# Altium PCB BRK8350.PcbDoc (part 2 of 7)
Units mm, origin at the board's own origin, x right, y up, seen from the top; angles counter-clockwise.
Board outline 240 x 150 mm, 8 copper layers (L1-TOP, L2-GND, L3-PWR, L4-SIG, L5-SIG, L6-PWR, L7-GND, L8-BOT), stack 1.465 mm thick; 277 components, 542 nets, 1814 pads, 2338 vias.

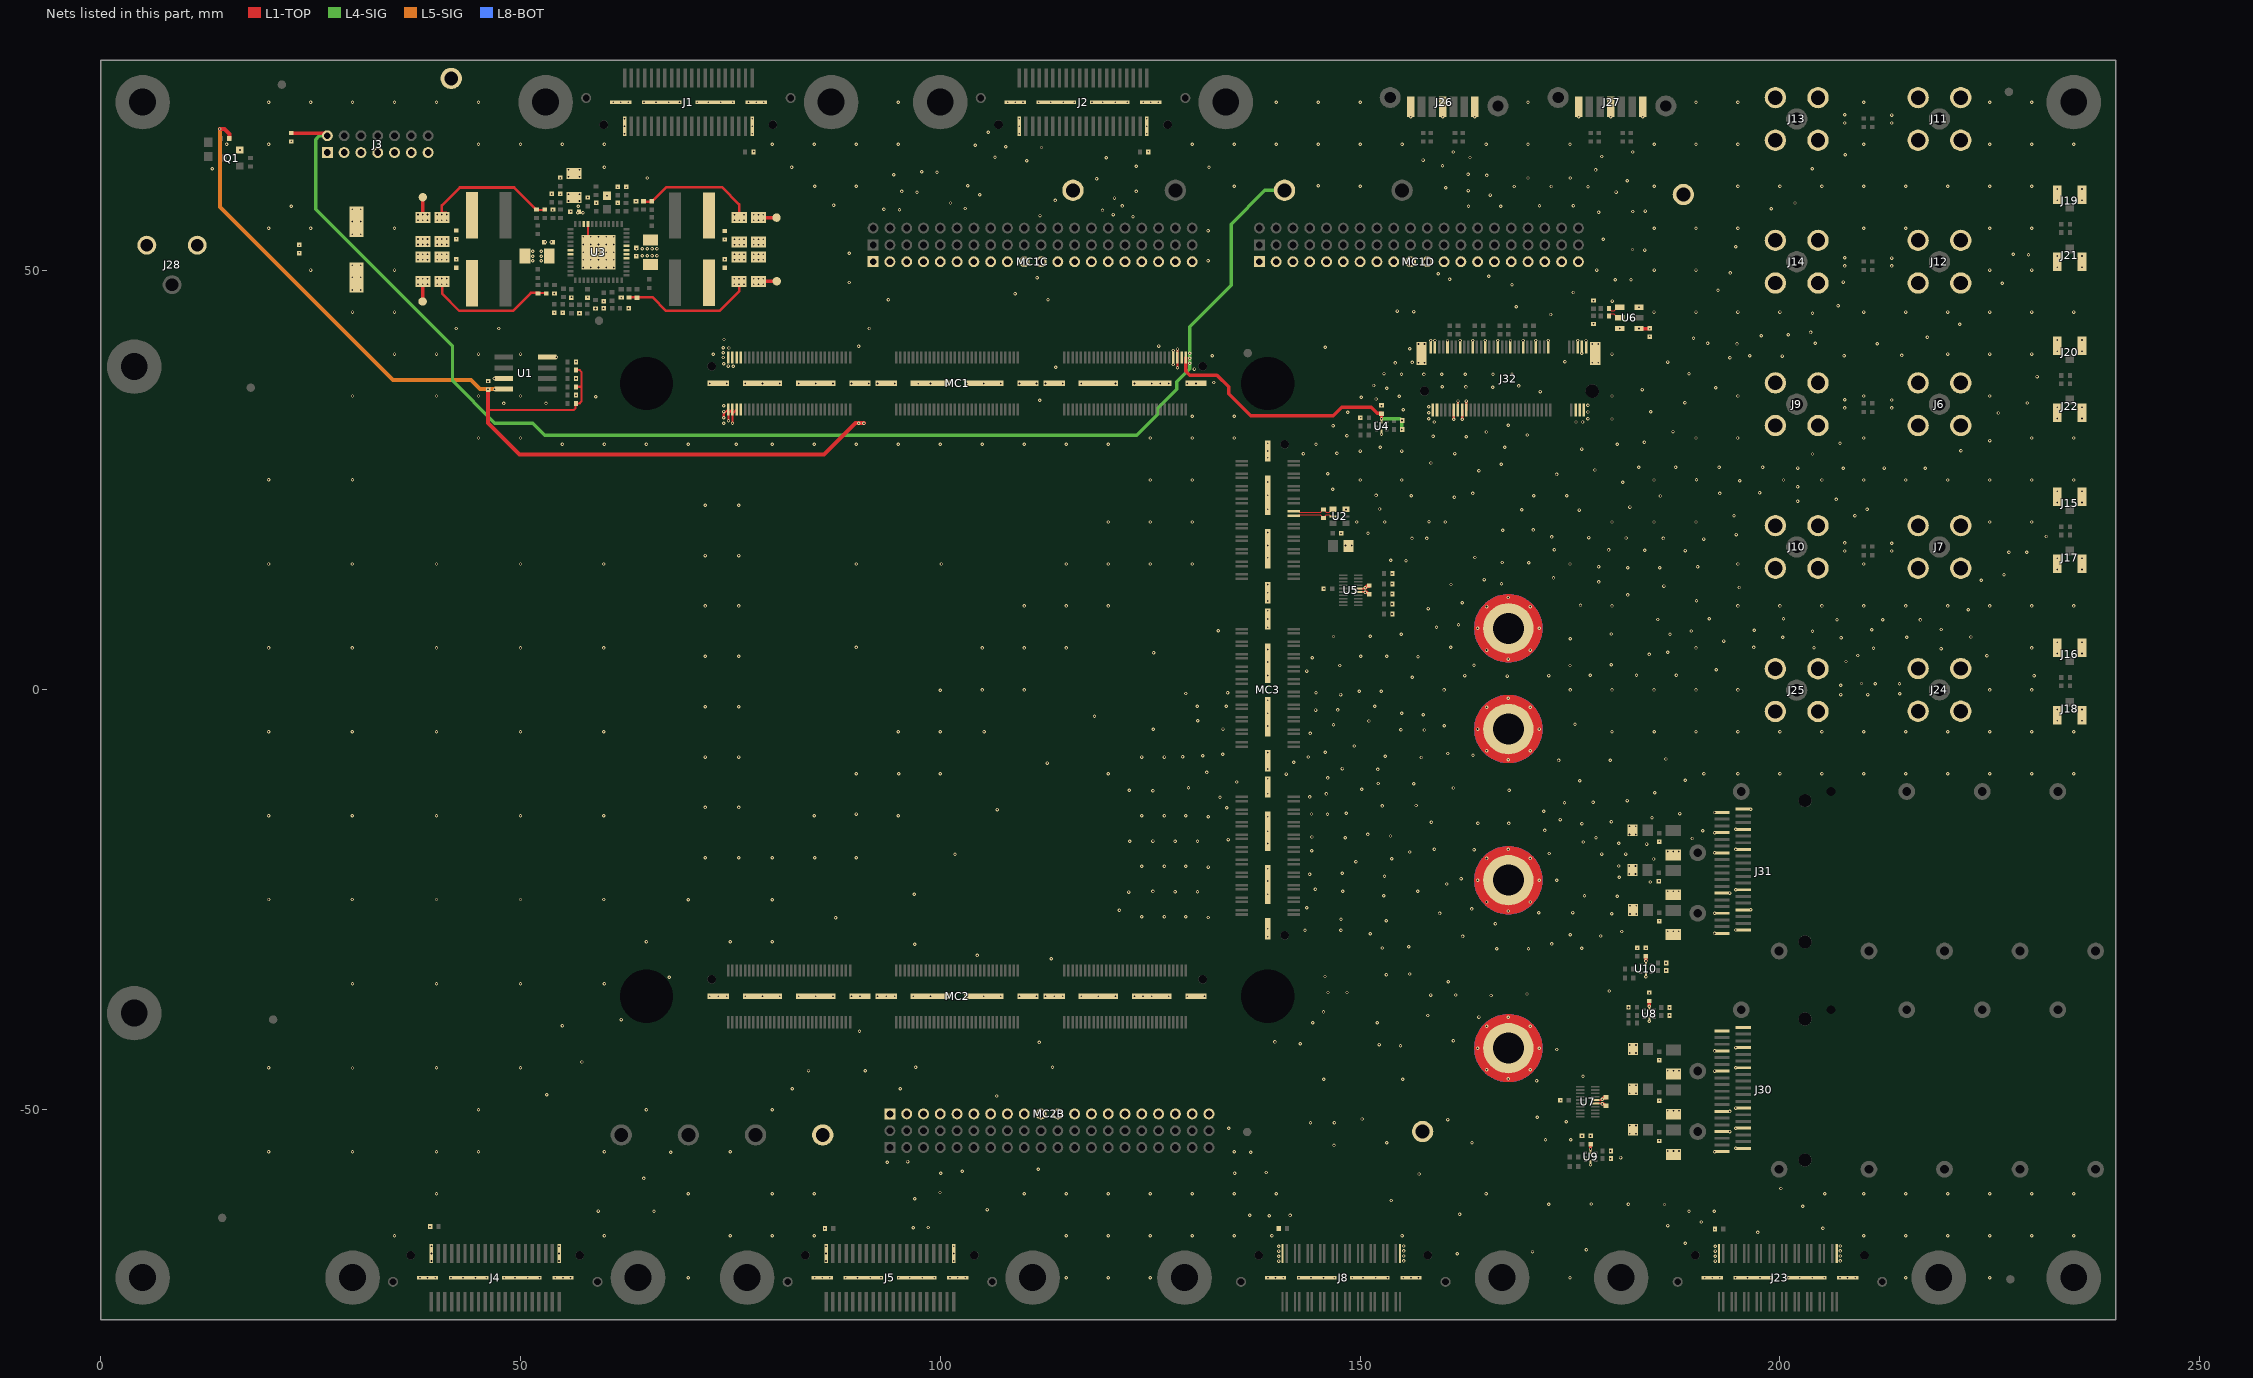
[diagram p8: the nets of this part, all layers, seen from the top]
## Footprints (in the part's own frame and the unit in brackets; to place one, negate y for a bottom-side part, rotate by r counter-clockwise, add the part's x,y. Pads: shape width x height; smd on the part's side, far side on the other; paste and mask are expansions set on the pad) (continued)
QSFP28_SINGLE_CAGE [mm]
  round 2 hole 1.05: 0(-1.1,3.1) 0(-1.1,-7.6) 0(-1.1,-16.6) 0(-1.1,-25.6) 0(-1.1,-34.6) 0(3.4,12.79) 0(10.6,12.79) 0(17.9,-21.1) 0(17.9,-12.1) 0(17.9,7.6) 0(17.9,-30.1)
  round 0 hole 1.05 unplated: 0(17.9,-3.1)
  L1-TOP keep-out region: -2.7,13.5 -2.7,-37 19.5,-37 19.5,13.5 16.5,13.5 16.5,11.1 18,11.1 18,-1.6 15.9,-1.6 15.9,-3.5 0.9,-3.5 0.9,-1.6 -1.2,-1.6 -1.2,11.1 0.3,11.1 0.3,13.5
  silkscreen extent -1.1,-48.2 17.9,12.9
QSH-020-01-X-D-DP-A-L [mm] "0.5mm hi-speed, high-density header (male), 80-pin, latching, ground protection in middle"
  rect 2.54x0.43 smd mask+0.051: 0(-8.07,0) 0(8.06,0)
  rect 4.7x0.43 smd mask+0.051: 0(-3.18,0) 0(3.17,0)
  rect 0.28x2.27 smd mask+0.051: 1(-7.25,-2.87) 2(-7.25,2.87) 3(-6.75,-2.87) 4(-6.75,2.87) 5(-5.75,-2.87) 6(-5.75,2.87) 7(-5.25,-2.87) 8(-5.25,2.87) 9(-4.25,-2.87) 10(-4.25,2.87) 11(-3.75,-2.87) 12(-3.75,2.87) 13(-2.75,-2.87) 14(-2.75,2.87) 15(-2.25,-2.87) 16(-2.25,2.87) 17(-1.25,-2.87) 18(-1.25,2.87) 19(-0.75,-2.87) 20(-0.75,2.87) 21(0.25,-2.87) 22(0.25,2.87) 23(0.75,-2.87) 24(0.75,2.87) 25(1.75,-2.87) 26(1.75,2.87) 27(2.25,-2.87) 28(2.25,2.87) 29(3.25,-2.87) 30(3.25,2.87) 31(3.75,-2.87) 32(3.75,2.87) 33(4.75,-2.87) 34(4.75,2.87) 35(5.25,-2.87) 36(5.25,2.87) 37(6.25,-2.87) 38(6.25,2.87) 39(6.75,-2.87) 40(6.75,2.87)
  round 1.2 hole 0.8 paste+0 mask+0.076: MH(-12.18,-0.5) MH(12.18,-0.5)
  round 1.02 hole 1.02 unplated paste+0: MH(-10.07,2.67) MH(10.07,2.67)
  silkscreen extent -13.4,-3.7 13.4,3.7
QTH-060-01-X-D-DP-A [mm] "2mm 1x20 Header"
  rect 2.54x0.64 smd: 0(-28.445,0) 0(-11.555,0) 0(-8.445,0) 0(8.445,0) 0(11.555,0) 0(28.445,0)
  rect 4.7x0.64 smd: 0(-23.175,0) 0(-16.825,0) 0(-3.175,0) 0(3.175,0) 0(16.825,0) 0(23.175,0)
  rect 0.3x1.45 smd: 1(-27.25,3.09) 2(-27.25,-3.09) 3(-26.75,3.09) 4(-26.75,-3.09) 5(-25.75,3.09) 6(-25.75,-3.09) 7(-25.25,3.09) 8(-25.25,-3.09) 9(-24.25,3.09) 10(-24.25,-3.09) 11(-23.75,3.09) 12(-23.75,-3.09) 13(-22.75,3.09) 14(-22.75,-3.09) 15(-22.25,3.09) 16(-22.25,-3.09) 17(-21.25,3.09) 18(-21.25,-3.09) 19(-20.75,3.09) 20(-20.75,-3.09) 21(-19.75,3.09) 22(-19.75,-3.09) 23(-19.25,3.09) 24(-19.25,-3.09) 25(-18.25,3.09) 26(-18.25,-3.09) 27(-17.75,3.09) 28(-17.75,-3.09) 29(-16.75,3.09) 30(-16.75,-3.09) 31(-16.25,3.09) 32(-16.25,-3.09) 33(-15.25,3.09) 34(-15.25,-3.09) 35(-14.75,3.09) 36(-14.75,-3.09) 37(-13.75,3.09) 38(-13.75,-3.09) 39(-13.25,3.09) 40(-13.25,-3.09) 41(-7.25,3.09) 42(-7.25,-3.09) 43(-6.75,3.09) 44(-6.75,-3.09) 45(-5.75,3.09) 46(-5.75,-3.09) 47(-5.25,3.09) 48(-5.25,-3.09) 49(-4.25,3.09) 50(-4.25,-3.09) 51(-3.75,3.09) 52(-3.75,-3.09) 53(-2.75,3.09) 54(-2.75,-3.09) 55(-2.25,3.09) 56(-2.25,-3.09) 57(-1.25,3.09) 58(-1.25,-3.09) 59(-0.75,3.09) 60(-0.75,-3.09) 61(0.25,3.09) 62(0.25,-3.09) 63(0.75,3.09) 64(0.75,-3.09) 65(1.75,3.09) 66(1.75,-3.09) 67(2.25,3.09) 68(2.25,-3.09) 69(3.25,3.09) 70(3.25,-3.09) 71(3.75,3.09) 72(3.75,-3.09) 73(4.75,3.09) 74(4.75,-3.09) 75(5.25,3.09) 76(5.25,-3.09) 77(6.25,3.09) 78(6.25,-3.09) 79(6.75,3.09) 80(6.75,-3.09) 81(12.75,3.09) 82(12.75,-3.09) 83(13.25,3.09) 84(13.25,-3.09) 85(14.25,3.09) 86(14.25,-3.09) 87(14.75,3.09) 88(14.75,-3.09) 89(15.75,3.09) 90(15.75,-3.09) 91(16.25,3.09) 92(16.25,-3.09) 93(17.25,3.09) 94(17.25,-3.09) 95(17.75,3.09) 96(17.75,-3.09) 97(18.75,3.09) 98(18.75,-3.09) 99(19.25,3.09) 100(19.25,-3.09) 101(20.25,3.09) 102(20.25,-3.09) 103(20.75,3.09) 104(20.75,-3.09) 105(21.75,3.09) 106(21.75,-3.09) 107(22.25,3.09) 108(22.25,-3.09) 109(23.25,3.09) 110(23.25,-3.09) 111(23.75,3.09) 112(23.75,-3.09) 113(24.75,3.09) 114(24.75,-3.09) 115(25.25,3.09) 116(25.25,-3.09) 117(26.25,3.09) 118(26.25,-3.09) 119(26.75,3.09) 120(26.75,-3.09)
  round 1.02 hole 1.02 unplated: MH(-29.24,2.03) MH(29.24,2.03)
  silkscreen extent -30.05,-3.05 30.05,3.05
QTH-090-01-X-D [mm]
  rect 2.54x0.64 smd: 0(-28.445,0) 0(-11.555,0) 0(-8.445,0) 0(8.445,0) 0(11.555,0) 0(28.445,0)
  rect 4.7x0.64 smd: 0(-23.175,0) 0(-16.825,0) 0(-3.175,0) 0(3.175,0) 0(16.825,0) 0(23.175,0)
  rect 0.3x1.45 smd: 1(-27.25,3.09) 2(-27.25,-3.09) 3(-26.75,3.09) 4(-26.75,-3.09) 5(-26.25,3.09) 6(-26.25,-3.09) 7(-25.75,3.09) 8(-25.75,-3.09) 9(-25.25,3.09) 10(-25.25,-3.09) 11(-24.75,3.09) 12(-24.75,-3.09) 13(-24.25,3.09) 14(-24.25,-3.09) 15(-23.75,3.09) 16(-23.75,-3.09) 17(-23.25,3.09) 18(-23.25,-3.09) 19(-22.75,3.09) 20(-22.75,-3.09) 21(-22.25,3.09) 22(-22.25,-3.09) 23(-21.75,3.09) 24(-21.75,-3.09) 25(-21.25,3.09) 26(-21.25,-3.09) 27(-20.75,3.09) 28(-20.75,-3.09) 29(-20.25,3.09) 30(-20.25,-3.09) 31(-19.75,3.09) 32(-19.75,-3.09) 33(-19.25,3.09) 34(-19.25,-3.09) 35(-18.75,3.09) 36(-18.75,-3.09) 37(-18.25,3.09) 38(-18.25,-3.09) 39(-17.75,3.09) 40(-17.75,-3.09) 41(-17.25,3.09) 42(-17.25,-3.09) 43(-16.75,3.09) 44(-16.75,-3.09) 45(-16.25,3.09) 46(-16.25,-3.09) 47(-15.75,3.09) 48(-15.75,-3.09) 49(-15.25,3.09) 50(-15.25,-3.09) 51(-14.75,3.09) 52(-14.75,-3.09) 53(-14.25,3.09) 54(-14.25,-3.09) 55(-13.75,3.09) 56(-13.75,-3.09) 57(-13.25,3.09) 58(-13.25,-3.09) 59(-12.75,3.09) 60(-12.75,-3.09) 61(-7.25,3.09) 62(-7.25,-3.09) 63(-6.75,3.09) 64(-6.75,-3.09) 65(-6.25,3.09) 66(-6.25,-3.09) 67(-5.75,3.09) 68(-5.75,-3.09) 69(-5.25,3.09) 70(-5.25,-3.09) 71(-4.75,3.09) 72(-4.75,-3.09) 73(-4.25,3.09) 74(-4.25,-3.09) 75(-3.75,3.09) 76(-3.75,-3.09) 77(-3.25,3.09) 78(-3.25,-3.09) 79(-2.75,3.09) 80(-2.75,-3.09) 81(-2.25,3.09) 82(-2.25,-3.09) 83(-1.75,3.09) 84(-1.75,-3.09) 85(-1.25,3.09) 86(-1.25,-3.09) 87(-0.75,3.09) 88(-0.75,-3.09) 89(-0.25,3.09) 90(-0.25,-3.09) 91(0.25,3.09) 92(0.25,-3.09) 93(0.75,3.09) 94(0.75,-3.09) 95(1.25,3.09) 96(1.25,-3.09) 97(1.75,3.09) 98(1.75,-3.09) 99(2.25,3.09) 100(2.25,-3.09) 101(2.75,3.09) 102(2.75,-3.09) 103(3.25,3.09) 104(3.25,-3.09) 105(3.75,3.09) 106(3.75,-3.09) 107(4.25,3.09) 108(4.25,-3.09) 109(4.75,3.09) 110(4.75,-3.09) 111(5.25,3.09) 112(5.25,-3.09) 113(5.75,3.09) 114(5.75,-3.09) 115(6.25,3.09) 116(6.25,-3.09) 117(6.75,3.09) 118(6.75,-3.09) 119(7.25,3.09) 120(7.25,-3.09) 121(12.75,3.09) 122(12.75,-3.09) 123(13.25,3.09) 124(13.25,-3.09) 125(13.75,3.09) 126(13.75,-3.09) 127(14.25,3.09) 128(14.25,-3.09) 129(14.75,3.09) 130(14.75,-3.09) 131(15.25,3.09) 132(15.25,-3.09) 133(15.75,3.09) 134(15.75,-3.09) 135(16.25,3.09) 136(16.25,-3.09) 137(16.75,3.09) 138(16.75,-3.09) 139(17.25,3.09) 140(17.25,-3.09) 141(17.75,3.09) 142(17.75,-3.09) 143(18.25,3.09) 144(18.25,-3.09) 145(18.75,3.09) 146(18.75,-3.09) 147(19.25,3.09) 148(19.25,-3.09) 149(19.75,3.09) 150(19.75,-3.09) 151(20.25,3.09) 152(20.25,-3.09) 153(20.75,3.09) 154(20.75,-3.09) 155(21.25,3.09) 156(21.25,-3.09) 157(21.75,3.09) 158(21.75,-3.09) 159(22.25,3.09) 160(22.25,-3.09) 161(22.75,3.09) 162(22.75,-3.09) 163(23.25,3.09) 164(23.25,-3.09) 165(23.75,3.09) 166(23.75,-3.09) 167(24.25,3.09) 168(24.25,-3.09) 169(24.75,3.09) 170(24.75,-3.09) 171(25.25,3.09) 172(25.25,-3.09) 173(25.75,3.09) 174(25.75,-3.09) 175(26.25,3.09) 176(26.25,-3.09) 177(26.75,3.09) 178(26.75,-3.09) 179(27.25,3.09) 180(27.25,-3.09)
  round 1.02 hole 1.02 unplated: MH(-29.24,2.03) MH(29.24,2.03)
  silkscreen extent -30.05,-3.05 30.05,3.05
RESC1005X06A [mm] "Chip Resistor, 2-Leads, Body 1.00x0.50mm, OK custom footprint"
  rect 0.5x0.6 smd mask+0.051: 1(-0.5,0) 2(0.5,0)
RESC2012N [mm] "Chip Resistor, Body 2.0x1.3mm, IPC Medium Density"
  rect 1.2x1.4 smd: 1(-0.9,0) 2(0.9,0)
  silkscreen extent -0.85,-0.89 0.85,0.88, body extent -1.07,-0.7 1.07,0.7, height 0.65
SMA [mil] "PCB-mount SMA connector"
  round 100 hole 59: 1(0,0)
  round 100 hole 67: 2(-100,100) 2(-100,-100) 2(100,100) 2(100,-100)
  Top Overlay keep-out lines w10: 170,170 -170,170 -170,-170 170,-170 170,170
  silkscreen extent -170,-170 170,170
SO-G8 [mm] "Small Outline; 8 Leads; Body Width 3.9 mm; Pitch 1.27 mm"
  rect 0.6x2.2 smd: 1(-1.905,-2.6) 2(-0.635,-2.6) 3(0.635,-2.6) 4(1.905,-2.6) 5(1.905,2.6) 6(0.635,2.6) 7(-0.635,2.6) 8(-1.905,2.6)
  silkscreen extent -2.45,-3.7 2.45,1.95
SOT23-95P240X110 [mm] "SOT-23; 3 Leads; Body 3.0 x 2.6 mm, inc. leads (LxW max)"
  rect 0.8x0.9 smd: 1(-0.95,-1) 2(0.95,-1) 3(0,1)
  silkscreen extent -1.53,-1.45 1.54,0.77
TP-PTH-65/100#1 [mil] "Test point, plated through-hole, 65/100mil"
  round 100 hole 65: 1(0,0)
TP-PTH-65/100#2 [mil] "Test point, plated through-hole, 65/100mil"
  round 100 hole 65: 1(0,0.49)
TP-PTH-65/100#3 [mil] "Test point, plated through-hole, 65/100mil"
  round 100 hole 65: 1(-4.91,0.44)
TP-SMD40 [mm] "Test point, surface-mount, 40mil"
  round 1 smd paste-2: 1(0,0)
TXB0108DQSR [mm] "TI R-PUSON-N20"
  rect 0.2x1 smd mask+0.051: 1(-1.8,-0.9) 2(-1.4,-0.9) 3(-1,-0.9) 4(-0.6,-0.9) 5(-0.2,-0.9) 6(0.2,-0.9) 7(0.6,-0.9) 8(1,-0.9) 9(1.4,-0.9) 10(1.8,-0.9) 11(1.8,0.9) 12(1.4,0.9) 13(1,0.9) 14(0.6,0.9) 15(0.2,0.9) 16(-0.2,0.9) 17(-0.6,0.9) 18(-1,0.9) 19(-1.4,0.9) 20(-1.8,0.9)
  silkscreen extent -2.16,-1.6 2.16,1.01, body extent -2,-1 2,1, height 0.5
UFL-R-SMT-1 [mm] "U.FL surface-mount coaxial connector"
  rect 1x1.05 smd paste+0: 1(0,-1.525)
  rect 1.05x2.2 smd paste+0: 2(-1.475,0) 2(1.475,0)
  silkscreen extent -1.3,-1.3 1.3,1.3
XAL60XX [mm]
  rect 1.43x5.5 smd: 1(-2.02,0) 2(2.02,0)
  silkscreen extent -3.25,-3.35 3.25,3.35
XILINX-JTAG [mm] "2mm 2x7 header"
  rect 1.3x1.3 hole 0.8: 1(-6,-1)
  round 1.3 hole 0.8: 2(-6,1) 3(-4,-1) 4(-4,1) 5(-2,-1) 6(-2,1) 7(0,-1) 8(0,1) 9(2,-1) 10(2,1) 11(4,-1) 12(4,1) 13(6,-1) 14(6,1)
  silkscreen extent -8.32,-3.15 8.32,3.15

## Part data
*1: library part OKLOGO, partnumber=ALIGNI_IGNORE
C1 C4 C6 C7 C8 C9 C10 C11 C12 C13 C14 C15 C16 C17 C18 C19 C20 C21 C22 C23 C24 C25 C26 C27 C28 C29 C75 C76 C85 C86 C88 C90 C92 C95 C96 C97 C98 C99 C100 C101 C102 C104 C107 C108 C109: library part 000070, Manufacturer=Kemet, Manufacturer_PN=C0402C104K8PACTU, ValueFloat=1E-7, x_tolerance=10
C2: library part 000070, Manufacturer=Kemet, Manufacturer_PN=C0402C104K8PACTU, ValueFloat=1E-7, x_max_operating_temp=85, x_min_operating_temp=-55, x_tolerance=10
C30: library part 001346, "Ceramic capacitor", Manufacturer="Taiyo Yuden", Tolerance (%)=20, ValueFloat=1E-5
C31: library part 000824, "Ceramic capacitor", Manufacturer="Taiyo Yuden", Tolerance (%)=20, ValueFloat=4.7E-6
C32: library part 001926, Manufacturer=TDK, ValueFloat=3.3E-6, x_tolerance=20
C33 C46 C57: library part 001172, "Ceramic Capacitor", Manufacturer=TDK, Tolerance (%)=20, ValueFloat=2.2E-5, Voltage=35V, x_voltage-rating=35
C34 C37 C47 C58: library part 001073, "Ceramic capacitor", Manufacturer="Taiyo Yuden", Tolerance (%)=10, ValueFloat=1E-7, Voltage=25V
C35 C38 C43 C45 C48 C51 C55 C56 C59 C63 C66 C67: library part 000070, "Ceramic capacitor", Manufacturer=Kemet, Tolerance (%)=10, ValueFloat=1E-7
C36: library part 001532, "Polarized", Manufacturer=Panasonic, ValueFloat=0.00022, Voltage=25V, x_tolerance=20, x_voltage-rating=25
C39 C40 C49 C50 C60 C61 C68 C69: library part 001284, "Ceramic capacitor", Manufacturer="Taiyo Yuden", Tolerance (%)=10, ValueFloat=2.2E-5
C41 C52: library part 001004, Manufacturer=Kemet, Manufacturer_PN=C0402C560J5GACTU, ValueFloat=5.6E-11, x_temperature_characteristic=C0G, x_tolerance=5
C42 C53 C64 C72: library part 000930, "Ceramic capacitor", Manufacturer=Kemet, Tolerance (%)=10, ValueFloat=4.7E-9
C44 C54 C65 C74: library part 000807, "Ceramic capacitor", Manufacturer=Kemet, Tolerance (%)=5, ValueFloat=2.2E-11
C62 C70: library part 001004, "Ceramic capacitor", Manufacturer=Kemet, Tolerance (%)=5, ValueFloat=5.6E-11
C71: library part 000400, Manufacturer=Kemet, Manufacturer_PN=C0402C101J5GACTU, ValueFloat=1E-10
C73: library part 000962, "Ceramic capacitor", Manufacturer=Murata, Tolerance (%)=3.125, ValueFloat=5E-12
C77 C78 C79 C80 C81 C82 C83 C84: library part 000333, Manufacturer="Taiyo Yuden", Manufacturer_PN=LMK105BJ224KV-F, ValueFloat=2.2E-7, x_temperature_characteristic=X5R, x_tolerance=10
C91 C93 C94 C103 C105 C106: library part 001284, Manufacturer="Taiyo Yuden", Manufacturer_PN=LMK316AB7226KL-TR, ValueFloat=2.2E-5, x_temperature_characteristic=X7R, x_tolerance=10
D1: library part 001433, "LED", Manufacturer=Dialight, Manufacturer_PN=598-8070-107F
FB1 FB2 FB3 FB4 FB5 FB6 FB7: library part 000783, Manufacturer=Murata, Manufacturer_PN=BLM21PG221SN1D, ValueFloat=220
FID1 FID2 FID3 FID4 FID5 FID6 FID7 FID8: "PCB fiducial", partnumber=ALIGNI_IGNORE
J1 J2 J4 J5: library part 001604, "0.8mm hi-speed, high-density header (male)", Manufacturer=Samtec
J3: library part 000541, "2mm header, shrouded", Manufacturer=Molex
J6 J7 J9 J10 J11 J12 J13 J14 J24 J25: library part 000974, "Straight SMA PCB Mount", Manufacturer=Amphenol, Manufacturer_PN=901-144-8RFX
J8 J23: library part 000694, "0.5mm Double Row High Speed Socket Assembly", Manufacturer=Samtec
J15 J16 J17 J18 J19 J20 J21 J22: library part 001335, "U.FL surface-mount coaxial connector", Manufacturer=Hirose, Manufacturer_PN=U.FL-R-SMT-1
J26 J27: library part 000988, "SATA 7-pin receptacle", Manufacturer=Molex
J28: library part DCPOWER, "DC power connector - high current", Manufacturer="CUI Inc.", partnumber=000356
J30 J31: library part 001782, Manufacturer=Amphenol
J32: library part 001722, Manufacturer=Amphenol
JSO1 JSO2 JSO3 JSO4: library part 001879, "Mounting hole", Manufacturer=Samtec, Manufacturer_PN=JSO-0515-01
L1 L2 L3 L4: library part 001543, "Power inductor, 2.2uH, 7A, 12.7mOhm", Manufacturer=Coilcraft, Tolerance (%)=20, ValueFloat=2.2E-6
MC1 MC2: library part 000876, "0.5mm Double Row High Speed Socket Assembly", Manufacturer=Samtec
MC1A MC1B MC2A: library part 000583, Manufacturer=Molex
MC1C MC1D MC2B: library part 001334, Manufacturer=3M, Manufacturer_PN=951120-8622-AR
MC3: library part 001769, Manufacturer=Samtec
MH1 MH2 MH5 MH6 MH7 MH8 MH9 MH10 MH11 MH12 MH13 MH14 MH15 MH16 MH17 MH18 MH19 MH20: "Mounting hole", partnumber=ALIGNI_IGNORE
Q1: library part 001237, "N-Channel MOSFET", Manufacturer="Fairchild Semiconductor", Manufacturer_PN=FDN337N, PackageDocument=1995/1996
QSFP1 QSFP2: library part 001781, Manufacturer=Amphenol, Manufacturer_PN=U95-T111-1001
R1: library part 001549, "Thick-film resistor", Manufacturer=Vishay, Tolerance (%)=1, ValueFloat=210000
R2: library part 001550, "Thick-film resistor", Manufacturer=Vishay, Tolerance (%)=1, ValueFloat=84500
R3 R4 R5 R6 R7 R8 R17 R20 R24 R29: library part 001521, Manufacturer=Vishay, Manufacturer_PN=CRCW040210K0FKED, ValueFloat=10000, x_tolerance=1
R9: library part Resistor, "Thick-film resistor", Manufacturer=Yageo, partnumber=001908, ValueFloat=8870.0
R10: library part Resistor, "Thick-film resistor", Manufacturer=Yageo, partnumber=001909, ValueFloat=6980.0
R11: library part 000827, Manufacturer=Vishay, Manufacturer_PN=CRCW0402100RFKED, ValueFloat=100, x_tolerance=1
R12: library part Resistor, "Thick-film resistor", Manufacturer=Yageo, partnumber=001910, ValueFloat=5360.0
R13: library part Resistor, "Thick-film resistor", Manufacturer=Vishay, partnumber=001007, ValueFloat=4020.0
R14 R15 R31: library part 001521, "Thick-film resistor", Manufacturer=Vishay, Tolerance (%)=1, ValueFloat=10000
R16 R19 R22: library part 001091, Manufacturer=Vishay, Manufacturer_PN=CRCW040231K6FKED, ValueFloat=31600, x_tolerance=1
R18 R21 R23 R27: library part 001121, "Thick-film resistor", Manufacturer=Vishay, Tolerance (%)=1, ValueFloat=15000
R25: library part 001122, Manufacturer=Vishay, ValueFloat=39200, x_tolerance=1
R26: library part 001157, Manufacturer=Vishay, Manufacturer_PN=CRCW040252K3FKED, ValueFloat=52300, x_tolerance=1
R28: library part 001618, "Thick-film resistor", Manufacturer=Vishay, Tolerance (%)=1, ValueFloat=374000
R30: library part 001162, "Thick-film resistor", Manufacturer=Vishay, Tolerance (%)=1, ValueFloat=2000
R32 R37 R38 R39 R41: library part 001035, Manufacturer=Vishay, Manufacturer_PN=CRCW040249K9FKED, ValueFloat=49900, x_tolerance=1
R33 R34 R35 R36 R45 R46 R47 R48 R49 R50 R51 R52 R57 R58 R62 R63: library part 001126, Manufacturer=Vishay, Manufacturer_PN=CRCW04023K01FKED, ValueFloat=3010, x_tolerance=1
R40 R61: library part 001713, Manufacturer=Vishay, Manufacturer_PN=CRCW04020000Z0EDC, ValueFloat=0, x_tolerance=1
R59 R60: library part 001715, Manufacturer=Vishay, Manufacturer_PN=CRCW040249R9FKEDC, ValueFloat=49.9, x_tolerance=1
SO1 SO2 SO3 SO4: library part 9774025151R, "SMT steel standoff, M2.5 threads, 2.5 mm stack height", Manufacturer=Wurth, partnumber=001726
TP1 TP2 TP3 TP4 TP6 TP7 TP9 TP10 TP12 TP13 TP15: library part TP-PTH-65/100, "Test point, plated through-hole, 65/100mil", partnumber=ALIGNI_IGNORE
TP17 TP18 TP19 TP20: library part TESTPOINT-SMD40, "Test point, surface-mount, 40mil"
TP21: "Test point, surface-mount, 40mil"
U1: library part 000842, Manufacturer=Microchip
U2: library part 001241, Manufacturer=Abracon
U3: library part 001511, "4-channel switching regulator with PMBus", Manufacturer="Texas Instruments"
U4 U8 U9 U10: library part 001559, Manufacturer="ON Semiconductor"
U5 U7: library part 001324, Manufacturer="Texas Instruments"
U6: library part 001804, Manufacturer=Abracon

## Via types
v1: diameter 0.406, hole 0.203, L1-TOP to L8-BOT, tented both sides, 2338 vias

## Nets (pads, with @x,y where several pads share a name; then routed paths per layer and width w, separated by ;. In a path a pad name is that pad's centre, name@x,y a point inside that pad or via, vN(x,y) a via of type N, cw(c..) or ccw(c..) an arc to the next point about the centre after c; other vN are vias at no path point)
"100MHZ _REFCLK_P": MC3.17 R11.2 U2.4 | length 4.9
  L1-TOP w0.107: MC3.17@142.294,21.25 142.705,21.25 142.795,21.16 145.31,21.16 R11.2@145.636,21.487 145.962,21.16 146.318,21.16 146.651,21.494 U2.4@146.779,21.494
100MHZ_OSC_N: R61.2 U6.5 | length 1.7
  L1-TOP w0.107: R61.2@179.599,44.52 179.896,44.817 180.226,44.817 180.733,44.309 U6.5@180.917,44.309
100MHZ_OSC_P: R40.2 U6.4 | length 1.6
  L1-TOP w0.107: R40.2@179.599,45.434 179.896,45.137 180.251,45.137 180.694,45.579 U6.4@180.917,45.579
100MHZ_REFCLK_N: MC3.19 R11.1 U2.5 | length 4.9
  L1-TOP w0.107: MC3.19@142.294,20.75 142.691,20.75 142.781,20.84 145.282,20.84 R11.1@145.636,20.487 145.99,20.84 146.316,20.84 146.487,20.669 U2.5@146.779,20.669
+1.8VDD: C1.2 C76.2 J3.2 MC1.177 MC1.179 R35.2 R36.2 TP7.1 U4.8 | length 196.1
  L1-TOP w0.406: C1.2@22.7,66.278 26.722,66.278 J3.2@27,66 ; MC1.179@129.25,39.59 129.25,37.932 129.692,37.49 132.957,37.49 134.366,36.082 134.366,35.281 136.982,32.664 146.787,32.664 147.792,33.669 151.33,33.669 152.066,32.934 152.549,32.934 C76.2@152.549,32.884 v1(152.549,32.31)
  L4-SIG w0.406: J3.2@27,66 26.057,66 25.608,65.551 25.608,57.245 41.91,40.943 41.91,36.805 46.939,31.775 51.449,31.775 52.908,30.316 123.382,30.316 125.933,32.868 125.933,33.604 128.143,35.814 128.143,36.703 129.713,38.273 v1(129.713,38.894) v1(129.713,39.5) v1(129.713,40.1) 129.713,43.251 134.638,48.176 134.638,55.48 138.658,59.5 TP7.1@141,59.5 ; v1(152.549,32.31) 154.769,32.31 v1(154.981,32.098) 154.981,31.024 v1(154.976,31.02)
+3.3V_M.2: C48.2 C49.2 C50.2 C52.2 C86.2 C88.2 FB7.1 J32.2 J32.4 J32.12 J32.14 J32.16 J32.18 J32.70 J32.72 J32.74 L2.2 R19.2 R32.2 R37.2 R38.2 R39.2 R41.2 TP18.1 U5.16 U6.1 U6.6 | length 23.9
  L1-TOP w0.178: U5.16@149.798,12.069 150.677,12.069 v1@150.775,12.167
  L1-TOP w0.279: v1(161.158,32.224) J32.12@161.158,33.311 ; J32.14@161.658,33.311 v1(161.658,34.398) ; v1(162.158,32.224) J32.16@162.158,33.311 ; J32.18@162.658,33.311 v1(162.658,34.398)
  L1-TOP w0.305: R19.2@64.677,58.152 64.687,58.162 65.642,58.162 67.372,59.892 73.99,59.892 76.052,57.83 C49.2@76.052,56.267
  L1-TOP w0.406: C50.2@78.351,56.267 78.367,56.252 TP18.1@80.498,56.252 ; v1(150.622,12.167) 150.803,12.347 C86.2@151.079,12.347 ; v1(183.217,43.039) 183.232,43.024 v1(184.508,43.024)
  other v1: 153.808,9.037 153.808,10.237 153.808,11.436 153.808,12.637 153.808,13.837 148.252,17.202 149.014,17.202 158.819,31.909 175.71,31.909 176.497,31.909 158.184,32.284 177.132,32.284 158.184,33.026 177.132,33.102 158.184,33.737 177.132,33.915 180.917,43.039 75.486,55.929 76.044,55.929 76.629,55.929 77.785,55.929 78.344,55.929 78.928,55.929 75.486,56.589 76.629,56.589 77.785,56.589 78.344,56.589 78.928,56.589
+3.3V_QSFP: C38.2 C39.2 C40.2 C41.2 C97.2 C99.2 C101.2 C109.2 FB1.1 FB2.1 FB3.2 FB4.1 FB5.1 FB6.2 L1.2 R16.2 R47.2 R48.2 R51.2 R52.2 R62.2 R63.2 TP17.1 U7.16 U8.8 U9.8 U10.8 | length 22.9
  L1-TOP w0.178: U7.16@178.008,-48.851 178.887,-48.851 v1@178.984,-48.753
  L1-TOP w0.305: C41.2@63.883,46.761 62.928,46.761 62.918,46.771 65.706,46.771 67.335,45.142 73.729,45.142 76.044,47.458 C39.2@76.044,48.658 ; C40.2@78.351,48.296 C40.2@78.351,48.658
  L1-TOP w0.406: C40.2@78.351,48.658 78.366,48.673 TP17.1@80.523,48.673 ; v1(177.441,-54.686) 177.441,-54.061 C101.2@177.449,-54.054 ; v1(178.832,-48.753) 179.012,-48.572 C97.2@179.289,-48.572 ; v1(184.041,-32.28) C109.2@184.041,-31.723 C109.2@184.041,-31.673 ; C99.2@184.428,-37.004 184.447,-37.024 v1(184.447,-37.662)
  other v1: 179.829,-55.829 179.829,-54.915 182.11,-52.856 182.85,-52.856 182.11,-51.89 182.85,-51.89 182.11,-48.046 182.85,-48.046 182.11,-47.081 182.85,-47.081 182.11,-43.249 182.85,-43.249 182.11,-42.284 182.85,-42.284 186.858,-38.754 186.858,-37.84 186.421,-33.423 186.421,-32.519 182.136,-26.689 182.876,-26.689 182.136,-25.724 182.876,-25.724 182.06,-21.935 182.8,-21.935 182.06,-20.97 182.8,-20.97 182.085,-17.211 182.825,-17.211 182.085,-16.245 182.825,-16.245 75.478,48.319 76.037,48.319 76.621,48.319 77.785,48.319 78.344,48.319 78.928,48.319 75.478,48.979 76.037,48.979 76.621,48.979 77.785,48.979 78.344,48.979 78.928,48.979
+3.3V_SZG: C59.2 C60.2 C61.2 C62.2 J1.40 J2.40 J4.40 J5.40 J8.40 J23.40 L3.2 R22.2 TP19.1 | length 18.5
  L1-TOP w0.229: C60.2@40.649,56.844 C60.2@41.221,56.844 ; R22.2@51.926,57.162 52.882,57.162 C62.2@52.892,57.172
  L1-TOP w0.254: C60.2@40.357,56.59 C60.2@40.662,56.285
  L1-TOP w0.305: C60.2@40.649,56.844 40.649,57.69 42.793,59.834 49.254,59.834 R22.2@51.926,57.162
  L1-TOP w0.406: C61.2@38.372,56.285 TP19.1@38.372,58.68
  other v1: 54.6,-68.024 101.6,-68.024 155.201,-68.01 207.201,-68.01 155.201,-67.426 207.201,-67.426 54.6,-67.135 101.6,-67.135 155.201,-66.817 207.201,-66.817 54.6,-66.246 101.6,-66.246 155.201,-66.232 207.201,-66.232 37.788,55.952 38.346,55.952 38.931,55.952 40.078,55.952 40.637,55.952 41.221,55.952 37.788,56.613 38.931,56.613 40.078,56.613 40.637,56.613 41.221,56.613 38.346,56.617 62.401,66.246 109.401,66.246 62.401,67.135 109.401,67.135 62.401,68.024 109.401,68.024
+3.3VDD: C2.2 MC1.173 MC1.175 R3.2 R4.2 R5.2 R30.2 TP4.1 U1.8 | length 123.9
  L1-TOP w0.254: 46.144,33.331 56.34,33.331 56.569,33.56 56.569,34.118 R3.2@56.619,34.118 57.026,34.118 57.254,34.347 57.254,36.1 ; C2.2@46.144,35.767 v1(46.144,35.817) ; R4.2@56.569,36.1 R4.2@56.619,36.1 57.254,36.1 ; R5.2@56.569,38.081 R5.2@56.619,38.081 57.057,38.081 57.254,37.884 57.254,36.1
  L1-TOP w0.279: v1(128.25,38.386) MC1.175@128.25,39.59 v1(128.25,40.595)
  L1-TOP w0.483: v1(14.199,66.802) 14.757,66.802 15.327,66.232 R30.2@15.327,65.665 ; C2.2@46.144,35.767 46.144,33.331 46.144,31.809 49.911,28.042 86.149,28.042 89.883,31.775 v1(90.297,31.775) v1(90.907,31.775)
  L5-SIG w0.483: v1(14.199,66.802) 14.199,57.506 34.798,36.906 44.094,36.906 45.18,35.82 v1(46.904,35.82)
  other v1: 127.738,38.755 127.738,40.425
+5V_SZG: C67.2 C68.2 C69.2 C70.2 J1.2 J2.2 J4.2 J5.2 J8.2 J23.2 L4.2 R26.2 TP20.1 | length 18
  L1-TOP w0.203: R26.2@52.104,47.277 52.114,47.267 C70.2@53.069,47.267
  L1-TOP w0.305: C68.2@40.662,48.658 40.662,47.186 42.706,45.142 49.108,45.142 51.243,47.277 R26.2@52.104,47.277
  L1-TOP w0.406: TP20.1@38.346,46.26 38.346,48.632 C69.2@38.372,48.658
  other v1: 140.299,-68.028 192.299,-68.028 39.398,-68.024 86.398,-68.024 140.299,-67.444 192.299,-67.444 39.398,-67.135 86.398,-67.135 140.299,-66.834 192.299,-66.834 140.299,-66.25 192.299,-66.25 39.398,-66.246 86.398,-66.246 37.788,48.325 38.346,48.325 38.931,48.325 40.078,48.33 40.637,48.33 41.221,48.33 37.788,48.986 38.346,48.986 38.931,48.986 40.078,48.99 40.637,48.99 41.221,48.99 77.603,66.246 124.603,66.246 77.603,67.135 124.603,67.135 77.603,68.024 124.603,68.024
+VDCIN: C33.1 C34.1 C36.1 C37.2 C46.1 C47.1 C57.1 C58.1 J28.1 MC1.1 MC1.2 MC1.3 MC1.4 MC1.5 MC1.6 MC1.7 MC1.8 TP2.1 U3.5 U3.6 U3.22 U3.30 U3.31 | length 4.7
  L1-TOP w0.254: v1@74.143,40.698 v1(74.143,40.742) ; v1(74.214,32.41) 74.214,32.874 MC1.2@74.75,33.41 ; v1(74.778,32.073) 74.778,32.938 MC1.4@75.25,33.41 ; v1(75.25,31.745) 75.25,32.91 MC1.6@75.75,33.41
  other v1: 74.214,31.75 74.219,33.147 74.214,33.859 74.75,38.568 75.336,38.557 74.193,38.837 74.138,39.59 74.138,40.138 74.828,40.716 52.473,51.098 52.473,51.657 63.807,51.71 64.499,51.71 65.084,51.71 65.674,51.71 66.252,51.71 52.473,52.241 23.665,52.968 53.667,53.333 29.964,54.281 30.98,54.281 29.964,55.78 30.98,55.78 56.829,56.82 57.438,56.82 29.964,57.24 30.98,57.24 56.888,57.613 55.725,58.219 57.036,58.219 55.725,59.036 57.036,59.036
DGND: C1.1 C2.1 C4.1 C30.1 C31.1 C32.1 C33.2 C34.2 C36.2 C37.1 C38.1 C39.1 C40.1 C42.2 C43.2 C44.2 C46.2 C47.2 C48.1 C49.1 C50.1 C51.1 C53.2 C54.2 C55.2 C57.2 C58.2 C59.1 C60.1 C61.1 C63.2 C64.2 C65.2 C67.1 C68.1 C69.1 C72.2 C73.1 C74.2 C75.1 C76.1 C85.1 C86.1 C88.1 C90.1 C91.1 C92.1 C93.1 C94.1 C95.1 C96.1 C97.1 C98.1 C99.1 C100.1 C101.1 C102.1 C103.1 C104.1 C105.1 C106.1 C107.1 C108.1 C109.1 J1.0 J2.0 J3.1 J3.3 J3.5 J3.7 J3.9 J3.11 J3.13 J4.0 J5.0 J6.2 J7.2 J8.0 J9.2 J10.2 J11.2 J12.2 J13.2 J14.2 J15.2 J16.2 J17.2 J18.2 J19.2 J20.2 J21.2 J22.2 J23.0 J24.2 J25.2 J26.1 J26.4 J26.7 J27.1 J27.4 J27.7 J28.2 J30.1 J30.4 J30.7 J30.13 J30.16 J30.19 J30.20 J30.23 J30.26 J30.32 J30.35 J30.38 J31.1 J31.4 J31.7 J31.13 J31.16 J31.19 J31.20 J31.23 J31.26 J31.32 J31.35 J31.38 J32.1 J32.3 J32.9 J32.15 J32.21 J32.27 J32.33 J32.39 J32.45 J32.51 J32.57 J32.71 J32.73 J32.75 MC1.0 MC1C.1 MC1C.2 MC1C.3 MC1C.4 MC1C.5 MC1C.6 MC1C.7 MC1C.8 MC1C.9 MC1C.10 MC1C.11 MC1C.12 MC1C.13 MC1C.14 MC1C.15 MC1C.16 MC1C.17 MC1C.18 MC1C.19 MC1C.20 MC1D.1 MC1D.2 MC1D.3 MC1D.4 MC1D.5 MC1D.6 MC1D.7 MC1D.8 MC1D.9 MC1D.10 MC1D.11 MC1D.12 MC1D.13 MC1D.14 MC1D.15 MC1D.16 MC1D.17 MC1D.18 MC1D.19 MC1D.20 MC2.0 MC2B.1 MC2B.2 MC2B.3 MC2B.4 MC2B.5 MC2B.6 MC2B.7 MC2B.8 MC2B.9 MC2B.10 MC2B.11 MC2B.12 MC2B.13 MC2B.14 MC2B.15 MC2B.16 MC2B.17 MC2B.18 MC2B.19 MC2B.20 MC3.0 Q1.2 R1.1 R2.1 R6.1 R7.1 R8.1 R9.1 R10.1 R12.1 R13.1 R17.1 R20.1 R24.1 R25.1 R28.1 R29.1 R59.1 R60.1 SO1.1 SO2.1 SO3.1 SO4.1 TP10.1 TP13.1 TP15.1 U1.4 U1.7 U2.3 U3.7 U3.8 U3.21 U3.PAD U4.4 U5.15 U6.3 U7.15 U8.4 U9.4 U10.4 | length 172.6
  L1-TOP w0.178: U5.15@149.798,11.669 150.561,11.669 v1(150.622,11.608) ; U7.15@178.008,-49.251 178.771,-49.251 v1(178.832,-49.312)
  L1-TOP w0.203: R28.1@57.99,46.764 v1(57.997,46.757)
  L1-TOP w0.279: U3.21@58.042,55.49 58.042,53.39 v1(59.292,52.14)
  L1-TOP w0.406: v1(150.622,11.608) 150.775,11.608 150.955,11.427 C86.1@151.079,11.427 ; v1(178.832,-49.312) 178.984,-49.312 179.165,-49.492 C97.1@179.289,-49.492
  L1-TOP w1.524: 170.96,-42.664 ccw(c167.658,-42.664) 170.96,-42.664 ; 170.96,-22.664 ccw(c167.658,-22.664) 170.96,-22.664 ; 170.96,-4.664 ccw(c167.658,-4.664) 170.96,-4.664 ; 170.96,7.336 ccw(c167.658,7.336) 170.96,7.336
  L8-BOT w1.524: 170.96,-42.664 ccw(c167.658,-42.664) 170.96,-42.664 ; 170.96,-22.664 ccw(c167.658,-22.664) 170.96,-22.664 ; 170.96,-4.664 ccw(c167.658,-4.664) 170.96,-4.664 ; 170.96,7.336 ccw(c167.658,7.336) 170.96,7.336
  other v1: 38.041,-70.002 38.935,-70 39.844,-70.002 41.724,-70.002 43.146,-70.002 44.645,-70.002 45.94,-70.002 48.06,-69.999 49.355,-69.999 50.854,-69.999 52.276,-69.999 54.156,-69.999 55.064,-70 55.959,-69.999 70,-70.002 85.041,-70.002 85.935,-70 86.844,-70.002 88.724,-70.002 90.146,-70.002 91.645,-70.002 92.94,-70.002 95.06,-69.999 96.355,-69.999 97.854,-69.999 99.276,-69.999 101.156,-69.999 102.064,-70 102.959,-69.999 115.001,-69.999 120,-70.002 125,-70.002 139.035,-70.002 139.93,-70 140.839,-70.002 142.718,-70.002 144.141,-70.002 145.639,-70.002 146.935,-70.002 149.055,-69.999 150.35,-69.999 151.849,-69.999 153.271,-69.999 155.151,-69.999 156.059,-70 156.954,-69.999 175,-69.999 191.035,-70.002 191.93,-70 192.839,-70.002 194.718,-70.002 196.141,-70.002 197.639,-70.002 198.935,-70.002 201.055,-69.999 202.35,-69.999 203.849,-69.999 205.271,-69.999 207.151,-69.999 208.059,-70 208.954,-69.999 215,-70.002 225,-69.999 161.569,-67.144 170.528,-66.897 176.954,-66.669 188.714,-65.907 35,-65 60,-65 75,-65 80,-65 85,-65 115.001,-65 120,-65 125,-65 130,-65 135,-65 139.497,-65 155,-65 210,-65 215,-65 220,-65 225,-65 230,-65 235,-65 197.376,-64.611 192.25,-64.23 86.252,-64.154 205.123,-64.103 96.792,-64.053 98.57,-64.027 39.235,-63.926 186.632,-63.799 190.619,-63.367 139.192,-62.636 141.656,-62.586 136.855,-62.56 161.849,-62.433 65.905,-62.097 189.172,-62.097 192.169,-62.097 59.251,-62.071 105.606,-61.894 202.735,-61.487 186.251,-61.284 172.458,-61.259 181.958,-61.259 177.513,-61.233 153.692,-60.808 96.944,-60.598 40,-60 70,-60 80,-60 85,-60 110,-60 115.001,-60 120,-60 125,-60 130,-60 135,-60 140,-60 165,-60 205.334,-60.02 210,-60 215,-60 220,-60 225,-60 230,-60 235,-60 99.967,-59.862 200.119,-59.379 64.694,-58.185 157.023,-57.658 135.052,-57.582 100.043,-57.55 138.836,-57.48 102.608,-57.322 111.664,-57.08 177.441,-56.566 93.668,-56.255 96.106,-56.179 181.018,-55.696 67.887,-55.061 136.982,-55.061 20,-55 30,-55 40,-55 45,-55 60,-55 75,-55 135,-55 192.22,-55 186.657,-54.913 187.317,-54.913 187.978,-54.913 194.73,-54.6 146.888,-54.254 153.18,-53.943 163.322,-53.943 185.641,-53.671 172.077,-53.562 175.075,-53.562 176.421,-53.134 177.449,-53.134 194.021,-52.6 134.341,-52.2 194.73,-52.2 144.094,-51.562 146.939,-51.537 174.541,-51.429 160.452,-51.174 150.233,-51.104 171.112,-50.895 194.021,-50.2 186.657,-50.129 187.317,-50.129 187.978,-50.129 45,-50 65,-50 80,-50 194.73,-49.8 173.891,-48.86 185.641,-48.87 106.731,-48.362 53.129,-48.203 95.225,-47.516 82.372,-47.498 171.018,-46.533 145.669,-46.355 155.067,-46.355 167.658,-46.33 176.544,-45.999 192.22,-45.4 91.059,-45.364 186.657,-45.354 187.317,-45.354 187.978,-45.354 84.303,-45.339 165.065,-45.256 170.25,-45.256 30,-45.028 20,-45 40,-45 50,-45 194.73,-45 97.053,-44.958 113.36,-44.933 57.32,-44.317 185.641,-44.061 192.22,-43 173.406,-42.824 163.992,-42.664 171.324,-42.664 194.73,-42.6 154.813,-42.393 152.273,-42.24 142.875,-42.139 111.785,-41.986 139.852,-41.929 161.112,-41.783 90.373,-40.64 165.065,-40.072 170.25,-40.072 55,-40 152.044,-39.649 144.374,-39.624 184.447,-39.459 62,-39.262 167.658,-38.998 164.153,-38.964 158.058,-38.78 145.644,-38.354 181.962,-37.814 72.534,-36.5 73.555,-36.5 74.577,-36.5 76.783,-36.5 78.825,-36.5 80.868,-36.5 83.133,-36.5 85.175,-36.5 87.218,-36.5 89.424,-36.5 90.445,-36.5 92.534,-36.5 93.555,-36.5 94.577,-36.5 96.783,-36.5 98.825,-36.5 100.868,-36.5 103.133,-36.5 105.175,-36.5 107.218,-36.5 109.424,-36.5 111.467,-36.5 112.534,-36.5 113.555,-36.5 114.577,-36.5 116.783,-36.5 118.825,-36.5 120.868,-36.5 123.133,-36.5 124.154,-36.5 125.175,-36.5 127.218,-36.5 129.424,-36.5 131.467,-36.5 165.6,-36.392 158.408,-36.347 161.384,-36.341 169.875,-36.22 184.453,-36.088 146.177,-36.038 148.438,-36.043 179.672,-35.859 30,-35 40,-35 50,-35 60,-35 160.495,-34.766 67.716,-34.239 184.041,-34.152 145.821,-34.138 153.137,-33.909 155.905,-33.833 113.208,-32.029 104.394,-31.623 166.268,-30.836 170.053,-30.836 176.408,-30.753 183.025,-30.753 184.041,-30.753 152.629,-30.734 155.804,-30.582 96.952,-30.302 172.839,-30.251 65,-30 75,-30 80,-30 139,-29.408 162.204,-29.362 178.649,-29.312 175.031,-29.159 151.199,-29.032 192.219,-29 181.168,-28.778 186.632,-28.747 187.292,-28.747 187.952,-28.747 143.434,-28.626 147.712,-28.626 194.729,-28.6 139,-28.445 166.116,-27.838 153.111,-27.504 185.641,-27.505 147.726,-27.33 87.528,-27.153 131.928,-27.102 124,-27 126.695,-27 129.235,-27 179.959,-26.645 159.461,-26.619 192.219,-26.6 171.272,-26.537 175.336,-26.518 167.658,-26.33 121.336,-26.238 196.531,-26.2 163.297,-26.086 143.648,-25.933 165.065,-25.256 170.25,-25.256 69.997,-25 80,-25 20,-24.962 29.964,-24.962 40,-24.962 50,-24.962 59.934,-24.962 180.637,-24.587 152.832,-24.505 176.726,-24.505 96.901,-24.333 139,-24.333 194.021,-24.2 122.453,-24.079 127.965,-24.028 130.632,-24.028 125.324,-24.003 147.922,-23.997 186.632,-23.992 187.292,-23.992 187.952,-23.992 156.854,-23.978 194.729,-23.8 144.678,-23.749 160.325,-23.114 184.549,-22.879 139.007,-22.758 185.59,-22.751 163.992,-22.664 171.324,-22.664 173.406,-22.657 162.027,-22.504 180.866,-22.295 152.908,-22.2 143.985,-21.965 147.879,-21.819 139.007,-21.285 131.928,-21.102 124,-21 126.695,-21 129.235,-21 180.815,-20.974 149.504,-20.472 184.955,-20.136 153.772,-20.117 165.065,-20.072 170.25,-20.072 72,-20 76,-20 80,-20 85.041,-20 90,-20 101.75,-19.558 178.783,-19.552 181.653,-19.552 172.542,-19.482 192.219,-19.4 155.898,-19.304 186.632,-19.243 187.292,-19.243 187.952,-19.243 144.239,-19.171 163.576,-19.025 167.658,-18.998 194.729,-19 158.852,-18.961 184.117,-18.358 139,-18.288 180.79,-18.256 176.564,-18.11 122.555,-18.034 127.965,-18.028 130.632,-18.028 185.616,-18.026 125.324,-18.003 134.282,-17.825 189.578,-17.698 148.227,-17.621 178.097,-17.621 144.264,-17.52 153.619,-17.399 150.919,-17.215 192.219,-17 139,-16.825 190.797,-16.758 171.983,-16.739 194.729,-16.6 176.421,-15.951 167.691,-15.9 164.033,-15.875 158.496,-15.773 179.934,-15.697 173.838,-15.443 184.76,-15.215 131.928,-15.102 139.007,-15.113 85,-15 95,-15 124,-15 126.695,-15 129.235,-15 20,-14.98 29.964,-14.98 40,-14.98 50,-14.98 59.934,-14.98 90,-14.788 146.119,-14.802 144.214,-14.777 188.079,-14.726 148.354,-14.7 192.219,-14.6 171.882,-14.453 106.788,-14.249 196.531,-14.2 134.104,-14.04 72,-14 76,-14 152.629,-13.818 156.667,-13.767 174.346,-13.437 177.749,-13.386 181.813,-13.183 133.317,-12.77 144.01,-12.745 145.992,-12.389 139,-12.354 185.09,-12.243 125.324,-12.003 122.504,-11.963 167.742,-11.938 150.19,-11.836 161.112,-11.678 129.565,-11.659 156.38,-11.176 152.171,-11.151 135.295,-10.967 176.174,-10.82 188.714,-10.744 139,-10.576 146.144,-10.484 141.216,-10.027 90,-10 95.06,-10 100,-10 120,-10 195,-10 200,-10 205,-10 210,-10 215,-10 220,-10 225,-10 230,-10 235,-10 190.95,-9.976 131.75,-9.83 152.095,-9.474 139,-9.408 147.897,-9.373 112.725,-8.712 142.105,-8.63 173.634,-8.401 179.781,-8.382 167.658,-8.33 186.421,-8.23 157.302,-8.052 72,-8 76,-8 124,-8 126.695,-8 143.807,-7.995 128.854,-7.95 152.984,-7.899 131.242,-7.849 163.449,-7.772 133.629,-7.671 160.426,-7.569 139,-7.452 145.865,-7.442 165.065,-7.256 170.25,-7.256 149.301,-6.68 144.069,-5.182 20,-5 29.964,-5 40,-5 50,-5 59.934,-5 95,-5 100,-5 105.212,-5 180,-5 185.031,-5 190,-5 195,-5 200,-5 205,-5 210,-5 215,-5 220,-5 225,-5 230,-5 235,-5 157.658,-4.775 154.864,-4.75 125.349,-4.699 133.673,-4.664 163.992,-4.664 171.324,-4.664 139.007,-4.292 160.02,-4.267 146.83,-4.166 175.59,-4.089 151.053,-3.708 130.658,-3.683 233.025,-3.669 235.975,-3.669 118.364,-3.124 157.531,-2.946 139.007,-2.768 154.965,-2.769 144.696,-2.404 147.345,-2.388 233.025,-2.331 235.975,-2.331 165.065,-2.072 170.25,-2.072 72,-2 76,-2 151.74,-1.956 130.607,-1.93 134.061,-1.93 139,-1.244 167.658,-0.998 147.676,-0.559 207.231,-0.553 210.457,-0.553 214.267,-0.451 129.235,-0.432 134.214,-0.356 144.747,-0.349 149.885,-0.152 152.527,-0.152 100,-0.029 105,0 110,0 160,0 175.02,0 180,0 185,0 190,0 195,0 225,0 230,0 207.256,0.54 211.346,0.743 214.241,0.743 209.72,0.768 156.21,1.524 167.538,1.651 230.269,1.683 162.451,1.708 172.458,1.708 139,1.728 182.923,1.733 187.673,1.733 177.411,1.759 143.655,2.241 192.423,2.394 147.592,2.902 175,2.902 163.568,2.953 179.901,3.003 139.007,3.328 207.866,3.384 167.658,3.67 144.315,3.842 156.896,3.962 72,4 76,4 150.093,4.019 153.187,4.013 224.655,4.07 209.263,4.096 184.453,4.223 233.025,4.331 235.975,4.331 125.4,4.42 186.632,4.477 165.065,4.744 170.25,4.744 139,4.801 219.194,4.908 211.143,4.959 20,5 29.964,5 40,5 50,5 59.934,5 105,5 110,5 115,5 190,5 230,5 204.056,5.01 90,5.061 196.893,5.061 160.782,5.08 233.025,5.669 235.975,5.669 193.294,5.817 175.031,6.096 207.282,6.204 200.348,6.255 215.105,6.255 222.75,6.305 146.83,6.356 151.199,6.407 154.907,6.636 186.911,6.636 179.908,6.655 203.878,6.991 189.451,7.017 133.096,7.061 196.944,7.118 210.939,7.169 219.22,7.194 163.992,7.336 171.324,7.336 159.098,7.448 139,7.467 161.714,7.753 216.731,8.337 206.799,8.363 212.235,8.363 185.463,8.388 139,8.445 191.585,8.464 200.424,8.464 139,9.424 222.42,9.557 158.133,9.684 165.065,9.928 170.25,9.928 72,10 76,10 110,10 115,10 120,10 180,10 195,10 200,10 205,10 210,10 215,10 220,10 225,10 230,10 235,10 176.251,10.058 162.171,10.395 139,10.592 190.068,10.617 167.658,11.002 181.882,11.309 139,11.555 145.692,12.047 195.174,12.192 186.182,12.37 139,12.548 160.825,12.554 166.845,12.655 178.427,12.859 223.995,13.062 164.788,13.138 173.038,13.335 226.687,13.722 233.025,14.331 235.975,14.331 181.864,14.554 185.674,14.554 178.402,14.662 190.195,14.681 20,15 29.964,15 40,15 50,15 59.934,15 90,15 100.133,15 115,15 120,15 125,15 130,15 175,15 195,15 210,15 170.071,15.145 166.947,15.173 155.466,15.373 153.637,15.449 233.025,15.669 235.975,15.669 139,15.748 163.678,15.773 72,16 76,16 227.272,16.389 229.38,16.389 207.714,16.542 213.302,16.542 188.74,16.592 183.888,16.618 179.596,16.669 173.144,16.694 139,17.196 213.302,17.481 207.714,17.507 190.924,17.964 156.177,18.04 157.93,18.04 186.124,18.04 181.679,18.091 177.234,18.142 172.839,18.218 231.742,18.269 194.81,18.497 147.712,18.644 150.945,18.652 139,18.746 167.005,18.999 170.63,19.056 120,20 125,20 130,20 149.598,20 152.926,19.996 160.139,20 180,20 185,20 190,20 225,20 230,20 158.209,20.021 194.531,20.758 208.933,20.758 176.116,21.418 169.24,21.463 148.329,21.494 139,21.514 210.381,21.514 152.316,21.545 182.136,21.774 72,22 76,22 233.025,22.331 235.975,22.331 202.1,22.485 206.698,22.688 161.232,22.953 185.768,23.095 170.688,23.114 174.617,23.128 156.108,23.139 139,23.175 151.901,23.165 163.408,23.4 192.829,23.4 197.579,23.476 233.025,23.669 235.975,23.669 146.754,23.908 202.1,24.187 181.272,24.746 139,24.765 195.217,24.924 125,25 130,25 150,25 154.976,25 185,25 200.424,25 205,25 210,25 215,25 220,25 225,25 230,25 235,25 20,25.025 30,25.025 190.061,25.025 173.398,25.66 146.144,25.732 164.153,26.092 177.97,26.194 207.536,26.397 217.315,26.397 202.126,26.422 212.413,26.422 183.177,26.524 187.571,26.524 192.753,26.524 197.935,26.524 166.827,26.873 158.438,27.028 139,27.661 203.878,28.099 143.248,28.124 161.257,28.149 147.236,28.2 139,28.445 150,28.445 154.976,28.445 221.557,28.48 176.395,28.683 152.392,28.886 167.226,28.886 55,29.24 60,29.24 65,29.24 70,29.24 75.712,29.24 80,29.24 85,29.24 90,29.24 95,29.24 100,29.24 105,29.24 110,29.24 115,29.24 120,29.24 180.637,29.242 144.747,29.267 207.155,29.369 139,29.388 183.861,29.496 224.986,29.699 45,30 50,30 125,30 130,30 135,30 190,30 194.958,30 210,30 230,30 235,30 162.629,30.156 158.692,30.207 148.43,30.258 169.918,30.359 152.549,30.447 165.042,30.715 187.267,30.766 146.779,31.451 167.658,31.528 180.002,32.264 233.025,32.331 235.975,32.331 150.083,32.403 130,32.575 135,32.575 226.027,32.975 148.532,33.077 184.6,33.128 155.136,33.382 207.714,33.586 213.302,33.586 233.025,33.669 235.975,33.669 152.549,33.854 48,34.118 53.042,34.118 229.456,34.169 188.689,34.195 111.836,34.493 213.302,34.526 207.714,34.551 151.901,34.652 150.132,34.855 58.956,34.907 154.678,34.982 30,35 40,35 45,35 50,35 180,35 195,35 210,35 225,35 56.619,35.109 171.45,35.535 183.609,35.769 153.18,35.922 192.372,35.998 165.804,36.049 162.603,36.084 159.766,36.113 168.877,36.201 151.605,36.252 97.358,36.474 72.534,36.5 74.577,36.5 76.783,36.5 78.825,36.5 80.868,36.5 83.133,36.5 85.175,36.5 87.218,36.5 89.424,36.5 91.467,36.5 92.534,36.5 94.577,36.5 98.825,36.5 100.868,36.5 103.133,36.5 105.175,36.5 107.218,36.5 109.424,36.5 111.467,36.5 112.534,36.5 114.577,36.5 116.783,36.5 120.868,36.5 123.133,36.5 125.175,36.5 126.197,36.5 127.218,36.5 129.424,36.5 130.445,36.5 132.555,36.608 46.144,36.737 46.878,37.09 56.619,37.09 230.624,37.319 157.599,37.573 154.932,37.598 159.715,37.598 162.527,37.598 165.829,37.598 168.09,37.596 189.172,37.649 152.85,37.674 130.269,38.208 113.736,38.436 154.17,38.944 156.958,38.97 157.658,38.97 177.658,38.97 178.358,38.97 156.228,39.005 186.657,39.046 56.619,39.071 174.396,39.089 194.048,39.554 54.283,39.63 200.271,39.757 132.403,39.783 196.411,39.808 207.637,39.808 214.495,39.833 72.944,39.96 35,40 40,40 45,40 50,40 180,40 220,40 225,40 230,40 176.408,40.111 233.025,40.331 235.975,40.331 155.898,40.646 145.865,40.805 90.267,40.926 126.005,40.951 156.958,41.202 157.658,41.202 177.658,41.202 178.358,41.202 194.887,41.205 211.574,41.23 191.381,41.281 204.208,41.281 158.408,41.611 158.908,41.611 160.408,41.611 161.908,41.611 163.408,41.611 164.908,41.611 166.408,41.611 167.908,41.611 169.408,41.611 170.908,41.611 172.408,41.611 175.908,41.611 176.908,41.611 233.025,41.669 235.975,41.669 74.244,41.732 189.705,41.865 217.569,41.992 184.508,42.104 197.782,42.196 201.008,42.297 203.65,42.577 42.339,43.039 47.399,43.039 91.559,43.039 221.404,43.542 177.803,43.613 172.687,44.71 57.027,44.871 203.878,44.863 54.035,44.921 55.051,44.924 30,45 35,45 185,45 190,45 195,45 200,45 210,45 215,45 220,45 225,45 230,45 235,45 156.38,45.056 154.413,45.117 58.937,45.419 59.9,45.459 62.876,45.459 183.217,45.579 168.58,45.644 206.926,45.752 59.93,46.296 180.028,46.31 177.803,46.341 93.82,46.463 112.827,46.457 62.003,46.721 56.067,46.765 108.908,47.174 54.035,47.22 175.405,47.326 192.626,47.606 29.964,47.631 30.98,47.631 168.09,48.265 226.484,48.419 89.172,48.52 207.536,48.571 180.383,48.85 182.263,48.85 160.655,48.92 111.524,49.104 29.964,49.13 30.98,49.13 165.329,49.251 159.301,49.555 194.074,49.663 25,50 35,50 178.173,50 185.031,50 190,50 225,50 230,50 57.472,50.32 58.382,50.32 59.292,50.32 60.202,50.32 61.112,50.32 233.025,50.331 235.975,50.331 207.714,50.493 213.302,50.493 29.964,50.59 30.98,50.59 51.457,51.098 131.895,51.098 37.788,51.225 38.346,51.225 38.931,51.225 40.078,51.225 40.637,51.225 41.221,51.225 42.339,51.228 75.486,51.225 76.044,51.225 76.629,51.225 77.785,51.219 78.344,51.219 78.928,51.219 57.472,51.23 58.382,51.23 59.292,51.23 60.202,51.23 61.112,51.23 74.343,51.253 213.302,51.433 207.714,51.458 51.457,51.657 233.025,51.669 235.975,51.669 229.608,51.822 37.788,51.886 38.346,51.886 38.931,51.886 40.078,51.886 40.637,51.886 41.221,51.886 75.486,51.886 76.044,51.886 76.629,51.886 77.785,51.879 78.344,51.879 78.928,51.879 227.78,51.879 89.172,52 23.665,52.048 57.472,52.14 58.382,52.14 60.202,52.14 61.112,52.14 51.457,52.241 183.914,52.381 182.441,52.457 63.814,52.555 64.499,52.555 65.084,52.555 65.674,52.555 66.252,52.555 194.734,52.787 75.486,53.029 76.044,53.029 76.629,53.029 77.785,53.029 78.344,53.029 78.928,53.029 37.788,53.052 38.346,53.052 38.931,53.052 40.078,53.054 40.637,53.054 41.221,53.054 57.472,53.05 58.382,53.05 59.292,53.05 60.202,53.05 61.112,53.05 52.956,53.333 74.343,53.686 75.486,53.689 76.044,53.689 76.629,53.689 77.785,53.689 78.344,53.689 78.928,53.689 178.961,53.676 37.788,53.713 38.346,53.713 38.931,53.713 40.078,53.714 40.637,53.714 41.221,53.714 42.339,53.74 57.472,53.96 58.382,53.96 59.292,53.96 60.202,53.96 61.112,53.96 131.895,54.678 20,55 25,55 35,55 185.031,55 190,55 195,55 210,55 215,55 225,55 230,55 122.954,56.343 111.879,56.496 120.617,56.613 178.402,56.877 55.997,56.966 182.466,56.978 183.965,57.029 119.322,57.105 53.857,57.162 95.141,57.182 93.289,57.24 198.951,57.309 102.989,57.334 162.908,57.588 166.743,57.588 22.7,57.613 121.684,57.639 171.366,57.664 175.405,57.664 87.288,57.734 61.578,57.959 59.038,57.984 101.212,57.994 201.795,57.994 63.763,58.202 113.708,58.299 233.025,58.331 235.975,58.331 120.744,58.579 58.022,58.644 60.308,58.858 165.499,58.934 104.717,58.96 54.746,59.026 53.73,59.051 97.224,59.264 180.485,59.29 95.395,59.366 123.335,59.366 162.883,59.468 233.025,59.669 235.975,59.669 160.216,59.823 61.592,59.864 62.594,59.864 177.142,59.925 168.344,59.95 172.786,59.95 85.041,60 90,60 135,60 150,60 185.031,60 195,60 200,60 205,60 210,60 215,60 220,60 225,60 230,60 103.269,60.051 145,60.051 181.831,60.636 118.61,60.865 54.729,60.971 65.084,60.971 170,60.971 175.02,60.971 55.725,61.119 57.036,61.119 165.092,61.271 94.463,61.366 162.857,61.423 99.611,61.652 97.782,61.728 55.725,61.936 57.036,61.936 178.046,61.931 13.299,62.083 203.853,62.084 60,62.265 82.288,62.265 132,62.265 123.335,62.363 159.809,62.439 110.305,63.024 157.498,63.1 119.779,63.392 163.086,63.405 106.52,63.455 178.783,63.532 207.764,63.735 161.079,64.065 182.466,64.065 124.783,64.09 77.793,64.116 16.586,64.297 112.057,64.598 107.79,64.675 104.158,64.852 15,65 20,65 45,65 50,65 55,65 60,65 80,65 85,65 90,65 95,65 130,65 135,65 140,65 145,65 150,65 155,65 165,65 170,65 175,65 185.031,65 190,65 195,65 210,65 225,65 230,65 235,65 22.7,65.358 105.707,66.402 207.714,67.52 213.302,67.52 156.045,68.256 159.855,68.256 163.665,68.256 176.045,68.256 179.855,68.256 183.665,68.256 213.302,68.46 207.714,68.485 20,69.999 61.041,69.999 62.844,69.999 64.724,69.999 66.146,69.999 67.645,69.999 68.94,69.999 108.041,69.999 109.844,69.999 111.724,69.999 113.146,69.999 114.645,69.999 115.94,69.999 140,69.999 150,69.999 170,69.999 190,69.999 210,69.999 25,70.001 30,70.001 35,70.001 40,70.001 45,70.001 61.936,70 71.06,70.001 72.356,70.001 73.854,70.001 75.277,70.001 77.156,70.001 78.065,70 78.96,70.001 95,70.001 108.936,70 118.06,70.001 119.356,70.001 120.854,70.001 122.277,70.001 124.156,70.001 125.065,70 125.96,70.001 145,70.001 195,70.001 225,70.001 230,70.001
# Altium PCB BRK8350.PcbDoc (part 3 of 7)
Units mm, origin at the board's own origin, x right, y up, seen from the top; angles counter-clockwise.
Board outline 240 x 150 mm, 8 copper layers (L1-TOP, L2-GND, L3-PWR, L4-SIG, L5-SIG, L6-PWR, L7-GND, L8-BOT), stack 1.465 mm thick; 277 components, 542 nets, 1814 pads, 2338 vias.

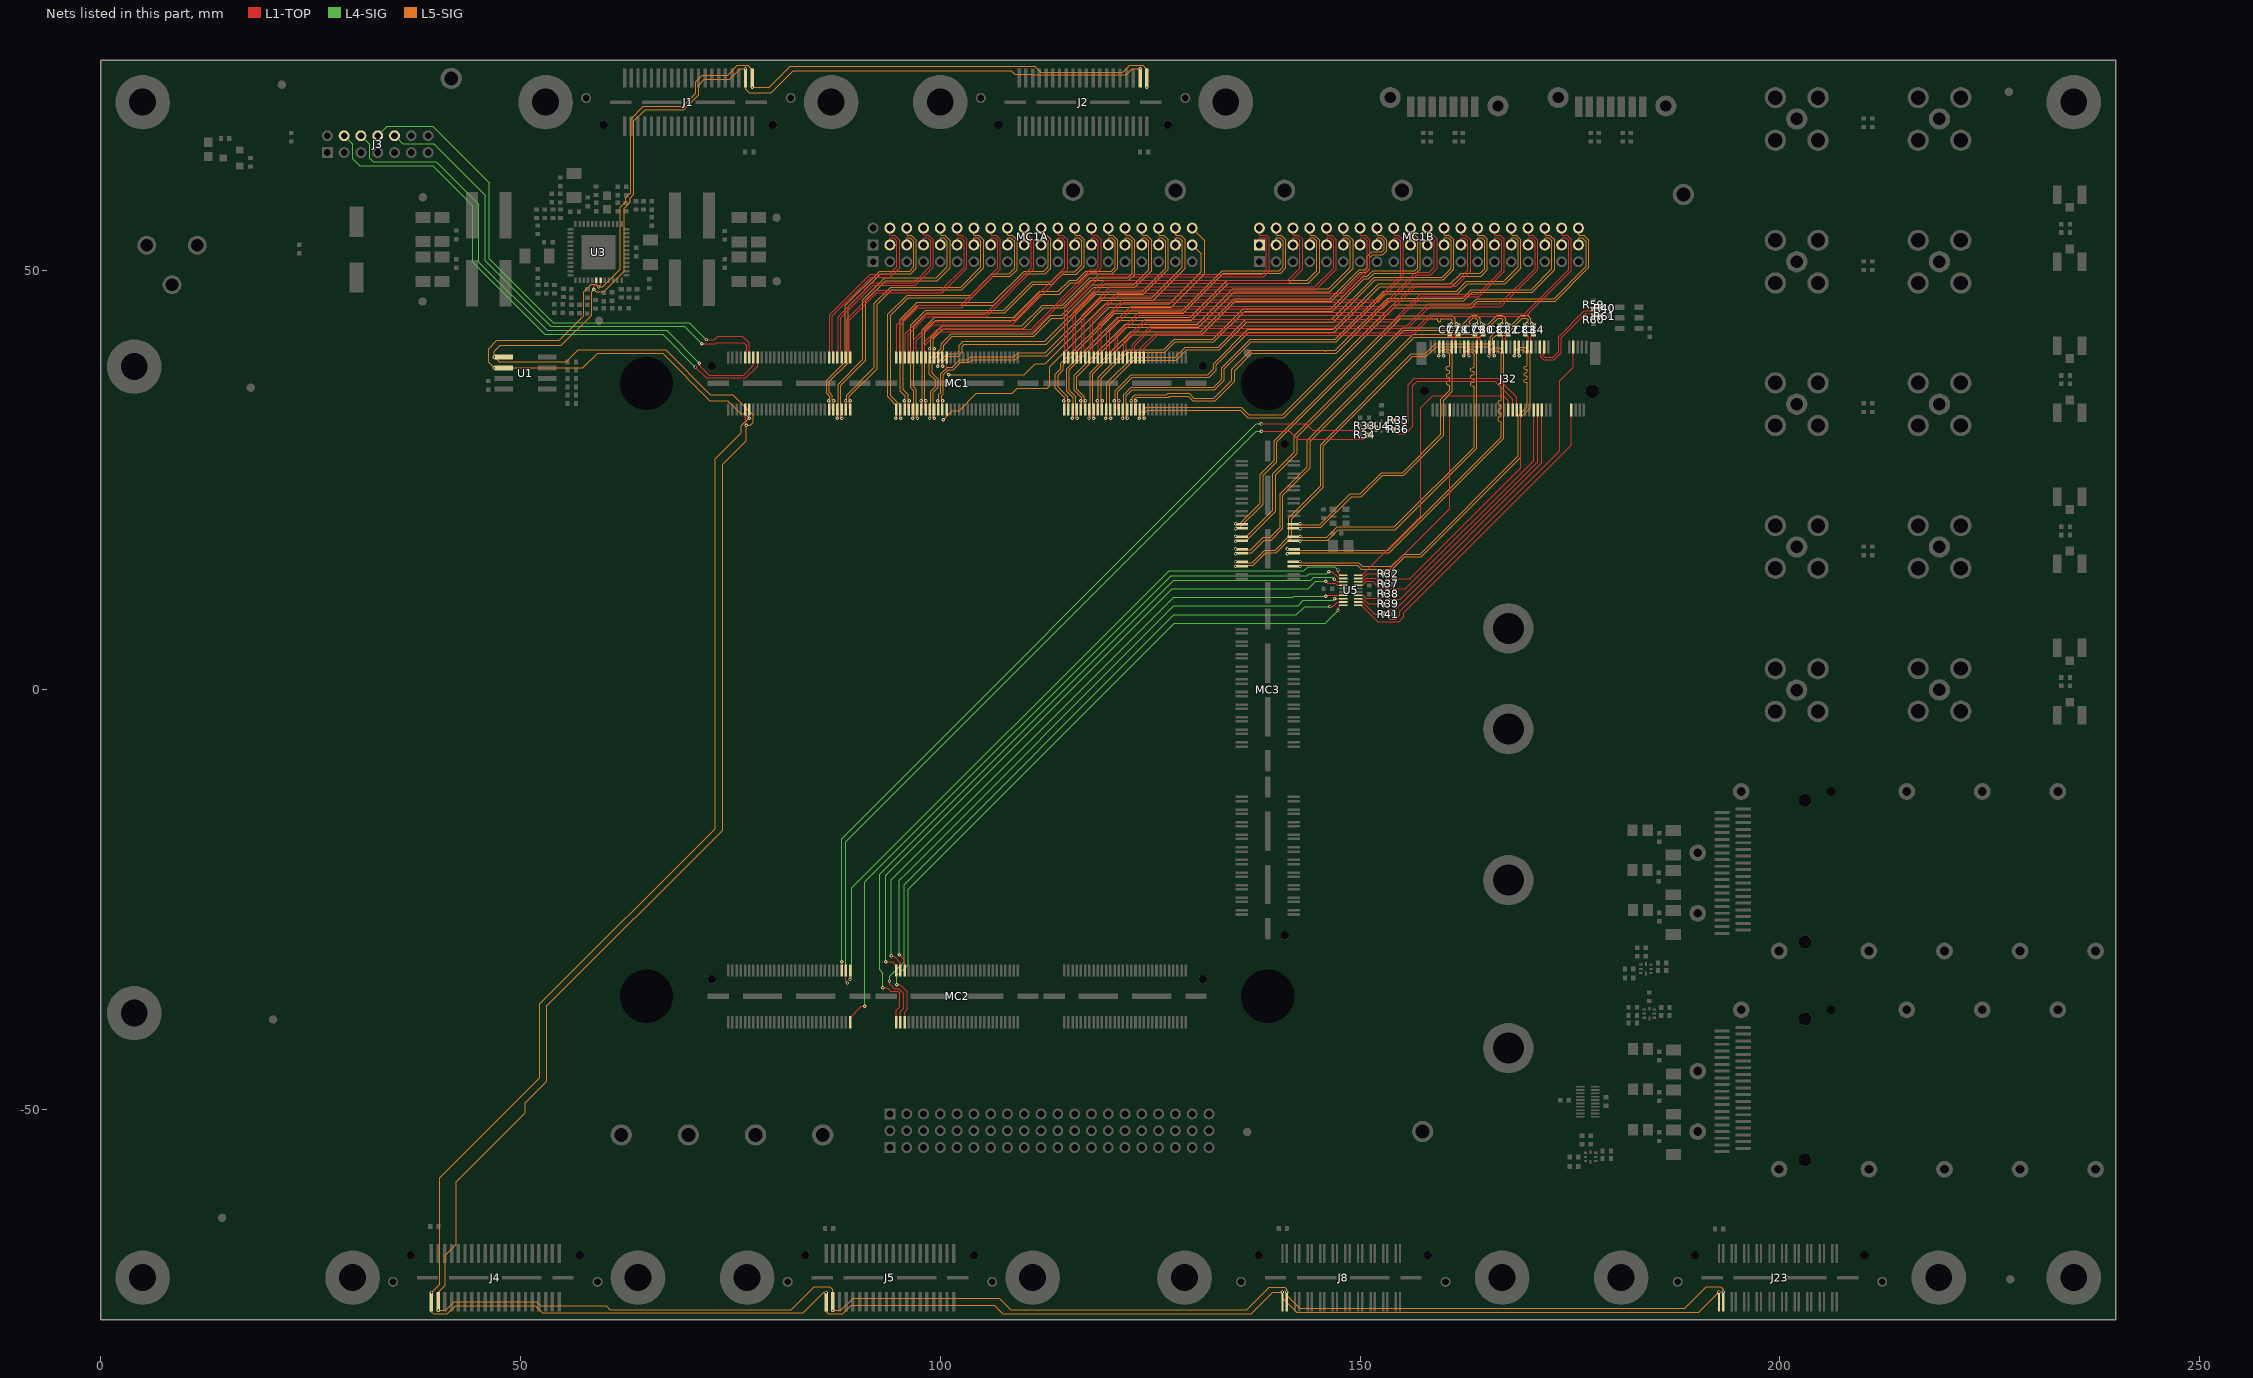
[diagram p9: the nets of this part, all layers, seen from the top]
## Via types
v1: diameter 0.406, hole 0.203, L1-TOP to L8-BOT, tented both sides, 2338 vias

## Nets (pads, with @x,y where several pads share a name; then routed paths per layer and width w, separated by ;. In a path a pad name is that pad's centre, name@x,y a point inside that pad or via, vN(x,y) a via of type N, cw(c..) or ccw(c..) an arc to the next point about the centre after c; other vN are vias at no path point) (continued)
I2C_SCL: J1.1 J2.1 J4.1 J5.1 J8.1 J23.1 MC1.12 U1.6 U3.43 | length 434.1
  L1-TOP w0.114: v1(77.25,32.369) MC1.12@77.25,33.41
  L1-TOP w0.127: v1(59.318,47.987) 59.542,48.211 U3.43@59.542,48.79
  L5-SIG w0.127: v1(124.603,71.764) 124.603,73.935 124.135,74.403 122.547,74.403 121.709,73.565 111.967,73.565 111.256,74.276 82.16,74.276 79.648,71.764 v1(77.603,71.764) 77.603,73.856 77.081,74.377 75.837,74.377 74.694,73.234 71.646,73.234 70.858,72.447 70.858,71.037 69.309,69.488 64.648,69.488 63.111,67.951 63.111,59.226 62.515,58.629 62.515,58.121 61.88,57.486 61.88,50.094 59.772,47.987 v1(59.318,47.987) 58.975,48.33 58.438,48.33 57.511,47.403 57.511,44.571 54.596,41.656 47.201,41.656 46.203,40.658 46.203,39.036 v1(46.891,38.348) 57.441,38.348 59.182,40.088 66.922,40.088 72.542,34.468 74.703,34.468 76.251,32.92 76.7,32.92 v1(77.25,32.369) 77.175,32.369 76.276,31.471 76.276,30.632 73.177,27.534 73.177,-16.535 52.306,-37.406 52.306,-46.22 40.411,-58.115 40.411,-70.814 39.461,-71.764 v1(39.398,-71.764) 39.398,-74.057 39.665,-74.324 41.303,-74.324 42.278,-73.349 51.755,-73.349 52.588,-74.182 83.703,-74.182 86.121,-71.764 v1(86.398,-71.764) 86.398,-74.067 86.65,-74.319 88.372,-74.319 89.408,-73.283 106.418,-73.283 107.429,-74.294 137.02,-74.294 139.596,-71.718 v1(140.737,-71.718) 140.737,-72.387 142.448,-74.098 190.357,-74.098 v1(192.737,-71.718)
I2C_SDA: J1.3 J2.3 J4.3 J5.3 J8.3 J23.3 MC1.10 U1.5 U3.42 | length 432.6
  L1-TOP w0.127: v1(58.734,47.707) 58.734,48.029 59.042,48.337 U3.42@59.042,48.79 ; MC1.10@76.75,33.41 76.75,32.47 76.81,32.41 76.81,32.014 76.886,31.938 v1(76.886,31.496) ; J2.3@123.803,72.865 v1(123.803,73.966)
  L5-SIG w0.127: v1(123.803,73.966) 122.873,73.966 122.166,73.26 110.978,73.26 110.902,73.336 108.882,73.336 108.476,73.742 82.504,73.742 79.875,71.114 77.221,71.114 76.803,71.532 v1(76.803,73.966) 76.162,73.966 74.897,72.701 71.913,72.701 71.239,72.028 71.239,70.91 69.423,69.094 64.851,69.094 63.518,67.761 63.518,59.049 63.048,58.579 63.048,58.058 62.375,57.385 62.375,49.841 59.936,47.403 59.038,47.403 v1(58.734,47.707) 58.463,47.437 58.463,44.649 54.86,41.046 47.582,41.046 46.891,40.356 v1(46.891,39.643) 47.463,39.071 55.423,39.071 56.864,40.513 67.274,40.513 72.612,35.176 75.263,35.176 77.749,32.69 77.749,31.852 77.394,31.496 v1(76.886,31.496) 76.886,29.693 74.066,26.873 74.066,-16.688 53.111,-37.643 53.111,-46.634 50.564,-49.181 50.564,-50.376 42.339,-58.601 42.339,-66.019 41.021,-67.336 41.021,-70.928 40.198,-71.752 40.198,-73.87 41.091,-73.87 42.113,-72.847 51.853,-72.847 52.342,-73.336 60.19,-73.336 60.648,-73.793 82.263,-73.793 84.968,-71.088 86.848,-71.088 87.196,-71.436 v1(87.196,-73.887) 87.196,-73.91 88.166,-73.91 89.642,-72.435 107.015,-72.435 108.405,-73.824 136.474,-73.824 139.174,-71.124 140.998,-71.124 141.263,-71.389 v1(141.263,-71.718) 141.263,-72.095 142.822,-73.654 188.676,-73.654 191.254,-71.076 192.931,-71.076 193.263,-71.407 v1(193.263,-71.718)
  other v1: 40.196,-73.86
JTAG_TCK: J3.6 MC1.13 | length 65.1
  L1-TOP w0.114: v1(71.298,38.906) 71.298,38.673 72.481,37.49 76.599,37.49 77.75,38.642 MC1.13@77.75,39.59
  L4-SIG w0.127: J3.6@31,66 32.022,64.978 32.022,63.328 32.441,62.909 39.959,62.909 45.052,57.817 45.052,50.959 53.205,42.805 67.399,42.805 v1(71.298,38.906)
JTAG_TDI: J3.10 MC1.9 | length 58.5
  L1-TOP w0.127: v1(71.603,41.224) 73.228,41.224 73.33,41.326 76.606,41.326 76.962,40.97 76.962,40.446 76.75,40.235 MC1.9@76.75,39.59
  L4-SIG w0.127: J3.10@35,66 35.97,65.03 39.693,65.03 45.801,58.922 45.801,51.086 53.586,43.301 69.526,43.301 v1(71.603,41.224)
JTAG_TDO: J3.8 MC1.11 | length 62.8
  L1-TOP w0.127: v1(72.136,41.732) 73.101,41.732 73.508,42.139 76.429,42.139 77.25,41.317 MC1.11@77.25,39.59
  L4-SIG w0.127: J3.8@33,66 34.126,67.126 39.566,67.126 46.309,60.382 46.309,51.327 53.891,43.745 70.123,43.745 v1(72.136,41.732)
JTAG_TMS: J3.4 MC1.15 | length 67.8
  L1-TOP w0.114: v1(70.841,38.456) 72.136,37.16 76.86,37.16 78.25,38.551 MC1.15@78.25,39.59
  L4-SIG w0.127: J3.4@29,66 30.028,64.972 30.028,63.252 30.879,62.401 39.578,62.401 44.305,57.674 44.305,50.918 52.863,42.361 66.935,42.361 v1(70.841,38.456)
M2_ALERT_B: MC2.62 U5.3 | length 89.8
  L1-TOP w0.127: v1(93.167,-35.484) 93.701,-35.484 94.107,-35.89 94.945,-35.89 95.174,-36.119 95.174,-37.758 94.75,-38.182 MC2.62@94.75,-39.59 ; v1(146.939,13.183) 147.253,12.869 U5.3@147.998,12.869
  L4-SIG w0.127: v1(93.167,-35.484) 93.167,-33.757 92.761,-33.35 92.761,-21.932 127.78,13.087 144.137,13.087 144.493,13.443 146.679,13.443 v1(146.939,13.183)
M2_ALERT_B_3V3: J32.44 R37.1 U5.18 | length 32.4
  L1-TOP w0.127: U5.18@149.798,12.869 150.269,12.869 150.716,13.316 152.229,13.316 152.908,12.637 153.511,13.24 155.926,13.24 169.158,26.472 J32.44@169.158,33.311
M2_CLKREQ_B: MC2.63 U5.7 | length 79.2
  L1-TOP w0.114: v1(94.183,-31.674) 94.437,-31.674 95.25,-32.487 MC2.63@95.25,-33.41
  L1-TOP w0.127: v1(145.898,11.151) 146.016,11.269 U5.7@147.998,11.269
  L4-SIG w0.127: v1(94.183,-31.674) 94.183,-22.592 127.831,11.055 142.029,11.055 142.125,11.151 v1(145.898,11.151)
M2_CLKREQ_B_3V3: J32.52 R38.1 U5.14 | length 34.9
  L1-TOP w0.127: U5.14@149.798,11.269 150.401,11.269 150.538,11.131 150.538,11.03 150.665,10.903 152.375,10.903 152.908,11.436 153.518,10.827 154.805,10.827 171.158,27.179 J32.52@171.158,33.311
M2_DEVSLP: MC2.59 U5.1 | length 87
  L1-TOP w0.114: v1(89.25,-34.449) MC2.59@89.25,-33.41
  L1-TOP w0.127: v1(147.371,14.275) 147.371,13.911 147.613,13.669 U5.1@147.998,13.669
  L4-SIG w0.127: v1(89.25,-34.449) 89.484,-34.215 89.484,-23.583 127.246,14.179 143.299,14.179 143.807,14.687 146.958,14.687 v1(147.371,14.275)
M2_DEVSLP_3V3: J32.38 U5.20 | length 35.7
  L1-TOP w0.127: U5.20@149.798,13.669 150.197,13.669 157.218,20.69 157.218,33.61 158.666,35.058 167.048,35.058 167.658,34.449 J32.38@167.658,33.311
M2_LED_1_B: MC2.60 U5.2 | length 89.7
  L1-TOP w0.114: MC2.60@89.25,-39.02 90.602,-37.668 v1(91.008,-37.668)
  L1-TOP w0.127: v1(146.253,14.072) 146.711,14.072 147.513,13.269 U5.2@147.998,13.269
  L4-SIG w0.127: v1(91.008,-37.668) 91.008,-22.872 127.5,13.621 143.68,13.621 143.883,13.824 146.006,13.824 v1(146.253,14.072)
M2_LED_1_B_3V3: J32.10 R32.1 U5.19 | length 26
  L1-TOP w0.127: U5.19@149.798,13.269 150.278,13.269 150.846,13.837 152.908,13.837 160.658,21.586 J32.10@160.658,33.311
M2_PEDET: MC2.64 U5.9 | length 84.6
  L1-TOP w0.127: v1(93.955,-34.696) 93.955,-35.052 94.488,-35.585 95.072,-35.585 95.656,-36.17 95.656,-37.922 95.25,-38.328 MC2.64@95.25,-39.59 ; v1(146.406,9.931) 146.768,9.931 147.305,10.469 U5.9@147.998,10.469
  L4-SIG w0.127: v1(93.955,-34.696) 93.955,-34.112 95.682,-32.385 95.682,-23.176 127.78,8.922 142.385,8.922 143.395,9.931 v1(146.406,9.931)
M2_PEDET_3V3: J32.69 R41.1 U5.12 | length 46.5
  L1-TOP w0.127: U5.12@149.798,10.469 150.286,10.469 151.719,9.037 R41.1@152.858,9.037 152.938,9.037 153.535,8.439 154.221,8.439 154.707,8.925 154.707,9.393 173.805,28.49 173.805,36.802 175.408,38.405 J32.69@175.408,40.861
M2_PER_N0: J32.41 MC3.35 | length 49
  L1-TOP w0.107: v1(168.349,39.783) 168.459,39.893 ccw(c168.366,39.986) 168.498,39.986 168.498,40.644 ccw(c168.191,40.644) J32.41@168.408,40.861
  L5-SIG w0.107: v1(142.836,14.712) 142.964,14.84 149.678,14.84 150.132,14.387 153.853,14.387 155.327,15.86 157.287,15.86 169.154,27.727 169.154,32.502 170.238,33.586 170.238,40.189 169.588,40.839 168.933,40.839 168.498,40.404 168.498,40.048 cw(c168.216,40.048) v1@168.415,39.849 ; v1(168.349,39.783) v1@168.415,39.849
M2_PER_N1: J32.29 MC3.31 | length 45.5
  L1-TOP w0.107: v1(165.349,39.783) 165.459,39.893 ccw(c165.366,39.986) 165.498,39.986 165.498,40.644 ccw(c165.191,40.644) J32.29@165.408,40.861
  L5-SIG w0.107: v1(141.344,16.212) cw(c141.654,15.903) 141.654,16.34 153.496,16.34 167.122,29.966 167.122,40.188 166.586,40.724 165.856,40.724 165.498,40.365 165.498,40.062 cw(c165.182,40.062) 165.405,39.839 v1(165.349,39.783)
M2_PER_N2: J32.17 MC3.27 | length 40.3
  L1-TOP w0.107: v1(162.349,39.783) 162.459,39.893 ccw(c162.366,39.986) 162.498,39.986 162.498,40.644 ccw(c162.191,40.644) J32.17@162.408,40.861
  L5-SIG w0.107: v1(142.836,17.712) cw(c143.146,17.403) 143.146,17.84 146.131,17.84 147.392,19.101 154.199,19.101 163.888,28.79 163.888,40.116 163.413,40.592 162.86,40.592 162.498,40.23 162.498,40.037 cw(c162.243,40.037) 162.423,39.857 v1(162.349,39.783)
M2_PER_N3: J32.5 MC3.23 | length 35.5
  L1-TOP w0.107: v1(159.349,39.783) 159.459,39.893 ccw(c159.366,39.986) 159.498,39.986 159.498,40.644 ccw(c159.191,40.644) J32.5@159.408,40.861
  L5-SIG w0.107: v1(142.836,19.212) cw(c142.97,19.212) 142.97,19.346 145.311,19.346 148.978,23.012 150.145,23.012 152.695,25.563 155.183,25.563 159.951,30.331 159.951,34.503 160.993,35.544 160.993,40.163 160.581,40.575 159.838,40.575 159.498,40.234 159.498,40.037 cw(c159.243,40.037) 159.423,39.857 v1(159.349,39.783)
M2_PER_P0: J32.43 MC3.33 | length 49
  L1-TOP w0.107: J32.43@168.908,40.861 ccw(c169.125,40.644) 168.818,40.644 168.818,39.986 ccw(c168.95,39.986) 168.856,39.893 v1(168.966,39.783)
  L5-SIG w0.107: v1(142.836,15.288) 142.964,15.16 149.811,15.16 150.264,14.707 153.721,14.707 155.194,16.18 157.154,16.18 168.834,27.859 168.834,32.634 169.918,33.719 169.918,36.246 169.918,36.555 169.841,36.632 169.64,36.632 169.563,36.709 169.563,36.941 169.64,37.018 169.841,37.018 169.918,37.095 169.918,37.327 169.841,37.404 169.64,37.404 169.563,37.481 169.563,37.713 169.64,37.79 169.841,37.79 169.918,37.867 169.918,38.099 169.841,38.176 169.64,38.176 169.563,38.253 169.563,38.485 169.64,38.562 169.841,38.562 169.918,38.639 169.918,38.948 169.918,39.141 169.918,40.056 169.455,40.519 169.066,40.519 168.818,40.271 168.818,40.048 ccw(c169.1,40.048) v1@168.9,39.849 ; v1@168.9,39.849 v1(168.966,39.783)
M2_PER_P1: J32.31 MC3.29 | length 45.3
  L1-TOP w0.107: J32.31@165.908,40.861 ccw(c166.125,40.644) 165.818,40.644 165.818,39.986 ccw(c165.95,39.986) 165.856,39.893 v1(165.966,39.783)
  L5-SIG w0.107: v1(141.344,16.789) ccw(c141.654,17.098) 141.654,16.66 153.363,16.66 166.802,30.099 166.802,31.775 166.802,31.922 166.704,32.019 166.541,32.019 166.443,32.117 166.443,32.409 166.541,32.507 166.704,32.507 166.802,32.604 166.802,32.897 166.704,32.995 166.541,32.995 166.443,33.092 166.443,33.385 166.541,33.482 166.704,33.482 166.802,33.58 166.802,33.872 166.704,33.97 166.541,33.97 166.443,34.067 166.443,34.36 166.541,34.458 166.704,34.458 166.802,34.555 166.802,34.849 166.802,40.056 166.454,40.404 165.989,40.404 165.818,40.233 165.818,40.062 ccw(c166.134,40.062) 165.91,39.839 v1(165.966,39.783)
M2_PER_P2: J32.19 MC3.25 | length 40.3
  L1-TOP w0.107: J32.19@162.908,40.861 ccw(c163.125,40.644) 162.818,40.644 162.818,39.986 ccw(c162.95,39.986) 162.856,39.893 v1(162.966,39.783)
  L5-SIG w0.107: v1(142.836,18.288) ccw(c143.146,18.598) 143.146,18.16 145.999,18.16 147.259,19.421 154.066,19.421 163.568,28.923 163.568,35.789 163.568,36.113 163.481,36.2 163.288,36.2 163.201,36.287 163.201,36.55 163.288,36.637 163.481,36.637 163.568,36.724 163.568,36.986 163.481,37.074 163.288,37.074 163.201,37.161 163.201,37.423 163.288,37.511 163.481,37.511 163.568,37.598 163.568,37.86 163.481,37.948 163.288,37.948 163.201,38.035 163.201,38.297 163.288,38.384 163.481,38.384 163.568,38.472 163.568,38.821 163.568,39.04 163.568,39.983 163.28,40.272 162.992,40.272 162.818,40.097 162.818,40.037 ccw(c163.072,40.037) 162.892,39.857 v1(162.966,39.783)
M2_PER_P3: J32.7 MC3.21 | length 35.4
  L1-TOP w0.107: J32.7@159.908,40.861 ccw(c160.125,40.644) 159.818,40.644 159.818,39.986 ccw(c159.95,39.986) 159.856,39.893 v1(159.966,39.783)
  L5-SIG w0.107: v1(142.836,19.788) ccw(c142.959,19.788) 142.959,19.666 145.179,19.666 148.845,23.332 150.012,23.332 152.563,25.883 155.05,25.883 159.631,30.464 159.631,34.635 160.673,35.677 160.673,35.992 160.673,36.265 160.585,36.352 160.429,36.352 160.342,36.44 160.342,36.702 160.429,36.789 160.585,36.789 160.673,36.877 160.673,37.139 160.585,37.226 160.432,37.226 160.345,37.314 160.345,37.576 160.432,37.663 160.585,37.663 160.673,37.75 160.673,38.013 160.585,38.1 160.351,38.1 160.263,38.187 160.263,38.45 160.351,38.537 160.585,38.537 160.673,38.624 160.673,38.974 160.673,39.192 160.673,40.03 160.448,40.255 159.971,40.255 159.818,40.101 159.818,40.037 ccw(c160.072,40.037) 159.892,39.857 v1(159.966,39.783)
M2_PERST_B: MC2.61 U5.4 | length 81.5
  L1-TOP w0.114: v1(93.497,-32.36) 94.285,-32.36 94.75,-32.825 MC2.61@94.75,-33.41
  L1-TOP w0.127: v1(145.898,12.929) 146.152,12.675 147.066,12.675 147.272,12.469 U5.4@147.998,12.469
  L4-SIG w0.127: v1(93.497,-32.36) 93.497,-22.059 127.616,12.06 143.852,12.06 144.721,12.929 v1(145.898,12.929)
M2_PERST_B_3V3: J32.50 U5.17 | length 33.8
  L1-TOP w0.127: U5.17@149.798,12.469 150.276,12.469 150.538,12.732 150.538,12.757 150.71,12.929 151.535,12.929 152.443,12.02 155.364,12.02 170.658,27.314 J32.50@170.658,33.311
M2_PET_N0: C83.1 MC3.36 | length 52.7
  L5-SIG w0.107: v1(135.164,14.712) cw(c135.474,14.403) 135.474,14.84 137.289,14.84 138.787,16.338 140.018,16.338 141.841,18.162 141.841,20.395 145.608,24.161 145.608,29.087 156.25,39.729 157.907,39.729 159.06,40.882 165.029,40.882 ; 165.055,40.882 165.35,40.882 165.804,41.336 165.804,41.874 166.186,42.257 167.312,42.257 167.956,42.9 168.076,43.02 cw(c168.147,42.949) 168.218,43.02 168.327,42.911 ccw(c168.398,42.982) 168.469,42.911 168.564,43.005 ccw(c168.493,43.077) 168.564,43.148 168.455,43.257 cw(c168.526,43.328) 168.455,43.399 168.502,43.447 169.334,44.278 169.81,44.278 170.001,44.087 170.001,43.912 cw(c169.545,43.912) v1(169.868,43.59)
M2_PET_N0_C: C83.2 J32.47 | length 1.7
  L1-TOP w0.107: C83.2@169.664,42.416 170.001,42.079 170.001,40.954 J32.47@169.908,40.861
M2_PET_N1: C81.1 MC3.32 | length 48.8
  L5-SIG w0.107: v1(135.164,16.212) cw(c135.301,16.212) 135.301,16.349 137.082,16.349 138.58,17.847 139.412,17.847 140.8,19.235 140.8,23.212 144.033,26.445 144.033,29.606 156.455,42.028 164.188,42.028 165.026,42.866 165.155,42.994 cw(c165.226,42.923) 165.297,42.994 165.406,42.885 ccw(c165.477,42.956) 165.548,42.885 165.643,42.98 ccw(c165.572,43.051) 165.643,43.122 165.534,43.231 cw(c165.605,43.303) 165.534,43.374 165.581,43.421 166.439,44.278 166.817,44.278 166.998,44.098 166.998,43.92 cw(c166.531,43.92) v1(166.861,43.59)
M2_PET_N1_C: C81.2 J32.35 | length 1.7
  L1-TOP w0.107: C81.2@166.658,42.416 166.998,42.076 166.998,40.951 J32.35@166.908,40.861
M2_PET_N2: C79.1 MC3.28 | length 44.7
  L5-SIG w0.107: v1(135.164,17.712) cw(c135.299,17.712) 135.299,17.847 136.516,17.847 139.944,21.275 139.944,25.607 142.494,28.157 142.494,30.124 155.185,42.815 161.953,42.815 162.425,43.288 162.442,43.305 162.608,43.471 cw(c162.679,43.4) 162.751,43.471 162.86,43.361 ccw(c162.931,43.433) 163.002,43.361 163.097,43.456 ccw(c163.026,43.527) 163.097,43.599 162.988,43.708 cw(c163.059,43.779) 162.988,43.85 163.035,43.897 163.287,44.15 ; v1(163.873,43.59) ccw(c163.554,43.909) 164.005,43.909 164.005,44.045 163.721,44.329 163.467,44.329 163.288,44.151 ; 163.287,44.15 cw(c163.721,43.716) 163.288,44.151 ; 163.287,44.15 163.288,44.151
M2_PET_N2_C: C79.2 J32.23 | length 1.7
  L1-TOP w0.107: C79.2@163.67,42.416 164.005,42.081 164.005,40.958 J32.23@163.908,40.861
M2_PET_N3: C77.1 MC3.24 | length 40.7
  L5-SIG w0.107: v1(135.164,19.212) cw(c135.298,19.212) 135.298,19.346 135.678,19.346 138.438,22.106 138.438,25.542 140.089,27.193 140.089,29.535 154.781,44.228 158.971,44.228 159.155,44.228 cw(c159.155,44.127) 159.255,44.127 159.255,43.973 ccw(c159.356,43.973) 159.356,43.872 159.49,43.872 ccw(c159.49,43.973) 159.591,43.973 159.591,44.127 cw(c159.691,44.127) 159.691,44.228 159.758,44.228 160.821,44.228 160.998,44.051 160.998,43.872 cw(c160.647,43.872) 160.895,43.624 v1(160.861,43.59)
M2_PET_N3_C: C77.2 J32.11 | length 1.7
  L1-TOP w0.107: C77.2@160.658,42.416 160.998,42.076 160.998,40.951 J32.11@160.908,40.861
M2_PET_P0: C84.1 MC3.34 | length 52.7
  L5-SIG w0.107: v1(135.164,15.288) ccw(c135.474,15.598) 135.474,15.16 137.157,15.16 138.655,16.658 139.885,16.658 141.521,18.294 141.521,20.527 145.288,24.294 145.288,29.219 156.117,40.049 157.774,40.049 158.928,41.202 165.217,41.202 165.484,41.468 165.484,42.007 166.054,42.577 167.18,42.577 169.202,44.598 169.943,44.598 170.321,44.22 170.321,43.912 ccw(c170.777,43.912) v1(170.455,43.59)
M2_PET_P0_C: C84.2 J32.49 | length 1.7
  L1-TOP w0.107: J32.49@170.408,40.861 170.321,40.948 170.321,42.079 C84.2@170.658,42.416
M2_PET_P1: C82.1 MC3.30 | length 48.8
  L5-SIG w0.107: v1(135.164,16.789) ccw(c135.284,16.789) 135.284,16.669 136.949,16.669 138.448,18.167 139.279,18.167 140.48,19.368 140.48,23.344 143.713,26.578 143.713,29.739 156.322,42.348 164.056,42.348 166.306,44.598 166.95,44.598 167.318,44.231 167.318,43.92 ccw(c167.785,43.92) v1(167.455,43.59)
M2_PET_P1_C: C82.2 J32.37 | length 1.7
  L1-TOP w0.107: J32.37@167.408,40.861 167.318,40.951 167.318,42.076 C82.2@167.658,42.416
M2_PET_P2: C80.1 MC3.26 | length 44.7
  L5-SIG w0.107: v1(135.164,18.288) ccw(c135.286,18.288) 135.286,18.167 136.383,18.167 139.624,21.408 139.624,25.739 142.174,28.29 142.174,30.257 155.052,43.135 161.82,43.135 163.061,44.376 ; v1(164.457,43.59) cw(c164.776,43.909) 164.325,43.909 164.325,44.177 163.853,44.649 163.334,44.649 163.062,44.377 ; 163.061,44.376 cw(c163.721,43.716) 163.062,44.377 ; 163.061,44.376 163.062,44.377
M2_PET_P2_C: C80.2 J32.25 | length 1.7
  L1-TOP w0.107: J32.25@164.408,40.861 164.325,40.943 164.325,42.081 C80.2@164.661,42.416
M2_PET_P3: C78.1 MC3.22 | length 40.7
  L5-SIG w0.107: v1(135.164,19.788) ccw(c135.287,19.788) 135.287,19.666 135.545,19.666 138.118,22.238 138.118,25.675 139.769,27.326 139.769,29.668 154.649,44.548 159.049,44.548 159.055,44.554 159.155,44.554 159.155,44.556 159.286,44.556 159.295,44.548 159.552,44.548 159.56,44.556 159.691,44.556 159.691,44.554 159.791,44.554 159.798,44.548 160.698,44.548 ; 160.705,44.548 160.954,44.548 161.318,44.183 161.318,43.872 ccw(c161.669,43.872) 161.421,43.624 v1(161.455,43.59)
M2_PET_P3_C: C78.2 J32.13 | length 1.7
  L1-TOP w0.107: J32.13@161.408,40.861 161.318,40.951 161.318,42.076 C78.2@161.658,42.416
M2_PEWAKE_B: MC2.65 U5.8 | length 77.8
  L1-TOP w0.114: v1(95.123,-31.547) 95.75,-32.174 MC2.65@95.75,-33.41
  L1-TOP w0.127: v1(146.99,10.846) 147.013,10.869 U5.8@147.998,10.869
  L4-SIG w0.114: v1(95.123,-31.547) 95.123,-22.694 96.119,-21.697
  L4-SIG w0.127: 96.119,-21.697 127.831,10.014 142.613,10.014 143.248,10.649 146.793,10.649 v1(146.99,10.846)
M2_PEWAKE_B_3V3: J32.54 R39.1 U5.13 | length 35.8
  L1-TOP w0.127: U5.13@149.798,10.869 150.264,10.869 150.386,10.747 150.455,10.747 150.966,10.237 152.908,10.237 153.512,9.633 154.242,9.633 171.658,27.049 J32.54@171.658,33.311
M2_REFCLK_N: J32.53 R60.2 R61.1 | length 12
  L1-TOP w0.107: J32.53@171.408,40.861 171.503,40.765 171.503,39.675 171.869,39.31 173.124,39.31 173.957,40.143 173.957,41.942 176.832,44.817 178.402,44.817 R61.1@178.699,44.52
M2_REFCLK_P: J32.55 R40.1 R59.2 | length 11.5
  L1-TOP w0.107: J32.55@171.908,40.861 171.823,40.777 171.823,39.808 172.001,39.63 172.992,39.63 173.637,40.275 173.637,42.074 176.7,45.137 178.402,45.137 R40.1@178.699,45.434
M2_SMB_CLK: MC2.57 R34.1 U4.3 | length 102.7
  L1-TOP w0.114: MC2.57@88.75,-33.41 88.75,-34.724 v1(88.933,-34.907)
  L1-TOP w0.127: v1(138.245,30.791) 141.623,30.791 142.563,29.851 150.455,29.851 R34.1@150.988,30.385 ; R34.1@150.993,30.549 151.16,30.549 151.498,30.887 U4.3@151.944,30.887
  L4-SIG w0.114: 88.748,-18.796 88.748,-34.721 v1(88.933,-34.907)
  L4-SIG w0.127: 88.748,-18.796 88.748,-18.071 137.61,30.791 v1(138.245,30.791)
M2_SMB_CLK_1V8: J32.40 R36.1 U4.6 | length 22.9
  L1-TOP w0.127: U4.6@153.154,31.387 153.663,31.387 154.521,30.529 155.407,30.529 156.253,31.375 156.253,36.201 156.787,36.735 166.032,36.735 168.158,34.609 J32.40@168.158,33.311
M2_SMB_DATA: MC2.55 R33.1 U4.2 | length 100.4
  L1-TOP w0.114: MC2.55@88.25,-33.41 v1(88.25,-32.37)
  L1-TOP w0.127: v1(138.245,31.68) 143.579,31.68 144.341,30.918 150.473,30.918 150.993,31.438 151.044,31.387 U4.2@151.944,31.387
  L4-SIG w0.127: v1(88.25,-32.37) 88.25,-17.705 137.635,31.68 v1(138.245,31.68)
M2_SMB_DATA_1V8: J32.42 R35.1 U4.7 | length 23.2
  L1-TOP w0.127: U4.7@153.154,31.887 153.869,31.887 154.081,32.098 154.613,31.566 155.364,31.566 155.733,31.934 155.733,36.366 156.456,37.09 166.413,37.09 168.658,34.846 J32.42@168.658,33.311
M2_SUSCLK: MC2.66 U5.10 | length 83.3
  L1-TOP w0.127: v1(94.818,-35.128) 95.225,-35.128 96.063,-35.966 96.063,-38.061 95.75,-38.373 MC2.66@95.75,-39.59 ; v1(147.371,9.5) 147.371,9.855 147.585,10.069 U5.10@147.998,10.069
  L4-SIG w0.127: v1(94.818,-35.128) 94.818,-34.061 96.164,-32.715 96.164,-23.735 127.856,7.956 145.828,7.956 v1(147.371,9.5)
M2_SUSCLK_3V3: J32.68 U5.11 | length 39.3
  L1-TOP w0.127: U5.11@149.798,10.069 150.151,10.069 152.111,8.109 154.607,8.109 155.212,8.714 155.212,9.176 175.158,29.122 J32.68@175.158,33.311
MC1A_3: MC1.49 MC1A.3 | length 20.3
  L1-TOP w0.107: MC1.49@86.75,39.59 86.75,40.369 86.84,40.459 86.84,44.686 91.63,49.475 93.911,49.475 94.836,50.4 94.836,53.448 94.444,53.84 94.074,53.84 94,53.766 MC1A.3@94,53
MC1A_4: MC1.51 MC1A.4 | length 20.9
  L1-TOP w0.107: MC1.51@87.25,39.59 87.25,40.369 87.16,40.459 87.16,44.553 91.763,49.155 94.044,49.155 95.156,50.267 95.156,53.58 94.576,54.16 94.074,54.16 94,54.234 MC1A.4@94,55
MC1A_5: MC1.50 MC1A.5 | length 28.5
  L1-TOP w0.107: v1(86.712,34.452) 86.84,34.324 86.84,33.5 MC1.50@86.75,33.41
  L5-SIG w0.107: v1(86.712,34.452) 86.84,34.58 86.84,34.925 86.462,35.304 86.462,36.876 88.691,39.106 88.691,45.786 92.781,49.875 96.344,49.875 96.843,50.374 96.843,53.41 96.412,53.84 96.081,53.84 96,53.759 MC1A.5@96,53
MC1A_6: MC1.52 MC1A.6 | length 29
  L1-TOP w0.107: MC1.52@87.25,33.41 87.16,33.5 87.16,34.324 v1(87.288,34.452)
  L5-SIG w0.107: v1(87.288,34.452) 87.16,34.58 87.16,35.058 86.782,35.436 86.782,36.744 89.011,38.973 89.011,45.653 92.913,49.555 96.476,49.555 97.163,50.242 97.163,53.542 96.545,54.16 96.081,54.16 96,54.241 MC1A.6@96,55
MC1A_7: MC1.53 MC1A.7 | length 23.2
  L1-TOP w0.107: MC1.53@87.75,39.59 87.75,40.369 87.84,40.459 87.84,44.466 91.884,48.51 96.871,48.51 98.849,50.489 98.849,53.475 98.484,53.84 98.125,53.84 98,53.715 MC1A.7@98,53
MC1A_8: MC1.55 MC1A.8 | length 23.7
  L1-TOP w0.107: MC1.55@88.25,39.59 88.25,40.369 88.16,40.459 88.16,44.334 92.017,48.19 97.003,48.19 99.169,50.356 99.169,53.607 98.617,54.16 98.125,54.16 98,54.285 MC1A.8@98,55
MC1A_9: MC1.54 MC1A.9 | length 33
  L1-TOP w0.107: v1(87.712,32.369) 87.84,32.497 87.84,33.32 MC1.54@87.75,33.41
  L5-SIG w0.107: v1(87.712,32.369) 87.84,32.497 87.84,36.429 90.78,39.368 90.78,46.452 93.39,49.063 99.519,49.063 100.843,50.387 100.843,53.384 100.387,53.84 100.081,53.84 100,53.759 MC1A.9@100,53
MC1A_10: MC1.56 MC1A.10 | length 33.5
  L1-TOP w0.107: MC1.56@88.25,33.41 88.16,33.32 88.16,32.497 v1(88.289,32.369)
  L5-SIG w0.107: v1(88.289,32.369) 88.16,32.497 88.16,36.297 91.1,39.236 91.1,46.319 93.523,48.743 99.651,48.743 101.163,50.255 101.163,53.517 100.52,54.16 100.081,54.16 100,54.241 MC1A.10@100,55
MC1A_11: MC1.57 MC1A.11 | length 26.1
  L1-TOP w0.107: MC1.57@88.75,39.59 88.75,40.369 88.84,40.459 88.84,44.158 92.278,47.596 100.084,47.596 102.837,50.349 102.837,53.511 102.508,53.84 102.126,53.84 102,53.714 MC1A.11@102,53
MC1A_12: MC1.59 MC1A.12 | length 26.6
  L1-TOP w0.107: MC1.59@89.25,39.59 89.25,40.369 89.16,40.459 89.16,44.026 92.41,47.276 100.216,47.276 103.157,50.216 103.157,53.644 102.641,54.16 102.126,54.16 102,54.286 MC1A.12@102,55
MC1A_13: MC1.58 MC1A.13 | length 33.5
  L1-TOP w0.107: v1(88.712,34.452) 88.84,34.324 88.84,33.5 MC1.58@88.75,33.41
  L5-SIG w0.107: v1(88.712,34.452) 88.84,34.58 88.84,35.083 92.161,38.404 92.161,46.044 94.094,47.977 102.42,47.977 104.831,50.387 104.831,53.448 104.439,53.84 104.066,53.84 104,53.774 MC1A.13@104,53
MC1A_14: MC1.60 MC1A.14 | length 34
  L1-TOP w0.107: MC1.60@89.25,33.41 89.16,33.5 89.16,34.324 v1(89.289,34.452)
  L5-SIG w0.107: v1(89.289,34.452) 89.16,34.58 89.16,34.95 92.481,38.271 92.481,45.912 94.226,47.657 102.553,47.657 105.151,50.255 105.151,53.58 104.571,54.16 104.066,54.16 104,54.226 MC1A.14@104,55
MC1A_15: MC1.61 MC1A.15 | length 23.7
  L1-TOP w0.107: MC1.61@94.75,39.59 94.75,40.369 94.84,40.459 94.84,43.477 97.191,45.828 102.413,45.828 106.838,50.253 106.838,53.484 106.481,53.84 106.088,53.84 106,53.752 MC1A.15@106,53
MC1A_16: MC1.63 MC1A.16 | length 24.3
  L1-TOP w0.107: MC1.63@95.25,39.59 95.25,40.369 95.16,40.459 95.16,43.344 97.324,45.508 102.545,45.508 107.158,50.12 107.158,53.616 106.614,54.16 106.088,54.16 106,54.248 MC1A.16@106,55
MC1A_17: MC1.62 MC1A.17 | length 36.4
  L1-TOP w0.107: v1(94.712,32.369) 94.84,32.497 94.84,33.32 MC1.62@94.75,33.41
  L5-SIG w0.107: v1(94.712,32.369) 94.84,32.497 94.84,33.811 93.762,34.889 93.762,44.735 96.048,47.022 103.638,47.022 106.187,49.571 108.224,49.571 108.844,50.19 108.844,53.41 108.414,53.84 108.108,53.84 108,53.732 MC1A.17@108,53
MC1A_18: MC1.64 MC1A.18 | length 36.9
  L1-TOP w0.107: MC1.64@95.25,33.41 95.16,33.32 95.16,32.497 v1(95.288,32.369)
  L5-SIG w0.107: v1(95.288,32.369) 95.16,32.497 95.16,33.943 94.082,35.022 94.082,44.602 96.181,46.702 103.771,46.702 106.32,49.251 108.357,49.251 109.164,50.058 109.164,53.542 108.546,54.16 108.108,54.16 108,54.268 MC1A.18@108,55
MC1A_19: MC1.65 MC1A.19 | length 26
  L1-TOP w0.107: MC1.65@95.75,39.59 95.75,40.369 95.84,40.459 95.84,42.445 98.159,44.764 105.333,44.764 110.838,50.268 110.838,53.375 110.373,53.84 110.101,53.84 110,53.739 MC1A.19@110,53
MC1A_20: MC1.67 MC1A.20 | length 26.6
  L1-TOP w0.107: MC1.67@96.25,39.59 96.25,40.369 96.16,40.459 96.16,42.312 98.292,44.444 99.212,44.444 105.466,44.444 111.158,50.136 111.158,53.507 110.505,54.16 110.101,54.16 110,54.261 MC1A.20@110,55
MC1A_21: MC1.66 MC1A.21 | length 36.2
  L1-TOP w0.107: v1(95.712,34.452) 95.84,34.324 95.84,33.5 MC1.66@95.75,33.41
  L5-SIG w0.107: v1(95.712,34.452) 95.84,34.58 95.84,35.001 95.25,35.591 95.25,44.173 97.23,46.152 106.248,46.152 109.972,49.875 112.341,49.875 112.84,50.374 112.84,53.528 112.529,53.84 112.108,53.84 112,53.732 MC1A.21@112,53
MC1A_22: MC1.68 MC1A.22 | length 36.7
  L1-TOP w0.107: MC1.68@96.25,33.41 96.16,33.5 96.16,34.324 v1(96.289,34.452)
  L5-SIG w0.107: v1(96.289,34.452) 96.16,34.58 96.16,35.134 95.57,35.724 95.57,44.04 97.362,45.832 106.381,45.832 110.104,49.555 112.474,49.555 113.16,50.242 113.16,53.661 112.661,54.16 112.108,54.16 112,54.268 MC1A.22@112,55
MC1A_23: MC1.69 MC1A.23 | length 28.7
  L1-TOP w0.107: MC1.69@96.75,39.59 96.75,40.369 96.84,40.459 96.84,41.718 98.959,43.836 108.419,43.836 114.839,50.256 114.839,53.461 114.459,53.84 114.115,53.84 114,53.725 MC1A.23@114,53
MC1A_24: MC1.71 MC1A.24 | length 29.2
  L1-TOP w0.107: MC1.71@97.25,39.59 97.25,40.369 97.16,40.459 97.16,41.585 99.092,43.516 108.552,43.516 115.159,50.123 115.159,53.593 114.592,54.16 114.115,54.16 114,54.275 MC1A.24@114,55
MC1A_25: MC1.70 MC1A.25 | length 40.3
  L1-TOP w0.107: v1(96.712,32.369) 96.84,32.497 96.84,33.32 MC1.70@96.75,33.41
  L5-SIG w0.107: v1(96.712,32.369) 96.84,32.497 96.84,35.629 96.495,35.975 96.495,43.436 98.296,45.237 107.557,45.237 110.925,48.605 113.198,48.605 114.417,49.825 116.042,49.825 116.832,50.615 116.832,53.479 116.471,53.84 116.083,53.84 116,53.757 MC1A.25@116,53
MC1A_26: MC1.72 MC1A.26 | length 40.9
  L1-TOP w0.107: MC1.72@97.25,33.41 97.16,33.32 97.16,32.497 v1(97.288,32.369)
  L5-SIG w0.107: v1(97.288,32.369) 97.16,32.497 97.16,35.762 96.815,36.107 96.815,43.303 98.429,44.917 107.69,44.917 111.058,48.285 113.33,48.285 114.549,49.505 116.175,49.505 117.152,50.482 117.152,53.611 116.604,54.16 116.083,54.16 116,54.243 MC1A.26@116,55
MC1A_27: MC1.73 MC1A.27 | length 31.3
  L1-TOP w0.107: MC1.73@97.75,39.59 97.75,40.369 97.84,40.459 97.84,41.168 99.655,42.983 110.806,42.983 117.867,50.044 118.509,50.044 118.84,50.376 118.84,53.485 118.485,53.84 118.102,53.84 118,53.738 MC1A.27@118,53
MC1A_28: MC1.75 MC1A.28 | length 31.8
  L1-TOP w0.107: MC1.75@98.25,39.59 98.25,40.369 98.16,40.459 98.16,41.036 99.788,42.663 110.938,42.663 117.999,49.724 118.641,49.724 119.16,50.243 119.16,53.617 118.617,54.16 118.102,54.16 118,54.262 MC1A.28@118,55
MC1A_29: MC1.74 MC1A.29 | length 40.6
  L1-TOP w0.107: v1(97.712,34.452) 97.84,34.324 97.84,33.5 MC1.74@97.75,33.41
  L5-SIG w0.107: v1(97.712,34.452) 97.84,34.58 97.84,42.896 99.319,44.374 108.767,44.374 111.856,47.462 114.061,47.462 115.4,48.802 116.276,48.802 117.349,49.875 120.352,49.875 120.84,50.364 120.84,53.433 120.434,53.84 120.133,53.84 120,53.707 MC1A.29@120,53
MC1A_30: MC1.76 MC1A.30 | length 41.1
  L1-TOP w0.107: MC1.76@98.25,33.41 98.16,33.5 98.16,34.324 v1(98.289,34.452)
  L5-SIG w0.107: v1(98.289,34.452) 98.16,34.58 98.16,42.763 99.451,44.054 108.9,44.054 111.989,47.142 114.194,47.142 115.533,48.482 116.408,48.482 117.482,49.555 120.485,49.555 121.16,50.231 121.16,53.566 120.566,54.16 120.133,54.16 120,54.293 MC1A.30@120,55
MC1A_31: MC1.77 MC1A.31 | length 35.3
  L1-TOP w0.107: v1(98.712,40.632) 98.84,40.504 98.84,39.68 MC1.77@98.75,39.59
  L5-SIG w0.107: v1(98.712,40.632) 98.84,40.76 98.84,41.965 100.233,43.358 109.722,43.358 112.175,45.811 114.506,45.811 117.795,49.101 122.341,49.101 122.84,49.6 122.84,53.41 122.409,53.84 122.128,53.84 122,53.712 MC1A.31@122,53
MC1A_32: MC1.79 MC1A.32 | length 35.8
  L1-TOP w0.107: MC1.79@99.25,39.59 99.16,39.68 99.16,40.504 v1(99.289,40.632)
  L5-SIG w0.107: v1(99.289,40.632) 99.16,40.76 99.16,41.833 100.366,43.038 109.854,43.038 112.308,45.491 114.638,45.491 117.927,48.781 122.473,48.781 123.16,49.467 123.16,53.542 122.542,54.16 122.128,54.16 122,54.288 MC1A.32@122,55
MC1A_33: MC1.78 MC1A.33 | length 44.7
  L1-TOP w0.107: v1(98.712,32.369) 98.84,32.497 98.84,33.32 MC1.78@98.75,33.41
  L5-SIG w0.107: v1(98.712,32.369) 98.84,32.497 98.84,35.575 99.441,36.176 99.441,36.855 98.715,37.582 98.715,39.325 100.101,40.712 100.101,41.204 101.315,42.418 110.993,42.418 113.167,44.592 114.446,44.592 118.116,48.263 123.052,48.263 124.846,50.057 124.846,53.428 124.434,53.84 124.084,53.84 124,53.756 MC1A.33@124,53
MC1A_34: MC1.80 MC1A.34 | length 45.3
  L1-TOP w0.107: MC1.80@99.25,33.41 99.16,33.32 99.16,32.497 v1(99.289,32.369)
  L5-SIG w0.107: v1(99.289,32.369) 99.16,32.497 99.16,35.443 99.761,36.043 99.761,36.988 99.035,37.714 99.035,39.192 100.421,40.579 100.421,41.072 101.448,42.098 111.125,42.098 113.299,44.272 114.578,44.272 118.249,47.942 123.184,47.942 125.166,49.924 125.166,53.561 124.567,54.16 124.084,54.16 124,54.244 MC1A.34@124,55
MC1A_35: MC1.81 MC1A.35 | length 38.7
  L1-TOP w0.107: v1(99.712,38.549) 99.84,38.677 99.84,39.5 MC1.81@99.75,39.59
  L5-SIG w0.107: v1(99.712,38.549) 99.84,38.677 99.84,39.079 100.822,40.061 101.963,40.061 102.286,40.383 102.286,41.042 102.748,41.504 112.462,41.504 118.383,47.424 124.055,47.424 126.84,50.209 126.84,53.461 126.461,53.84 126.091,53.84 126,53.749 MC1A.35@126,53
MC1A_36: MC1.83 MC1A.36 | length 39.3
  L1-TOP w0.107: MC1.83@100.25,39.59 100.16,39.5 100.16,38.677 v1(100.288,38.549)
  L5-SIG w0.107: v1(100.288,38.549) 100.16,38.677 100.16,38.946 100.955,39.741 102.096,39.741 102.606,40.251 102.606,40.909 102.88,41.184 112.595,41.184 118.515,47.104 124.188,47.104 127.16,50.077 127.16,53.593 126.593,54.16 126.091,54.16 126,54.251 MC1A.36@126,55
MC1A_37: MC1.82 MC1A.37 | length 43.4
  L1-TOP w0.107: v1(99.712,34.452) 99.84,34.324 99.84,33.5 MC1.82@99.75,33.41
  L5-SIG w0.107: v1(99.712,34.452) 99.84,34.58 99.84,35.185 100.061,35.405 100.061,37.649 100.86,38.448 101.437,38.448 102.314,39.325 103.318,39.325 103.657,39.665 108.795,39.665 109.256,40.126 112.52,40.126 119.099,46.704 125.202,46.704 128.847,50.349 128.847,53.473 128.48,53.84 128.085,53.84 128,53.755 MC1A.37@128,53
MC1A_38: MC1.84 MC1A.38 | length 44
  L1-TOP w0.107: MC1.84@100.25,33.41 100.16,33.5 100.16,34.324 v1(100.288,34.452)
  L5-SIG w0.107: v1(100.288,34.452) 100.16,34.58 100.16,35.052 100.381,35.272 100.381,37.516 100.993,38.128 101.569,38.128 102.446,39.005 103.45,39.005 103.79,39.345 108.927,39.345 109.388,39.805 112.653,39.805 119.231,46.384 125.334,46.384 129.167,50.216 129.167,53.606 128.612,54.16 128.085,54.16 128,54.245 MC1A.38@128,55
MC1A_39: MC1.85 MC1A.39 | length 40.9
  L1-TOP w0.114: MC1.85@100.75,39.59 100.75,37.783 v1(101.011,37.522)
  L5-SIG w0.117: v1(101.011,37.522) 109.982,37.522 111.289,38.829 112.474,38.829 119.644,45.999 127.253,45.999 131.056,49.803 131.056,51.944 MC1A.39@130,53
MC1A_40: MC1.86 MC1A.40 | length 47.1
  L1-TOP w0.114: v1(100.351,32.163) 100.75,32.562 MC1.86@100.75,33.41
  L5-SIG w0.117: v1(100.351,32.163) 101.437,33.249 102.244,33.249 104.303,35.308 108.556,35.308 109.169,35.922 112.748,35.922 113.03,36.203 113.03,38.481 120.142,45.593 127.507,45.593 131.501,49.587 131.501,53.499 MC1A.40@130,55
MC1B_1: MC1.121 MC1B.1 | length 37.2
  L1-TOP w0.107: MC1.121@114.75,39.59 114.75,40.369 114.84,40.459 114.84,45.474 118.892,49.526 138.387,49.526 138.842,49.981 138.842,53.715 138.716,53.84 138.054,53.84 138,53.786 MC1B.1@138,53
MC1B_2: MC1.123 MC1B.2 | length 37.8
  L1-TOP w0.107: MC1.123@115.25,39.59 115.25,40.369 115.16,40.459 115.16,45.342 119.025,49.206 138.519,49.206 139.162,49.848 139.162,53.847 138.849,54.16 138.054,54.16 138,54.214 MC1B.2@138,55
MC1B_3: MC1.122 MC1B.3 | length 42.5
  L1-TOP w0.107: v1(114.712,34.452) 114.84,34.324 114.84,33.5 MC1.122@114.75,33.41
  L5-SIG w0.107: v1(114.712,34.452) 114.84,34.58 114.84,34.788 113.716,35.912 113.716,37.613 114.351,38.248 114.351,38.887 120.65,45.187 128.83,45.187 133.57,49.926 140.387,49.926 140.848,50.387 140.848,53.461 140.469,53.84 140.048,53.84 140,53.792 MC1B.3@140,53
MC1B_4: MC1.124 MC1B.4 | length 43
  L1-TOP w0.107: MC1.124@115.25,33.41 115.16,33.5 115.16,34.324 v1(115.288,34.452)
  L5-SIG w0.107: v1(115.288,34.452) 115.16,34.58 115.16,34.92 114.036,36.045 114.036,37.48 114.671,38.115 114.671,38.755 120.783,44.867 128.963,44.867 133.702,49.606 140.52,49.606 141.168,50.255 141.168,53.593 140.601,54.16 140.048,54.16 140,54.208 MC1B.4@140,55
MC1B_5: MC1.125 MC1B.5 | length 39.7
  L1-TOP w0.107: MC1.125@115.75,39.59 115.75,40.369 115.84,40.459 115.84,45.101 119.503,48.764 141.384,48.764 142.836,50.216 142.836,53.53 142.526,53.84 142.09,53.84 142,53.75 MC1B.5@142,53
MC1B_6: MC1.127 MC1B.6 | length 40.3
  L1-TOP w0.107: MC1.127@116.25,39.59 116.25,40.369 116.16,40.459 116.16,44.969 119.636,48.444 141.517,48.444 143.156,50.084 143.156,53.662 142.659,54.16 142.09,54.16 142,54.25 MC1B.6@142,55
MC1B_7: MC1.126 MC1B.7 | length 47.3
  L1-TOP w0.107: v1(115.712,32.369) 115.84,32.497 115.84,33.32 MC1.126@115.75,33.41
  L5-SIG w0.107: v1(115.712,32.369) 115.84,32.497 115.84,34.788 115.047,35.581 115.047,38.264 121.156,44.374 129.785,44.374 134.179,48.768 143.687,48.768 144.849,49.93 144.849,53.422 144.431,53.84 144.087,53.84 144,53.753 MC1B.7@144,53
MC1B_8: MC1.128 MC1B.8 | length 47.9
  L1-TOP w0.107: MC1.128@116.25,33.41 116.16,33.32 116.16,32.497 v1(116.288,32.369)
  L5-SIG w0.107: v1(116.288,32.369) 116.16,32.497 116.16,34.92 115.367,35.714 115.367,38.132 121.289,44.054 129.917,44.054 134.312,48.448 143.819,48.448 145.169,49.797 145.169,53.555 144.564,54.16 144.087,54.16 144,54.247 MC1B.8@144,55
MC1B_9: MC1.129 MC1B.9 | length 42.4
  L1-TOP w0.107: MC1.129@116.75,39.59 116.75,40.369 116.84,40.459 116.84,44.603 120.242,48.005 144.613,48.005 146.843,50.235 146.843,53.486 146.488,53.84 146.131,53.84 146,53.709 MC1B.9@146,53
MC1B_10: MC1.131 MC1B.10 | length 42.9
  L1-TOP w0.107: MC1.131@117.25,39.59 117.25,40.369 117.16,40.459 117.16,44.47 120.375,47.685 144.745,47.685 147.163,50.102 147.163,53.618 146.621,54.16 146.131,54.16 146,54.291 MC1B.10@146,55
MC1B_11: MC1.130 MC1B.11 | length 47.7
  L1-TOP w0.107: v1(116.712,34.452) 116.84,34.324 116.84,33.5 MC1.130@116.75,33.41
  L5-SIG w0.107: v1(116.712,34.452) 116.84,34.58 116.84,34.773 115.94,35.673 115.94,37.454 122.009,43.523 130.623,43.523 134.852,47.752 146.252,47.752 148.836,50.336 148.836,53.428 148.424,53.84 148.074,53.84 148,53.766 MC1B.11@148,53
MC1B_12: MC1.132 MC1B.12 | length 48.2
  L1-TOP w0.107: MC1.132@117.25,33.41 117.16,33.5 117.16,34.324 v1(117.288,34.452)
  L5-SIG w0.107: v1(117.288,34.452) 117.16,34.58 117.16,34.905 116.26,35.805 116.26,37.322 122.141,43.203 130.756,43.203 134.985,47.432 146.385,47.432 149.156,50.204 149.156,53.561 148.557,54.16 148.074,54.16 148,54.234 MC1B.12@148,55
MC1B_13: MC1.133 MC1B.13 | length 45.1
  L1-TOP w0.107: MC1.133@117.75,39.59 117.75,40.369 117.84,40.459 117.84,44.079 121.002,47.24 147.861,47.24 150.83,50.209 150.83,53.486 150.476,53.84 150.083,53.84 150,53.757 MC1B.13@150,53
MC1B_14: MC1.135 MC1B.14 | length 45.6
  L1-TOP w0.107: MC1.135@118.25,39.59 118.25,40.369 118.16,40.459 118.16,43.946 121.134,46.92 147.994,46.92 151.15,50.077 151.15,53.618 150.609,54.16 150.083,54.16 150,54.243 MC1B.14@150,55
MC1B_15: MC1.134 MC1B.15 | length 51.2
  L1-TOP w0.107: v1(117.712,32.369) 117.84,32.497 117.84,33.32 MC1.134@117.75,33.41
  L5-SIG w0.107: v1(117.712,32.369) 117.84,32.497 117.84,37.78 122.707,42.647 131.029,42.647 134.992,46.609 146.46,46.609 149.898,50.047 150.576,50.047 150.846,50.316 150.846,51.619 151.399,52.173 152.575,52.173 152.85,52.447 152.85,53.448 152.457,53.84 152.088,53.84 152,53.752 MC1B.15@152,53
MC1B_16: MC1.136 MC1B.16 | length 51.8
  L1-TOP w0.107: MC1.136@118.25,33.41 118.16,33.32 118.16,32.497 v1(118.288,32.369)
  L5-SIG w0.107: v1(118.288,32.369) 118.16,32.497 118.16,37.647 122.84,42.327 131.162,42.327 135.124,46.289 146.592,46.289 150.03,49.727 150.709,49.727 151.166,50.183 151.166,51.487 151.531,51.853 152.708,51.853 153.17,52.314 153.17,53.58 152.59,54.16 152.088,54.16 152,54.248 MC1B.16@152,55
MC1B_17: MC1.137 MC1B.17 | length 48.3
  L1-TOP w0.107: MC1.137@118.75,39.59 118.75,40.369 118.84,40.459 118.84,43.58 121.738,46.478 152.001,46.478 154.844,49.32 154.844,53.41 154.413,53.84 154.082,53.84 154,53.758 MC1B.17@154,53
MC1B_18: MC1.139 MC1B.18 | length 48.8
  L1-TOP w0.107: MC1.139@119.25,39.59 119.25,40.369 119.16,40.459 119.16,43.448 121.871,46.158 152.134,46.158 155.164,49.188 155.164,53.542 154.546,54.16 154.082,54.16 154,54.242 MC1B.18@154,55
MC1B_19: MC1.138 MC1B.19 | length 52.3
  L1-TOP w0.107: v1(118.712,34.452) 118.84,34.324 118.84,33.5 MC1.138@118.75,33.41
  L5-SIG w0.107: v1(118.712,34.452) 118.84,34.58 118.84,37.23 122.123,40.513 126.624,40.513 127.868,41.758 132.436,41.758 136.099,45.421 146.53,45.421 150.388,49.28 150.858,49.28 151.523,49.945 156.522,49.945 156.837,50.26 156.837,53.413 156.41,53.84 156.101,53.84 156,53.739 MC1B.19@156,53
MC1B_20: MC1.140 MC1B.20 | length 52.8
  L1-TOP w0.107: MC1.140@119.25,33.41 119.16,33.5 119.16,34.324 v1(119.288,34.452)
  L5-SIG w0.107: v1(119.288,34.452) 119.16,34.58 119.16,37.098 122.256,40.193 126.756,40.193 128.001,41.438 132.568,41.438 136.232,45.101 146.662,45.101 150.52,48.96 150.99,48.96 151.656,49.625 156.655,49.625 157.157,50.128 157.157,53.546 156.543,54.16 156.101,54.16 156,54.261 MC1B.20@156,55
MC1B_21: MC1.141 MC1B.21 | length 50.4
  L1-TOP w0.107: MC1.141@119.75,39.59 119.75,40.369 119.84,40.459 119.84,42.853 122.703,45.716 152.56,45.716 156.611,49.767 158.262,49.767 158.844,50.349 158.844,53.549 158.553,53.84 158.082,53.84 158,53.758 MC1B.21@158,53
MC1B_22: MC1.143 MC1B.22 | length 50.9
  L1-TOP w0.107: MC1.143@120.25,39.59 120.25,40.369 120.16,40.459 120.16,42.72 122.836,45.396 152.693,45.396 156.744,49.447 158.395,49.447 159.164,50.216 159.164,53.682 158.686,54.16 158.082,54.16 158,54.242 MC1B.22@158,55
MC1B_23: MC1.142 MC1B.23 | length 57.1
  L1-TOP w0.107: v1(119.712,32.369) 119.84,32.497 119.84,33.32 MC1.142@119.75,33.41
  L5-SIG w0.107: v1(119.712,32.369) 119.84,32.497 119.84,36.554 122.898,39.611 127.964,39.611 129.192,40.839 133.105,40.839 136.385,44.12 146.646,44.12 151.666,49.14 159.756,49.14 160.838,50.222 160.838,53.499 160.497,53.84 160.076,53.84 160,53.764 MC1B.23@160,53
MC1B_24: MC1.144 MC1B.24 | length 57.6
  L1-TOP w0.107: MC1.144@120.25,33.41 120.16,33.32 120.16,32.497 v1(120.288,32.369)
  L5-SIG w0.107: v1(120.288,32.369) 120.16,32.497 120.16,36.421 123.03,39.291 128.096,39.291 129.324,40.519 133.237,40.519 136.518,43.8 146.778,43.8 151.799,48.82 159.888,48.82 161.158,50.089 161.158,53.631 160.629,54.16 160.076,54.16 160,54.236 MC1B.24@160,55
MC1B_25: MC1.145 MC1B.25 | length 53.1
  L1-TOP w0.107: MC1.145@120.75,39.59 120.75,40.369 120.84,40.459 120.84,42.177 123.618,44.954 153.047,44.954 156.486,48.393 161.257,48.393 162.832,49.968 162.832,53.486 162.478,53.84 162.083,53.84 162,53.757 MC1B.25@162,53
MC1B_26: MC1.147 MC1B.26 | length 53.7
  L1-TOP w0.107: MC1.147@121.25,39.59 121.25,40.369 121.16,40.459 121.16,42.044 123.75,44.634 153.18,44.634 156.619,48.073 161.39,48.073 163.152,49.835 163.152,53.618 162.61,54.16 162.083,54.16 162,54.243 MC1B.26@162,55
MC1B_27: MC1.146 MC1B.27 | length 57.9
  L1-TOP w0.107: v1(120.712,34.452) 120.84,34.324 120.84,33.5 MC1.146@120.75,33.41
  L5-SIG w0.107: v1(120.712,34.452) 120.84,34.58 120.84,35.619 122.759,37.537 131.873,37.537 132.56,38.225 132.56,38.872 136.614,42.926 146.777,42.926 152.196,48.345 160.764,48.345 162.034,49.615 164.295,49.615 164.838,50.159 164.838,53.511 164.51,53.84 164.051,53.84 164,53.789 MC1B.27@164,53
MC1B_28: MC1.148 MC1B.28 | length 58.4
  L1-TOP w0.107: MC1.148@121.25,33.41 121.16,33.5 121.16,34.324 v1(121.288,34.452)
  L5-SIG w0.107: v1(121.288,34.452) 121.16,34.58 121.16,35.486 122.891,37.217 132.005,37.217 132.88,38.092 132.88,38.74 136.746,42.606 146.91,42.606 152.329,48.025 160.897,48.025 162.167,49.295 164.427,49.295 165.158,50.026 165.158,53.644 164.642,54.16 164.051,54.16 164,54.211 MC1B.28@164,55
MC1B_29: MC1.149 MC1B.29 | length 55.8
  L1-TOP w0.107: MC1.149@121.75,39.59 121.75,40.369 121.84,40.459 121.84,41.576 124.418,44.154 154.139,44.154 157.134,47.149 163.988,47.149 166.845,50.006 166.845,53.524 166.529,53.84 166.083,53.84 166,53.757 MC1B.29@166,53
MC1B_30: MC1.151 MC1B.30 | length 56.3
  L1-TOP w0.107: MC1.151@122.25,39.59 122.25,40.369 122.16,40.459 122.16,41.444 124.551,43.834 154.272,43.834 157.267,46.829 164.12,46.829 167.165,49.874 167.165,53.657 166.662,54.16 166.083,54.16 166,54.243 MC1B.30@166,55
MC1B_31: MC1.150 MC1B.31 | length 62.9
  L1-TOP w0.107: v1(121.712,32.369) 121.84,32.497 121.84,33.32 MC1.150@121.75,33.41
  L5-SIG w0.107: v1(121.712,32.369) 121.84,32.497 121.84,35.164 122.727,36.051 132.551,36.051 133.528,37.029 133.528,38.379 136.906,41.758 147.04,41.758 152.789,47.507 161.505,47.507 162.671,48.673 167.132,48.673 168.839,50.38 168.839,53.473 168.472,53.84 168.102,53.84 168,53.738 MC1B.31@168,53
MC1B_32: MC1.152 MC1B.32 | length 63.5
  L1-TOP w0.107: MC1.152@122.25,33.41 122.16,33.32 122.16,32.497 v1(122.288,32.369)
  L5-SIG w0.107: v1(122.288,32.369) 122.16,32.497 122.16,35.032 122.86,35.731 132.683,35.731 133.848,36.896 133.848,38.247 137.039,41.438 147.172,41.438 152.921,47.187 161.638,47.187 162.804,48.353 167.264,48.353 169.159,50.247 169.159,53.606 168.605,54.16 168.102,54.16 168,54.262 MC1B.32@168,55
MC1B_33: MC1.153 MC1B.33 | length 58.4
  L1-TOP w0.107: MC1.153@122.75,39.59 122.75,40.369 122.84,40.459 122.84,41.129 125.078,43.367 155.549,43.367 158.163,45.98 166.647,45.98 170.833,50.166 170.833,53.435 170.428,53.84 170.071,53.84 170,53.769 MC1B.33@170,53
MC1B_34: MC1.155 MC1B.34 | length 58.9
  L1-TOP w0.107: MC1.155@123.25,39.59 123.25,40.369 123.16,40.459 123.16,40.996 125.211,43.047 155.682,43.047 158.295,45.66 166.78,45.66 171.153,50.033 171.153,53.568 170.56,54.16 170.071,54.16 170,54.231 MC1B.34@170,55
MC1B_35: MC1.154 MC1B.35 | length 64.2
  L1-TOP w0.107: v1(122.712,34.452) 122.84,34.324 122.84,33.5 MC1.154@122.75,33.41
  L5-SIG w0.107: v1(122.712,34.452) 122.84,34.58 122.84,34.854 123.134,35.148 126.925,35.148 127.08,35.303 129.64,35.303 130.196,34.747 132.588,34.747 134.722,36.881 134.722,38.172 136.975,40.425 145.702,40.425 145.706,40.421 146.023,40.421 146.028,40.425 147.054,40.425 153.294,46.666 162.222,46.666 163.223,47.667 170.36,47.667 172.839,50.146 172.839,53.479 172.478,53.84 172.09,53.84 172,53.75 MC1B.35@172,53
MC1B_36: MC1.156 MC1B.36 | length 64.8
  L1-TOP w0.107: MC1.156@123.25,33.41 123.16,33.5 123.16,34.324 v1(123.288,34.452)
  L5-SIG w0.107: v1(123.288,34.452) 123.16,34.58 123.16,34.722 123.266,34.828 127.191,34.828 127.347,34.983 129.507,34.983 130.063,34.427 132.721,34.427 135.042,36.748 135.042,38.039 137.108,40.105 145.569,40.105 145.573,40.101 146.156,40.101 146.16,40.105 147.186,40.105 153.427,46.346 162.355,46.346 163.356,47.347 170.493,47.347 173.159,50.013 173.159,53.611 172.611,54.16 172.09,54.16 172,54.25 MC1B.36@172,55
MC1B_37: MC1.157 MC1B.37 | length 61.2
  L1-TOP w0.107: MC1.157@123.75,39.59 123.75,40.369 123.84,40.459 123.84,40.681 125.726,42.566 156.146,42.566 158.397,44.817 169.581,44.817 174.831,50.067 174.831,53.526 174.517,53.84 174.084,53.84 174,53.756 MC1B.37@174,53
MC1B_38: MC1.159 MC1B.38 | length 61.7
  L1-TOP w0.107: MC1.159@124.25,39.59 124.25,40.369 124.16,40.459 124.16,40.548 125.859,42.246 156.279,42.246 158.529,44.497 169.713,44.497 175.151,49.935 175.151,53.659 174.65,54.16 174.084,54.16 174,54.244 MC1B.38@174,55
MC1B_39: MC1.158 MC1B.39 | length 67.7
  L1-TOP w0.107: v1(123.712,32.369) 123.84,32.497 123.84,33.32 MC1.158@123.75,33.41
  L5-SIG w0.107: v1(123.712,32.369) 123.84,32.497 123.84,32.949 124.54,33.649 135.841,33.649 136.734,32.756 140.798,32.756 153.893,45.851 163.139,45.851 163.903,46.615 173.093,46.615 176.929,50.451 176.929,53.397 176.486,53.84 176.103,53.84 176,53.737 MC1B.39@176,53
MC1B_40: MC1.160 MC1B.40 | length 68.2
  L1-TOP w0.107: MC1.160@124.25,33.41 124.16,33.32 124.16,32.497 v1(124.288,32.369)
  L5-SIG w0.107: v1(124.288,32.369) 124.16,32.497 124.16,32.817 124.672,33.328 135.709,33.328 136.601,32.436 140.931,32.436 154.026,45.531 163.271,45.531 164.036,46.295 173.226,46.295 177.249,50.318 177.249,53.53 176.618,54.16 176.103,54.16 176,54.263 MC1B.40@176,55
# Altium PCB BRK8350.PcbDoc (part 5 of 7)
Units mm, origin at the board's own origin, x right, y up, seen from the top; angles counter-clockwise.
Board outline 240 x 150 mm, 8 copper layers (L1-TOP, L2-GND, L3-PWR, L4-SIG, L5-SIG, L6-PWR, L7-GND, L8-BOT), stack 1.465 mm thick; 277 components, 542 nets, 1814 pads, 2338 vias.

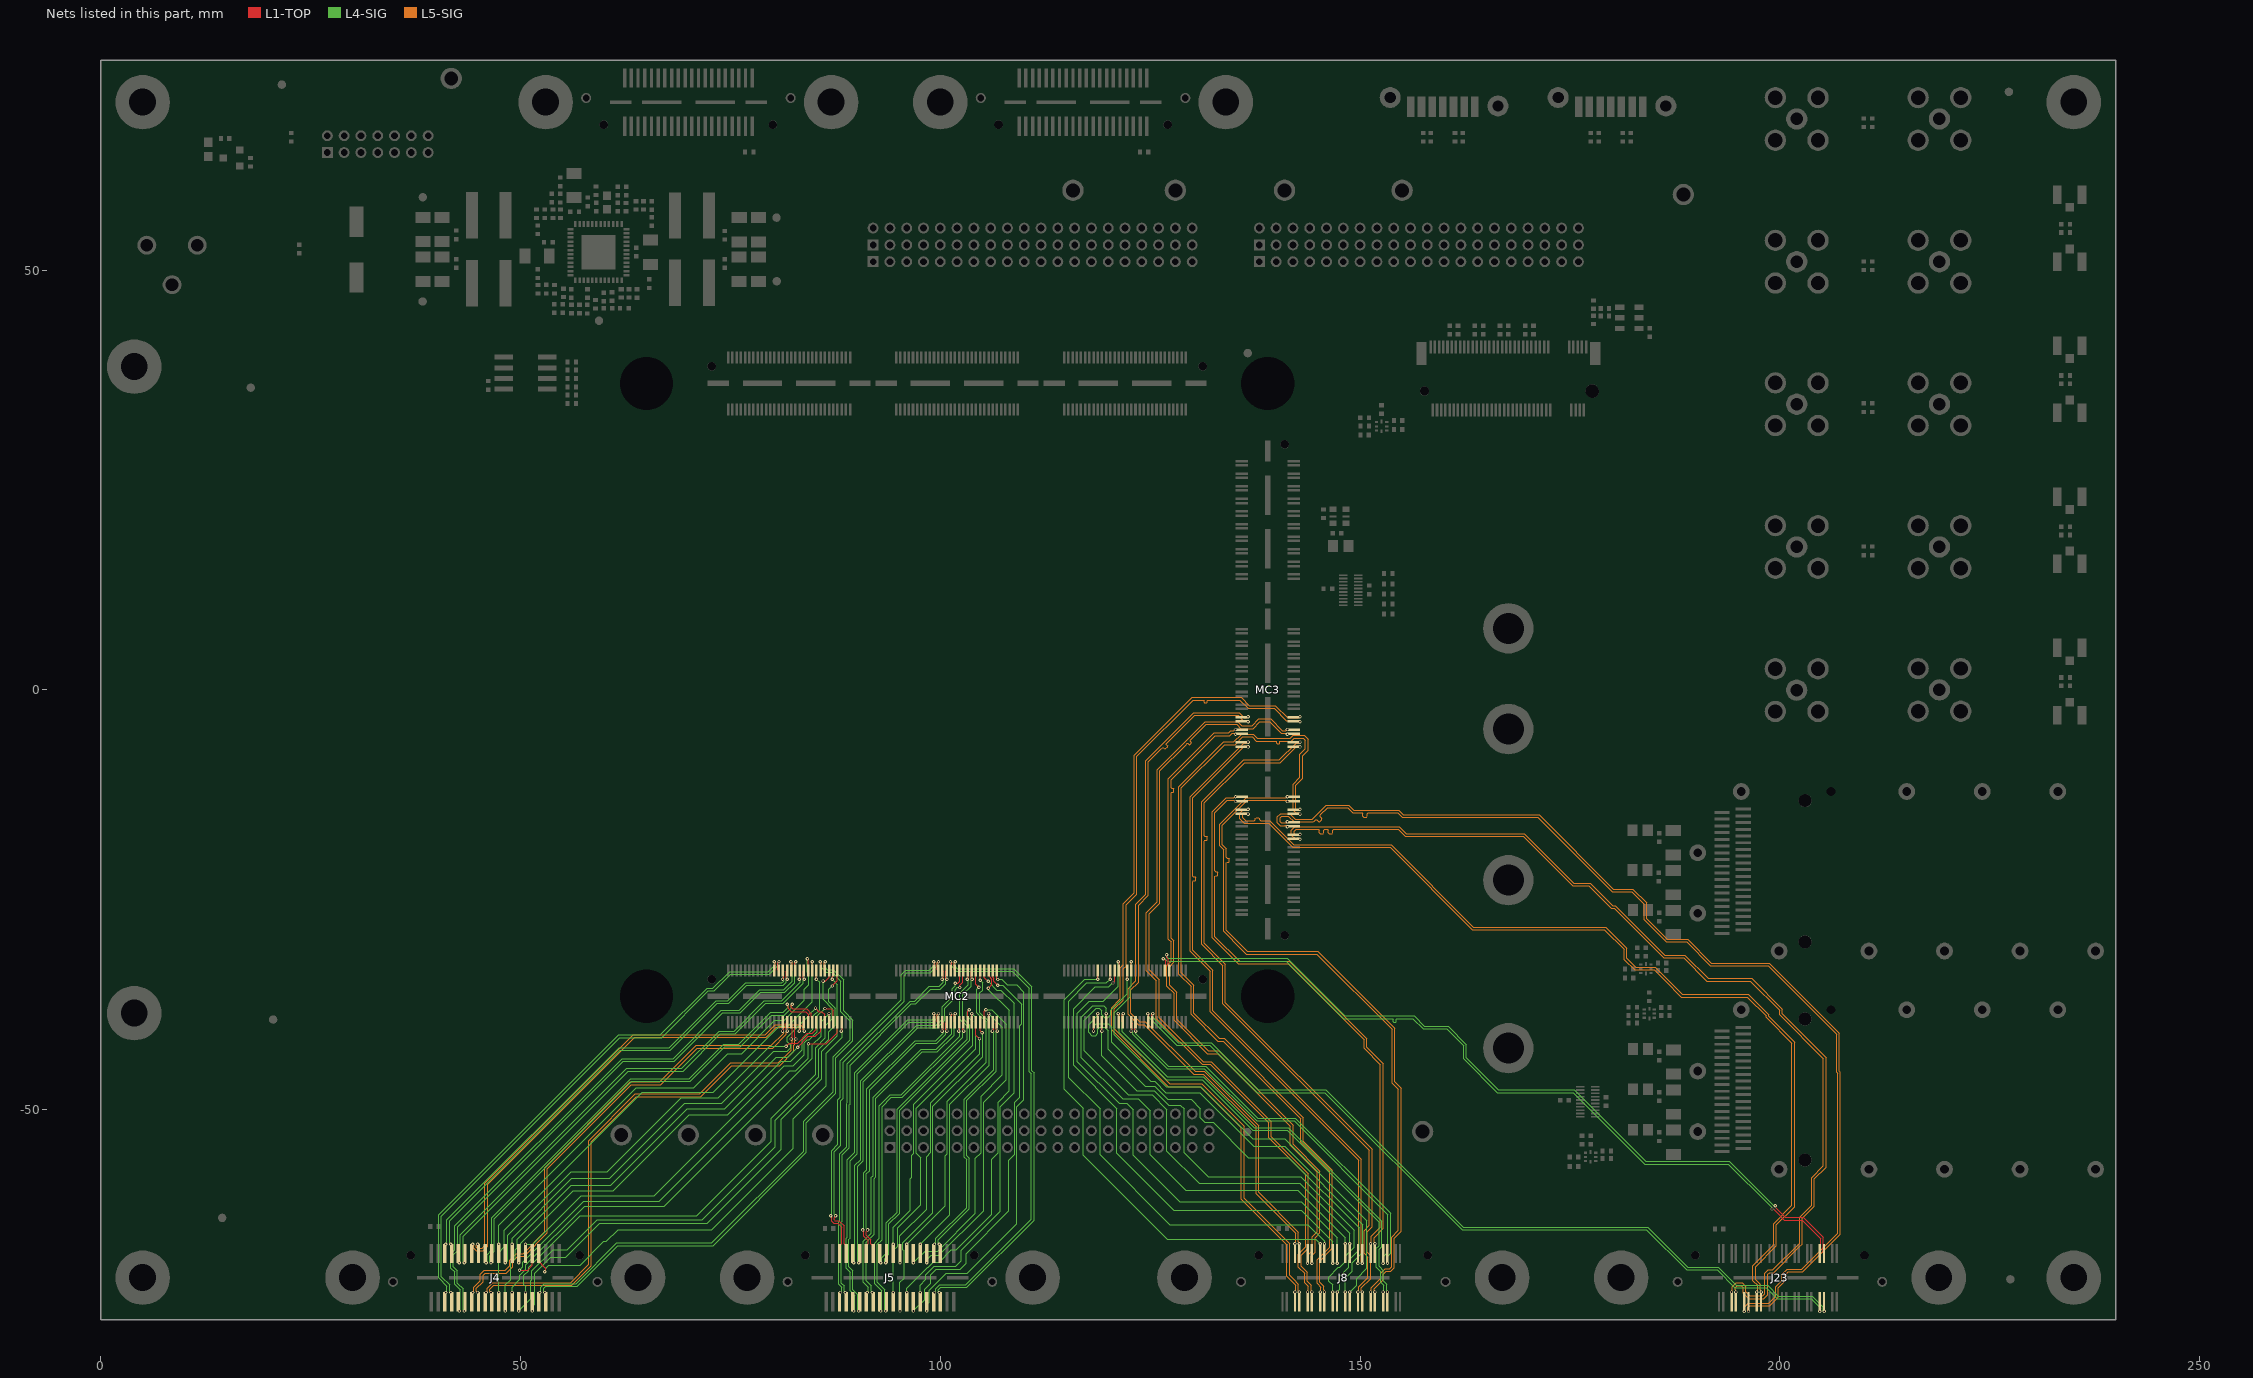
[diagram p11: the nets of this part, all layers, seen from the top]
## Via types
v1: diameter 0.406, hole 0.203, L1-TOP to L8-BOT, tented both sides, 2338 vias

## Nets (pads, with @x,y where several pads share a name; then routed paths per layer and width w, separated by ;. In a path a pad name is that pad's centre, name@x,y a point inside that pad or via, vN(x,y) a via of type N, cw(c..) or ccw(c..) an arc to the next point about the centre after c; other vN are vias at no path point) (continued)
PORTC_C2P_CLKP: J4.34 MC2.56 | length 56
  L1-TOP w0.107: J4.34@52.199,-67.135 52.199,-68.069 52.521,-68.391 52.521,-68.447 53.039,-68.965 53.039,-69.079 52.906,-69.212 v1(52.906,-69.291) ; v1(88.212,-40.631) 88.34,-40.503 88.34,-39.68 MC2.56@88.25,-39.59
  L4-SIG w0.107: v1(52.906,-69.291) 52.906,-69.212 53.039,-69.079 53.039,-68.854 53.379,-68.514 57.114,-68.514 59.936,-65.692 60.22,-65.692 61.625,-64.287 72.796,-64.287 82.499,-54.585 82.499,-51.059 86.436,-47.122 86.436,-43.256 88.34,-41.352 88.34,-40.759 v1(88.212,-40.631)
PORTC_P2C_CLKN: J4.35 MC2.47 | length 66.6
  L1-TOP w0.107: MC2.47@86.25,-33.41 86.16,-33.32 86.16,-32.496 v1(86.288,-32.368)
  L4-SIG w0.107: v1(52.892,-71.764) 52.759,-71.631 52.759,-71.253 52.995,-71.018 56.776,-71.018 61.612,-66.182 72.94,-66.182 84.032,-55.09 84.032,-51.527 87.544,-48.016 87.544,-43.835 89.601,-41.778 89.601,-39.346 88.483,-38.228 88.483,-34.538 87.255,-33.31 86.548,-33.31 86.16,-32.922 86.16,-32.496 v1(86.288,-32.368)
PORTC_P2C_CLKP: J4.33 MC2.45 | length 66.6
  L1-TOP w0.107: v1(85.712,-32.368) 85.84,-32.496 85.84,-33.32 MC2.45@85.75,-33.41
  L4-SIG w0.107: v1(52.306,-71.764) 52.439,-71.631 52.439,-71.121 52.862,-70.698 56.643,-70.698 61.48,-65.862 72.807,-65.862 83.712,-54.957 83.712,-51.395 87.224,-47.884 87.224,-43.702 89.281,-41.645 89.281,-39.478 88.163,-38.36 88.163,-34.671 87.122,-33.63 86.415,-33.63 85.84,-33.055 85.84,-32.496 v1(85.712,-32.368)
PORTC_S0_D0P: J4.5 MC2.23 | length 63.7
  L1-TOP w0.107: v1(80.212,-32.368) 80.34,-32.496 80.34,-33.32 MC2.23@80.25,-33.41
  L4-SIG w0.107: v1(41.105,-71.764) 41.238,-71.631 41.238,-70.995 40.249,-70.006 40.249,-62.527 61.694,-41.082 66.669,-41.082 72.217,-35.535 72.928,-35.535 74.924,-33.538 79.517,-33.538 80.34,-32.715 80.34,-32.496 v1(80.212,-32.368)
PORTC_S1_D1P: J4.6 MC2.27 | length 56.3
  L1-TOP w0.107: v1(81.212,-34.451) 81.34,-34.323 81.34,-33.5 MC2.27@81.25,-33.41
  L4-SIG w0.107: v1(41.105,-66.034) 41.238,-65.901 41.238,-63.11 61.742,-42.606 67.705,-42.606 73.318,-36.993 74.696,-36.993 76.814,-34.874 81.137,-34.874 81.34,-34.671 81.34,-34.579 v1(81.212,-34.451)
PORTC_S2_D0N: J4.7 MC2.25 | length 63.7
  L1-TOP w0.107: MC2.25@80.75,-33.41 80.66,-33.32 80.66,-32.496 v1(80.788,-32.368)
  L4-SIG w0.107: v1(41.691,-71.764) 41.558,-71.631 41.558,-70.863 40.569,-69.874 40.569,-62.66 61.827,-41.402 66.802,-41.402 72.349,-35.855 73.061,-35.855 75.057,-33.858 79.65,-33.858 80.66,-32.848 80.66,-32.496 v1(80.788,-32.368)
PORTC_S3_D1N: J4.8 MC2.29 | length 56.3
  L1-TOP w0.107: MC2.29@81.75,-33.41 81.66,-33.5 81.66,-34.323 v1(81.788,-34.451)
  L4-SIG w0.107: v1(41.691,-66.034) 41.558,-65.901 41.558,-63.242 61.874,-42.926 67.838,-42.926 73.451,-37.313 74.828,-37.313 76.947,-35.194 81.27,-35.194 81.66,-34.804 81.66,-34.579 v1(81.788,-34.451)
PORTC_S4_D2P: J4.9 MC2.31 | length 66.6
  L1-TOP w0.107: v1(82.212,-32.368) 82.34,-32.496 82.34,-33.32 MC2.31@82.25,-33.41
  L4-SIG w0.107: v1(42.705,-73.967) 42.838,-73.834 42.838,-71.465 42.167,-70.794 42.167,-69.321 41.697,-68.851 41.697,-67.159 42.182,-66.673 42.182,-63.817 62.097,-43.901 68.183,-43.901 73.934,-38.151 76.052,-38.151 78.491,-35.712 81.356,-35.712 82.34,-34.728 82.34,-32.496 v1(82.212,-32.368)
PORTC_S5_D3P: J4.10 MC2.35 | length 57.9
  L1-TOP w0.107: v1(83.212,-34.451) 83.34,-34.323 83.34,-33.5 MC2.35@83.25,-33.41
  L4-SIG w0.107: v1(42.705,-68.236) 42.838,-68.103 42.838,-64.913 62.682,-45.07 69.23,-45.07 73.66,-40.64 75.438,-40.64 79.056,-37.022 81.142,-37.022 83.34,-34.823 83.34,-34.579 v1(83.212,-34.451)
PORTC_S6_D2N: J4.11 MC2.33 | length 66.6
  L1-TOP w0.107: MC2.33@82.75,-33.41 82.66,-33.32 82.66,-32.496 v1(82.789,-32.368)
  L4-SIG w0.107: v1(43.291,-73.967) 43.158,-73.834 43.158,-71.333 42.487,-70.661 42.487,-69.188 42.017,-68.718 42.017,-67.291 42.502,-66.806 42.502,-63.95 62.23,-44.221 68.316,-44.221 74.066,-38.471 76.185,-38.471 78.623,-36.032 81.489,-36.032 82.66,-34.861 82.66,-32.496 v1(82.789,-32.368)
PORTC_S7_D3N: J4.12 MC2.37 | length 57.9
  L1-TOP w0.107: MC2.37@83.75,-33.41 83.66,-33.5 83.66,-34.323 v1(83.788,-34.451)
  L4-SIG w0.107: v1(43.291,-68.236) 43.158,-68.103 43.158,-65.046 62.814,-45.39 69.363,-45.39 73.793,-40.96 75.571,-40.96 79.189,-37.342 81.274,-37.342 83.66,-34.956 83.66,-34.579 v1(83.788,-34.451)
PORTC_S8_D4P: J4.13 MC2.28 | length 56.9
  L1-TOP w0.107: v1(81.212,-40.631) 81.34,-40.503 81.34,-39.68 MC2.28@81.25,-39.59
  L5-SIG w0.107: v1(44.305,-71.764) 44.438,-71.631 44.438,-71.132 45.222,-70.348 45.222,-69.58 45.664,-69.139 48.158,-69.139 48.743,-68.555 48.743,-67.899 49.518,-67.124 50.305,-67.124 52.892,-64.536 52.892,-56.886 63.083,-46.695 66.593,-46.695 70.947,-42.342 79.893,-42.342 81.34,-40.894 81.34,-40.759 v1(81.212,-40.631)
PORTC_S9_D5P: J4.14 MC2.36 | length 56.5
  L1-TOP w0.107: v1(83.212,-40.631) 83.34,-40.503 83.34,-39.68 MC2.36@83.25,-39.59
  L5-SIG w0.107: v1(44.305,-66.034) 44.438,-66.167 44.438,-66.503 44.742,-66.806 45.555,-66.806 46.076,-66.285 46.076,-58.877 63.586,-41.366 79.284,-41.366 80.467,-40.183 83.188,-40.183 83.34,-40.335 83.34,-40.503 v1(83.212,-40.631)
PORTC_S10_D4N: J4.15 MC2.30 | length 56.9
  L1-TOP w0.107: MC2.30@81.75,-39.59 81.66,-39.68 81.66,-40.503 v1(81.789,-40.631)
  L5-SIG w0.107: v1(44.891,-71.764) 44.758,-71.631 44.758,-71.264 45.542,-70.48 45.542,-69.713 45.796,-69.459 48.291,-69.459 49.063,-68.687 49.063,-68.031 49.65,-67.444 50.438,-67.444 53.212,-64.669 53.212,-57.019 63.216,-47.015 66.726,-47.015 71.079,-42.662 80.025,-42.662 81.66,-41.027 81.66,-40.759 v1(81.789,-40.631)
PORTC_S11_D5N: J4.16 MC2.38 | length 56.5
  L1-TOP w0.107: MC2.38@83.75,-39.59 83.66,-39.68 83.66,-40.503 v1(83.788,-40.631)
  L5-SIG w0.107: v1(44.891,-66.034) 44.758,-66.167 44.758,-66.37 44.874,-66.486 45.422,-66.486 45.756,-66.153 45.756,-58.745 63.454,-41.046 79.151,-41.046 80.335,-39.863 83.321,-39.863 83.66,-40.203 83.66,-40.503 v1(83.788,-40.631)
PORTC_S12_D6P: J4.17 MC2.32 | length 60.8
  L1-TOP w0.107: v1(82.228,-41.58) 82.228,-41.499 82.356,-41.371 82.356,-40.022 82.25,-39.916 MC2.32@82.25,-39.59
  L5-SIG w0.107: v1(45.906,-71.764) 46.039,-71.631 46.039,-71.238 46.692,-70.584 55.963,-70.584 58.115,-68.432 58.115,-53.675 63.672,-48.118 71.323,-48.118 75.016,-44.425 80.721,-44.425 82.228,-42.918 82.228,-42.14 82.356,-42.012 82.356,-41.789 82.251,-41.684 82.228,-41.661 v1(82.228,-41.58) ; v1@82.245,-41.69 v1@82.356,-41.58
PORTC_S13_D7P: J4.18 MC2.40 | length 56
  L1-TOP w0.107: v1(81.763,-37.44) 81.907,-37.584 81.907,-37.935 82.275,-38.303 83.967,-38.303 84.34,-38.676 84.34,-39.027 84.25,-39.117 MC2.40@84.25,-39.59
  L4-SIG w0.107: v1(45.906,-68.236) 46.039,-68.103 46.039,-67.249 46.584,-66.704 46.584,-62.844 63.113,-46.314 70.088,-46.314 74.213,-42.189 76.022,-42.189 79.801,-38.41 81.274,-38.41 81.907,-37.777 81.907,-37.584 v1(81.763,-37.44)
PORTC_S14_D6N: J4.19 MC2.34 | length 60.7
  L1-TOP w0.107: MC2.34@82.75,-39.59 82.75,-40.146 82.676,-40.22 82.676,-41.371 82.804,-41.499 v1(82.804,-41.58)
  L5-SIG w0.107: v1(46.492,-71.764) 46.359,-71.631 46.359,-71.37 46.825,-70.904 56.096,-70.904 58.435,-68.565 58.435,-53.807 63.805,-48.438 71.456,-48.438 75.149,-44.745 80.854,-44.745 82.548,-43.051 82.548,-42.332 82.676,-42.204 82.676,-41.789 82.804,-41.661 v1(82.804,-41.58)
PORTC_S15_D7N: J4.20 MC2.42 | length 56
  L1-TOP w0.107: v1(82.372,-37.435) 82.227,-37.58 82.227,-37.803 82.408,-37.983 84.1,-37.983 84.66,-38.544 84.66,-38.964 84.75,-39.054 MC2.42@84.75,-39.59
  L4-SIG w0.107: v1(46.492,-68.236) 46.359,-68.103 46.359,-67.381 46.904,-66.836 46.904,-62.977 63.246,-46.634 70.221,-46.634 74.346,-42.509 76.155,-42.509 79.934,-38.73 81.407,-38.73 82.227,-37.91 82.227,-37.58 v1(82.372,-37.435)
PORTC_S16: J4.21 MC2.41 | length 61.5
  L1-TOP w0.114: MC2.41@84.75,-33.41 v1(84.75,-32.37)
  L4-SIG w0.117: v1(47.399,-71.764) 47.399,-67.028 48.082,-66.345 48.082,-64.337 64.49,-47.93 72.974,-47.93 80.839,-40.065 81.829,-40.065 84.75,-37.144 v1(84.75,-32.37)
PORTC_S17: J4.22 MC2.39 | length 56.3
  L1-TOP w0.114: MC2.39@84.25,-33.41 v1@84.25,-32.096
  L4-SIG w0.117: v1(47.399,-66.034) 47.399,-63.777 63.805,-47.371 70.637,-47.371 74.676,-43.332 76.327,-43.332 80.289,-39.37 81.407,-39.37 83.82,-36.957 83.82,-35.636 84.328,-35.128 84.328,-33.757 84.176,-33.604 v1(84.176,-32.004)
PORTC_S18: J4.23 MC2.46 | length 56.6
  L1-TOP w0.114: v1(83.007,-42.545) 84.277,-41.275 85.105,-41.275 85.75,-40.629 MC2.46@85.75,-39.59
  L4-SIG w0.117: v1(48.199,-73.967) 48.199,-70.85 48.819,-70.23 48.819,-68.304 49.378,-67.745 49.378,-66.65 49.606,-66.421 49.606,-65.43 56.058,-58.979 60.731,-58.979 69.85,-49.86 74.32,-49.86 80.442,-43.739 81.813,-43.739 v1(83.007,-42.545)
PORTC_S19: J4.24 MC2.44 | length 51.2
  L1-TOP w0.114: v1(81.636,-42.429) 82.002,-42.062 83.033,-42.062 84.176,-40.919 84.768,-40.919 85.25,-40.437 MC2.44@85.25,-39.59
  L4-SIG w0.117: v1(48.199,-68.236) 48.463,-67.972 48.463,-64.973 56.026,-57.41 60.319,-57.41 69.139,-48.59 73.533,-48.59 79.694,-42.429 v1(81.636,-42.429)
PORTC_S20: J4.25 MC2.50 | length 55.5
  L1-TOP w0.114: MC2.50@86.75,-39.59 v1(86.75,-38.55)
  L4-SIG w0.117: v1(48.999,-71.764) 48.999,-71.118 49.924,-70.193 49.924,-69.736 50.648,-69.012 50.648,-68.478 57.633,-61.493 67.147,-61.493 84.774,-43.866 84.774,-42.251 85.801,-41.224 85.801,-39.499 v1(86.75,-38.55)
PORTC_S21: J4.26 MC2.48 | length 52
  L1-TOP w0.114: v1(85.141,-37.897) 85.547,-38.303 85.903,-38.303 86.25,-38.651 MC2.48@86.25,-39.59
  L4-SIG w0.117: v1(48.999,-66.034) 48.999,-65.301 56.115,-58.185 60.611,-58.185 69.571,-49.225 73.99,-49.225 80.162,-43.053 81.788,-43.053 82.207,-42.634 82.207,-42.329 81.789,-41.911 81.789,-41.351 84.353,-38.786 84.353,-38.684 v1(85.141,-37.897)
PORTC_S22: J4.27 MC2.53 | length 65.2
  L1-TOP w0.114: v1(87.13,-35.262) 87.75,-34.641 MC2.53@87.75,-33.41
  L4-SIG w0.117: v1(49.799,-73.967) 51.232,-72.534 51.232,-70.383 51.359,-70.256 51.359,-69.19 53.899,-66.65 55.601,-66.65 59.141,-63.109 71.664,-63.109 80.342,-54.43 80.342,-51.255 85.547,-46.05 85.547,-42.792 86.716,-41.624 86.716,-40.691 87.478,-39.929 87.478,-37.886 86.716,-37.124 86.716,-35.676 v1(87.13,-35.262)
PORTC_S23: J4.28 MC2.43 | length 56
  L1-TOP w0.114: v1(85.25,-34.449) MC2.43@85.25,-33.41
  L4-SIG w0.117: v1(49.799,-68.236) 49.799,-67.18 50.005,-66.974 50.005,-65.921 56.261,-59.665 61.036,-59.665 70.129,-50.571 74.701,-50.571 81.051,-44.221 82.193,-44.221 83.533,-42.882 83.533,-41.695 84.836,-40.392 84.836,-38.887 85.623,-38.1 85.623,-34.822 v1(85.25,-34.449)
PORTC_S24: J4.29 MC2.49 | length 62.7
  L1-TOP w0.114: v1(86.038,-34.677) 86.317,-34.677 86.75,-34.244 MC2.49@86.75,-33.41
  L4-SIG w0.117: v1(50.599,-71.764) 50.599,-71.041 50.419,-70.861 50.419,-69.723 50.978,-69.164 50.978,-68.783 57.125,-62.636 71.018,-62.636 79.883,-53.772 79.883,-51.029 85.141,-45.771 85.141,-42.596 86.289,-41.448 86.289,-40.026 87.147,-39.167 87.147,-37.948 86.038,-36.838 v1(86.038,-34.677)
PORTC_S25: J4.30 MC2.52 | length 51.7
  L1-TOP w0.114: v1(86.258,-37.948) 87.026,-37.948 87.25,-38.172 MC2.52@87.25,-39.59
  L4-SIG w0.117: v1(50.599,-66.034) 51.467,-66.034 57.252,-60.249 65.912,-60.249 81.406,-44.755 82.489,-44.755 83.8,-43.444 83.8,-42.006 84.15,-41.656 84.404,-41.656 85.369,-40.691 85.369,-38.837 v1(86.258,-37.948)
PORTC_S26: J4.31 MC2.51 | length 64.5
  L1-TOP w0.114: v1(87.13,-34.462) 87.13,-34.165 87.25,-34.045 MC2.51@87.25,-33.41
  L4-SIG w0.117: v1(51.399,-73.967) 51.399,-73.491 51.707,-73.184 51.707,-69.477 53.594,-67.589 55.372,-67.589 59.436,-63.525 72.263,-63.525 81.077,-54.712 81.077,-51.13 85.903,-46.304 85.903,-43.028 87.757,-41.173 87.757,-35.089 v1(87.13,-34.462)
PORTC_S27: J4.32 MC2.54 | length 55.3
  L1-TOP w0.114: v1(49.886,-69.113) 50.838,-69.113 51.399,-68.552 J4.32@51.399,-67.135 ; v1(84.303,-42.139) 86.441,-42.139 87.75,-40.829 MC2.54@87.75,-39.59
  L4-SIG w0.117: v1(49.886,-69.113) 50.292,-68.707 50.292,-68.148 57.531,-60.909 66.548,-60.909 82.093,-45.364 82.779,-45.364 84.303,-43.84 v1(84.303,-42.139)
PORTD_C2P_CLKN: J5.36 MC2.110 | length 29.7
  L1-TOP w0.107: MC2.110@106.75,-39.59 106.66,-39.68 106.66,-40.503 v1(106.788,-40.631)
  L4-SIG w0.107: v1(99.892,-66.034) 99.759,-65.901 99.759,-65.463 103.444,-61.778 103.444,-55.792 103.157,-55.505 103.157,-48.901 106.66,-45.397 106.66,-40.759 v1(106.788,-40.631)
PORTD_C2P_CLKP: J5.34 MC2.108 | length 29.7
  L1-TOP w0.107: v1(106.212,-40.631) 106.34,-40.503 106.34,-39.68 MC2.108@106.25,-39.59
  L4-SIG w0.107: v1(99.306,-66.034) 99.439,-65.901 99.439,-65.33 103.124,-61.646 103.124,-55.924 102.837,-55.637 102.837,-48.768 106.34,-45.265 106.34,-40.759 v1(106.212,-40.631)
PORTD_P2C_CLKN: J5.35 MC2.89 | length 55
  L1-TOP w0.107: MC2.89@101.75,-33.41 101.66,-33.32 101.66,-32.496 v1(101.789,-32.368)
  L4-SIG w0.107: v1(99.892,-71.764) 99.759,-71.631 99.759,-71.457 100.064,-71.153 103.167,-71.153 111.168,-63.152 111.168,-45.593 110.912,-45.336 110.912,-35.372 108.722,-33.183 102.04,-33.183 101.66,-32.803 101.66,-32.496 v1(101.789,-32.368)
PORTD_P2C_CLKP: J5.33 MC2.87 | length 55
  L1-TOP w0.107: v1(101.212,-32.368) 101.34,-32.496 101.34,-33.32 MC2.87@101.25,-33.41
  L4-SIG w0.107: v1(99.306,-71.764) 99.439,-71.631 99.439,-71.325 99.931,-70.833 103.035,-70.833 110.848,-63.019 110.848,-45.726 110.592,-45.469 110.592,-35.505 108.59,-33.503 101.908,-33.503 101.34,-32.935 101.34,-32.496 v1(101.212,-32.368)
PORTD_S0_D0P: J5.5 MC2.83 | length 44.8
  L1-TOP w0.107: v1(100.212,-34.451) 100.34,-34.323 100.34,-33.5 MC2.83@100.25,-33.41
  L4-SIG w0.107: v1(88.105,-71.764) 88.238,-71.631 88.238,-71.115 87.904,-70.781 87.904,-63.256 88.021,-63.139 88.021,-55.239 88.854,-54.407 88.854,-49.276 88.936,-49.194 88.936,-44.553 96.42,-37.069 96.952,-37.069 98.715,-35.306 99.873,-35.306 100.34,-34.838 100.34,-34.579 v1(100.212,-34.451)
PORTD_S1_D1P: J5.6 MC2.79 | length 43.6
  L1-TOP w0.107: v1(86.942,-62.636) 86.942,-62.716 87.075,-62.849 87.075,-63.265 87.325,-63.515 87.777,-63.515 88.24,-63.978 88.24,-65.989 87.998,-66.231 J5.6@87.998,-67.135 ; v1(99.212,-32.368) 99.34,-32.496 99.34,-33.32 MC2.79@99.25,-33.41
  L4-SIG w0.107: v1(86.942,-62.636) 86.942,-62.557 87.075,-62.424 87.075,-54.86 87.808,-54.127 87.808,-48.798 88.097,-48.508 88.097,-44.186 95.362,-36.921 95.362,-33.903 95.879,-33.386 98.67,-33.386 99.34,-32.715 99.34,-32.496 v1(99.212,-32.368)
PORTD_S2_D0N: J5.7 MC2.85 | length 44.8
  L1-TOP w0.107: MC2.85@100.75,-33.41 100.66,-33.5 100.66,-34.323 v1(100.788,-34.451)
  L4-SIG w0.107: v1(88.691,-71.764) 88.558,-71.631 88.558,-70.982 88.224,-70.648 88.224,-63.388 88.341,-63.271 88.341,-55.372 89.174,-54.539 89.174,-49.409 89.256,-49.327 89.256,-44.686 96.552,-37.389 97.084,-37.389 98.847,-35.626 100.005,-35.626 100.66,-34.971 100.66,-34.579 v1(100.788,-34.451)
PORTD_S3_D1N: J5.8 MC2.81 | length 43.6
  L1-TOP w0.107: v1(87.528,-62.636) 87.528,-62.716 87.395,-62.849 87.395,-63.133 87.458,-63.195 87.909,-63.195 88.56,-63.845 88.56,-65.989 88.798,-66.228 J5.8@88.798,-67.135 ; MC2.81@99.75,-33.41 99.66,-33.32 99.66,-32.496 v1(99.789,-32.368)
  L4-SIG w0.107: v1(87.528,-62.636) 87.528,-62.557 87.395,-62.424 87.395,-54.992 88.128,-54.26 88.128,-48.931 88.417,-48.641 88.417,-44.318 95.682,-37.054 95.682,-34.036 96.012,-33.706 98.802,-33.706 99.66,-32.848 99.66,-32.496 v1(99.789,-32.368)
PORTD_S4_D2P: J5.9 MC2.80 | length 43.1
  L1-TOP w0.107: v1(99.212,-38.548) 99.34,-38.676 99.34,-39.5 MC2.80@99.25,-39.59
  L4-SIG w0.107: v1(89.705,-73.967) 89.838,-73.834 89.838,-72.143 89.276,-71.581 89.276,-69.333 88.793,-68.851 88.793,-65.308 88.936,-65.166 88.936,-55.951 89.799,-55.087 89.799,-45.6 96.136,-39.262 99.016,-39.262 99.34,-38.938 99.34,-38.676 v1(99.212,-38.548)
PORTD_S5_D3P: J5.10 MC2.91 | length 41.6
  L1-TOP w0.107: v1(101.798,-34.948) 102.078,-34.948 102.34,-34.686 102.34,-34.089 102.25,-33.999 MC2.91@102.25,-33.41
  L4-SIG w0.107: v1(89.705,-68.236) 89.838,-68.103 89.838,-56.623 90.523,-55.938 90.523,-46.564 97.167,-39.92 99.525,-39.92 100.232,-39.214 100.232,-37.765 101.439,-36.557 101.439,-35.587 101.798,-35.228 v1(101.798,-34.948)
PORTD_S6_D2N: J5.11 MC2.82 | length 43.1
  L1-TOP w0.107: MC2.82@99.75,-39.59 99.66,-39.5 99.66,-38.676 v1(99.789,-38.548)
  L4-SIG w0.107: v1(90.291,-73.967) 90.158,-73.834 90.158,-72.011 89.596,-71.448 89.596,-69.201 89.113,-68.718 89.113,-65.441 89.256,-65.299 89.256,-56.083 90.119,-55.22 90.119,-45.732 96.269,-39.582 99.149,-39.582 99.66,-39.071 99.66,-38.676 v1(99.789,-38.548)
PORTD_S7_D3N: J5.12 MC2.93 | length 41.6
  L1-TOP w0.107: v1(102.319,-35.439) 102.319,-35.16 102.66,-34.819 102.66,-33.955 102.75,-33.865 MC2.93@102.75,-33.41
  L4-SIG w0.107: v1(90.291,-68.236) 90.158,-68.103 90.158,-56.755 90.843,-56.07 90.843,-46.697 97.3,-40.24 99.658,-40.24 100.552,-39.346 100.552,-37.897 101.759,-36.69 101.759,-35.719 102.039,-35.439 v1(102.319,-35.439)
PORTD_S8_D4P: J5.13 MC2.88 | length 40.1
  L1-TOP w0.107: v1(101.212,-38.548) 101.34,-38.676 101.34,-39.5 MC2.88@101.25,-39.59
  L4-SIG w0.107: v1(91.305,-71.764) 91.438,-71.631 91.438,-71.12 90.838,-70.519 90.838,-65.656 91.806,-64.688 91.806,-58.059 92.014,-57.851 92.014,-48.508 97.74,-42.783 99.534,-42.783 101.34,-40.976 101.34,-38.676 v1(101.212,-38.548)
PORTD_S9_D5P: J5.14 MC2.84 | length 33.5
  L1-TOP w0.107: v1(90.752,-64.313) 90.752,-64.392 90.885,-64.525 90.885,-65.062 91.427,-65.604 91.427,-65.989 91.198,-66.218 J5.14@91.198,-67.135 ; v1(100.212,-40.631) 100.34,-40.503 100.34,-39.68 MC2.84@100.25,-39.59
  L4-SIG w0.107: v1(90.752,-64.313) 90.752,-64.233 90.885,-64.1 90.885,-57.502 91.262,-57.125 91.262,-47.495 96.99,-41.767 99.449,-41.767 100.34,-40.876 100.34,-40.759 v1(100.212,-40.631)
PORTD_S10_D4N: J5.15 MC2.90 | length 40.1
  L1-TOP w0.107: MC2.90@101.75,-39.59 101.66,-39.5 101.66,-38.676 v1(101.789,-38.548)
  L4-SIG w0.107: v1(91.891,-71.764) 91.758,-71.631 91.758,-70.987 91.158,-70.387 91.158,-65.788 92.126,-64.821 92.126,-58.191 92.334,-57.983 92.334,-48.641 97.872,-43.103 99.666,-43.103 101.66,-41.108 101.66,-38.676 v1(101.789,-38.548)
PORTD_S11_D5N: J5.16 MC2.86 | length 33.5
  L1-TOP w0.107: v1(91.338,-64.313) 91.338,-64.392 91.205,-64.525 91.205,-64.929 91.747,-65.471 91.747,-65.989 91.998,-66.24 J5.16@91.998,-67.135 ; MC2.86@100.75,-39.59 100.66,-39.68 100.66,-40.503 v1(100.788,-40.631)
  L4-SIG w0.107: v1(91.338,-64.313) 91.338,-64.233 91.205,-64.1 91.205,-57.634 91.583,-57.257 91.583,-47.627 97.123,-42.087 99.582,-42.087 100.66,-41.008 100.66,-40.759 v1(100.788,-40.631)
PORTD_S12_D6P: J5.17 MC2.92 | length 39.9
  L1-TOP w0.107: v1(102.212,-40.631) 102.34,-40.503 102.34,-39.68 MC2.92@102.25,-39.59
  L4-SIG w0.107: v1(92.906,-73.967) 93.039,-73.834 93.039,-71.559 92.184,-70.705 92.184,-65.885 92.741,-65.328 92.741,-49.499 94.037,-48.203 95.358,-48.203 102.34,-41.22 102.34,-40.759 v1(102.212,-40.631)
PORTD_S13_D7P: J5.18 MC2.95 | length 40
  L1-TOP w0.107: v1(103.212,-34.451) 103.34,-34.323 103.34,-33.5 MC2.95@103.25,-33.41
  L4-SIG w0.107: v1(92.906,-68.236) 93.039,-68.103 93.039,-67.612 93.571,-67.08 93.571,-63.477 94.849,-62.199 94.849,-49.942 103.2,-41.591 103.2,-40.077 102.347,-39.223 102.347,-36.128 103.34,-35.135 103.34,-34.579 v1(103.212,-34.451)
PORTD_S14_D6N: J5.19 MC2.94 | length 39.9
  L1-TOP w0.107: MC2.94@102.75,-39.59 102.66,-39.68 102.66,-40.503 v1(102.788,-40.631)
  L4-SIG w0.107: v1(93.492,-73.967) 93.359,-73.834 93.359,-71.426 92.504,-70.572 92.504,-66.017 93.061,-65.461 93.061,-49.632 94.17,-48.523 95.49,-48.523 102.66,-41.353 102.66,-40.759 v1(102.788,-40.631)
PORTD_S15_D7N: J5.20 MC2.97 | length 40
  L1-TOP w0.107: MC2.97@103.75,-33.41 103.66,-33.5 103.66,-34.323 v1(103.788,-34.451)
  L4-SIG w0.107: v1(93.492,-68.236) 93.359,-68.103 93.359,-67.745 93.891,-67.212 93.891,-63.61 95.169,-62.332 95.169,-50.075 103.52,-41.724 103.52,-39.944 102.667,-39.091 102.667,-36.261 103.66,-35.267 103.66,-34.579 v1(103.788,-34.451)
PORTD_S16: J5.21 MC2.98 | length 39
  L1-TOP w0.114: MC2.98@103.75,-39.59 v1(103.75,-38.55)
  L4-SIG w0.117: v1(94.399,-71.764) 94.399,-66.76 94.905,-66.254 94.905,-64.074 97.663,-61.316 97.663,-55.735 97.122,-55.194 97.122,-49.809 104.212,-42.719 104.212,-39.012 v1(103.75,-38.55)
PORTD_S17: J5.22 MC2.96 | length 33.8
  L1-TOP w0.114: MC2.96@103.25,-39.59 103.25,-38.276 v1(103.433,-38.093)
  L4-SIG w0.117: v1(94.399,-66.034) 94.399,-63.996 96.418,-61.976 96.418,-58.242 96.622,-58.039 96.622,-55.441 96.868,-55.194 96.868,-49.346 103.886,-42.328 103.886,-39.548 103.212,-38.874 103.212,-38.314 v1(103.433,-38.093)
PORTD_S18: J5.23 MC2.102 | length 38.7
  L1-TOP w0.114: MC2.102@104.75,-39.59 104.75,-40.615 v1(104.978,-40.843)
  L4-SIG w0.117: v1(95.199,-73.967) 95.199,-70.527 95.679,-70.047 95.679,-66.783 95.552,-66.656 95.552,-65.842 99.129,-62.265 99.129,-49.614 105.08,-43.663 105.08,-40.945 v1(104.978,-40.843)
PORTD_S19: J5.24 MC2.100 | length 32.7
  L1-TOP w0.114: MC2.100@104.25,-39.59 104.25,-41.106 v1(104.673,-41.529)
  L4-SIG w0.117: v1(95.199,-68.236) 95.199,-65.024 98.37,-61.853 98.37,-55.597 98.875,-55.093 98.875,-49.157 104.673,-43.358 v1(104.673,-41.529)
PORTD_S20: J5.25 MC2.105 | length 45.5
  L1-TOP w0.114: v1(105.735,-35.516) 106.116,-35.135 106.116,-34.436 105.75,-34.07 MC2.105@105.75,-33.41
  L4-SIG w0.117: v1(95.999,-71.764) 95.999,-71.246 98.494,-68.752 98.57,-68.752 99.18,-68.141 99.854,-68.141 101.295,-66.7 101.879,-66.7 106.147,-62.433 106.147,-55.872 106.876,-55.143 106.876,-49.106 108.212,-47.769 108.212,-38.159 105.735,-35.682 v1(105.735,-35.516)
PORTD_S21: J5.26 MC2.99 | length 37.3
  L1-TOP w0.114: MC2.99@104.25,-33.41 104.25,-35.052 v1(104.6,-35.401)
  L4-SIG w0.117: v1(95.999,-66.034) 100.597,-61.436 100.597,-55.504 100.856,-55.245 100.856,-48.965 105.461,-44.36 105.461,-39.548 104.343,-38.43 104.343,-35.658 v1(104.6,-35.401)
PORTD_S22: J5.27 MC2.107 | length 49.3
  L1-TOP w0.114: MC2.107@106.25,-33.41 106.25,-34.215 106.37,-34.335 106.37,-34.69 v1(106.84,-35.16)
  L4-SIG w0.117: v1(96.799,-73.967) 98.163,-72.602 98.163,-71.368 98.882,-70.649 98.882,-69.672 99.543,-69.012 102.387,-69.012 103.086,-68.313 103.086,-67.132 108.166,-62.052 108.166,-56.035 108.88,-55.321 108.88,-49.088 109.449,-48.519 109.449,-40.005 109.677,-39.776 109.677,-37.414 107.423,-35.16 v1(106.84,-35.16)
PORTD_S23: J5.28 MC2.106 | length 36.7
  L1-TOP w0.114: MC2.106@105.75,-39.59 v1(105.75,-38.55)
  L4-SIG w0.117: v1(96.799,-68.236) 98.201,-66.834 99.674,-66.834 104.178,-62.331 104.178,-55.796 104.856,-55.118 104.856,-48.382 107.391,-45.847 107.391,-40.191 v1(105.75,-38.55)
PORTD_S24: J5.29 MC2.103 | length 46.2
  L1-TOP w0.114: MC2.103@105.25,-33.41 105.25,-34.256 v1(105.71,-34.716)
  L4-SIG w0.117: v1(97.599,-71.764) 97.599,-70.891 98.284,-70.206 98.284,-69.635 99.289,-68.631 101.854,-68.631 102.514,-67.97 102.514,-66.713 107.155,-62.072 107.155,-49.632 108.788,-47.998 108.788,-37.313 107.226,-35.751 106.745,-35.751 v1(105.71,-34.716)
PORTD_S25: J5.30 MC2.101 | length 36.7
  L1-TOP w0.114: v1(104.745,-34.563) 104.75,-34.558 MC2.101@104.75,-33.41
  L4-SIG w0.117: v1(97.599,-66.034) 101.148,-62.485 101.148,-49.347 105.816,-44.679 105.816,-39.522 104.724,-38.43 104.724,-36.093 105.054,-35.763 105.054,-34.873 v1(104.745,-34.563)
PORTD_S26: J5.31 MC2.109 | length 49.1
  L1-TOP w0.114: MC2.109@106.75,-33.41 106.75,-34.397 v1(106.84,-34.487)
  L4-SIG w0.117: v1(98.399,-73.967) 98.399,-73.189 98.684,-72.904 98.684,-71.52 100.71,-69.494 103.188,-69.494 109.124,-63.558 109.124,-49.657 109.957,-48.824 109.957,-35.992 109.1,-35.135 107.957,-35.135 107.309,-34.487 v1(106.84,-34.487)
PORTD_S27: J5.32 MC2.104 | length 37.6
  L1-TOP w0.114: MC2.104@105.25,-39.59 105.25,-38.276 v1(105.433,-38.093)
  L4-SIG w0.117: v1(98.399,-68.236) 98.399,-67.867 98.905,-67.361 99.822,-67.361 105.148,-62.034 105.148,-49.106 107.848,-46.406 107.848,-39.827 106.114,-38.093 v1(105.433,-38.093)
PORTE_C2P_CLKN: J8.36 MC2.156 | length 46.8
  L1-TOP w0.107: MC2.156@123.25,-39.59 123.16,-39.68 123.16,-40.503 v1(123.288,-40.631)
  L4-SIG w0.107: v1(123.288,-40.631) 123.288,-40.94 127.154,-44.806 131.593,-44.806 137.801,-51.013 142.296,-51.013 153.634,-62.351 153.634,-67.087 153.16,-67.562 153.16,-68.18 v1(153.263,-68.283)
PORTE_C2P_CLKP: J8.34 MC2.154 | length 46.9
  L1-TOP w0.107: v1(122.712,-40.631) 122.84,-40.503 122.84,-39.68 MC2.154@122.75,-39.59
  L4-SIG w0.107: v1(122.712,-40.631) 122.936,-40.855 122.936,-41.04 127.021,-45.126 131.46,-45.126 137.668,-51.333 142.164,-51.333 153.314,-62.484 153.314,-66.954 152.84,-67.429 152.84,-68.18 v1(152.737,-68.283)
PORTE_P2C_CLKN: J8.35 MC2.150 | length 52.6
  L1-TOP w0.107: MC2.150@121.75,-39.59 121.66,-39.5 121.66,-38.676 v1(121.789,-38.548)
  L4-SIG w0.107: v1(121.789,-38.548) 121.66,-38.676 121.66,-40.715 127.031,-46.086 131.324,-46.086 137.369,-52.131 141.433,-52.131 152.593,-63.291 152.593,-66.304 152.255,-66.642 152.255,-68.644 152.773,-69.163 152.773,-70.393 153.16,-70.779 153.16,-71.615 v1(153.263,-71.718)
PORTE_P2C_CLKP: J8.33 MC2.148 | length 52.6
  L1-TOP w0.107: v1(121.212,-38.548) 121.34,-38.676 121.34,-39.5 MC2.148@121.25,-39.59
  L4-SIG w0.107: v1(121.212,-38.548) 121.34,-38.676 121.34,-40.848 126.898,-46.406 131.191,-46.406 137.236,-52.451 141.3,-52.451 152.273,-63.424 152.273,-66.172 151.935,-66.509 151.935,-68.777 152.453,-69.295 152.453,-70.525 152.84,-70.912 152.84,-71.615 v1(152.737,-71.718)
PORTE_REFCLKN: J8.15 MC3.87 | length 97
  L5-SIG w0.107: v1@142.811,-14.762 v1(142.836,-14.788) 142.755,-14.788 142.627,-14.66 142.361,-14.66 142.022,-14.32 142.022,-11.221 142.834,-10.408 142.834,-7.686 143.487,-7.033 143.487,-5.99 143.228,-5.73 142.174,-5.73 141.818,-6.086 140.622,-6.086 140.496,-6.086 140.442,-6.14 140.442,-6.36 140.388,-6.414 140.136,-6.414 140.081,-6.36 140.081,-6.14 140.027,-6.086 139.728,-6.086 137.637,-6.086 137.139,-5.588 136.017,-5.588 135.103,-6.502 133.904,-6.502 128.727,-11.679 128.727,-33.71 130.2,-35.184 130.2,-38.511 133.203,-41.514 133.838,-41.514 143.256,-50.932 143.256,-53.751 146.693,-57.188 146.693,-66.515 145.186,-68.021 145.186,-70.54 145.66,-71.014 145.66,-71.47 ccw(c146.01,-71.47) v1(145.763,-71.718)
PORTE_REFCLKP: J8.13 MC3.85 | length 97
  L5-SIG w0.107: v1@142.811,-14.237 v1(142.836,-14.211) 142.755,-14.211 142.627,-14.34 142.494,-14.34 142.342,-14.187 142.342,-11.354 143.154,-10.541 143.154,-7.819 143.807,-7.166 143.807,-5.857 143.36,-5.41 142.041,-5.41 141.686,-5.766 137.77,-5.766 137.272,-5.268 135.884,-5.268 134.97,-6.182 133.772,-6.182 128.407,-11.547 128.407,-33.843 129.88,-35.316 129.88,-38.644 133.071,-41.834 133.706,-41.834 142.936,-51.064 142.936,-53.884 146.373,-57.32 146.373,-66.382 144.866,-67.889 144.866,-70.673 145.34,-71.146 145.34,-71.47 cw(c144.989,-71.47) v1(145.237,-71.718)
PORTE_RX0N: J8.7 MC3.71 | length 100.1
  L5-SIG w0.107: v1(142.763,-71.718) 142.66,-71.615 142.66,-70.766 142.017,-70.124 141.596,-69.702 141.596,-65.933 136.185,-60.522 136.185,-51.988 131.12,-46.924 127.31,-46.924 120.726,-40.34 120.726,-37.998 121.783,-36.942 121.783,-33.223 122.123,-32.883 122.123,-25.603 123.419,-24.308 123.419,-7.925 130.124,-1.219 131.013,-1.219 131.051,-1.219 131.358,-1.219 131.412,-1.273 131.412,-1.494 131.466,-1.548 131.719,-1.548 131.773,-1.494 131.773,-1.273 131.827,-1.219 131.953,-1.219 135.691,-1.219 136.682,-2.21 139.781,-2.21 141.231,-3.66 142.627,-3.66 142.755,-3.788 v1(142.836,-3.788)
PORTE_RX0P: J8.5 MC3.69 | length 100.1
  L5-SIG w0.107: v1(142.237,-71.718) 142.34,-71.615 142.34,-70.899 142.225,-70.784 141.276,-69.835 141.276,-66.065 135.865,-60.654 135.865,-52.121 130.988,-47.244 127.178,-47.244 120.406,-40.472 120.406,-37.866 121.463,-36.809 121.463,-33.091 121.803,-32.75 121.803,-25.471 123.099,-24.175 123.099,-7.792 129.992,-0.899 135.824,-0.899 136.815,-1.89 139.913,-1.89 141.363,-3.34 142.627,-3.34 142.755,-3.212 v1(142.836,-3.212)
PORTE_RX1N: J8.11 MC3.75 | length 91.1
  L5-SIG w0.107: v1(141.344,-5.288) 141.263,-5.288 141.135,-5.16 140.622,-5.16 139.247,-3.785 138.074,-3.785 137.262,-4.597 135.788,-4.597 135.306,-4.115 131.674,-4.115 129.845,-5.944 129.756,-6.033 129.756,-6.109 129.911,-6.265 129.911,-6.342 129.733,-6.52 129.656,-6.52 129.5,-6.364 129.424,-6.364 129.21,-6.579 126.162,-9.627 126.162,-25.38 124.866,-26.676 124.866,-33.304 126.06,-34.498 126.06,-39.019 131.311,-44.27 132.276,-44.27 139.446,-51.44 139.446,-53.225 143.822,-57.602 143.822,-66.476 142.974,-67.325 142.974,-68.634 143.703,-69.363 143.703,-70.454 144.16,-70.911 144.16,-71.615 v1(144.263,-71.718)
PORTE_RX1P: J8.9 MC3.73 | length 91.1
  L5-SIG w0.107: v1(141.344,-4.712) 141.263,-4.712 141.135,-4.84 140.755,-4.84 139.38,-3.465 137.942,-3.465 137.129,-4.277 135.921,-4.277 135.438,-3.795 131.541,-3.795 125.842,-9.494 125.842,-25.248 124.546,-26.543 124.546,-33.437 125.74,-34.63 125.74,-39.152 131.178,-44.59 132.144,-44.59 139.126,-51.572 139.126,-53.358 143.502,-57.734 143.502,-66.343 142.654,-67.192 142.654,-68.766 143.383,-69.496 143.383,-70.587 143.84,-71.044 143.84,-71.615 v1(143.737,-71.718)
PORTE_RX2N: J8.31 MC3.83 | length 80.6
  L5-SIG w0.107: v1(141.344,-13.288) 141.263,-13.288 141.135,-13.16 136.583,-13.16 133.604,-16.139 133.604,-18.42 134.087,-18.902 134.087,-19.787 134.087,-19.957 134.16,-20.03 134.364,-20.03 134.437,-20.104 134.437,-20.445 134.364,-20.518 134.16,-20.518 134.087,-20.591 134.087,-20.726 134.087,-28.641 136.58,-31.134 144.977,-31.134 154.127,-40.284 154.127,-46.69 154.879,-47.442 154.879,-64.496 154.066,-65.309 154.066,-68.84 153.64,-69.266 153.111,-69.266 152.756,-69.621 152.756,-70.227 151.66,-71.323 151.66,-71.534 151.763,-71.637 v1(151.763,-71.718)
PORTE_RX2P: J8.29 MC3.81 | length 80.6
  L5-SIG w0.107: v1(141.344,-12.711) 141.263,-12.711 141.135,-12.84 136.451,-12.84 133.284,-16.006 133.284,-18.552 133.767,-19.035 133.767,-27.234 133.767,-28.773 135.804,-30.81 136.447,-31.454 144.844,-31.454 153.807,-40.417 153.807,-46.822 154.559,-47.574 154.559,-64.364 153.746,-65.176 153.746,-68.707 153.507,-68.946 152.979,-68.946 152.436,-69.489 152.436,-70.095 151.34,-71.191 151.34,-71.534 151.237,-71.637 v1(151.237,-71.718)
PORTE_RX3N: J8.27 MC3.79 | length 82.3
  L5-SIG w0.107: v1(142.836,-6.788) 142.755,-6.788 142.627,-6.66 142.51,-6.66 140.508,-8.661 136.246,-8.661 131.445,-13.462 131.445,-17.196 131.445,-17.366 131.518,-17.44 131.723,-17.44 131.796,-17.513 131.796,-17.854 131.723,-17.927 131.518,-17.927 131.445,-18 131.445,-18.212 131.445,-30.18 133.96,-32.694 133.96,-37.241 151.434,-54.715 151.434,-63.919 150.825,-64.527 150.825,-66.984 151.257,-67.416 151.257,-70.124 150.16,-71.222 150.16,-71.534 150.263,-71.637 v1(150.263,-71.718)
PORTE_RX3P: J8.25 MC3.77 | length 82.3
  L5-SIG w0.107: v1(142.836,-6.212) 142.755,-6.212 142.627,-6.34 142.377,-6.34 140.376,-8.341 136.113,-8.341 131.125,-13.329 131.125,-30.312 133.64,-32.827 133.64,-37.374 151.113,-54.847 151.113,-63.786 150.505,-64.395 150.505,-67.117 150.937,-67.549 150.937,-69.992 149.84,-71.089 149.84,-71.534 149.737,-71.637 v1(149.737,-71.718)
PORTE_S0: J8.14 MC2.137 | length 58.1
  L1-TOP w0.114: v1(118.75,-34.449) MC2.137@118.75,-33.41
  L4-SIG w0.117: v1(118.75,-34.449) 117.214,-34.449 114.757,-36.906 114.757,-47.549 117.018,-49.809 117.018,-55.448 127.025,-65.456 144.715,-65.456 v1(145.237,-65.978) ; v1@118.75,-34.394 118.768,-34.394 v1@118.77,-34.392
PORTE_S1: J8.16 MC2.143 | length 58.2
  L1-TOP w0.114: v1(120.25,-34.449) MC2.143@120.25,-33.41
  L4-SIG w0.117: v1(120.25,-34.449) 119.793,-34.907 117.468,-34.907 115.316,-37.059 115.316,-46.177 119.024,-49.886 119.024,-55.347 127.356,-63.678 143.764,-63.678 145.763,-65.676 v1(145.763,-65.978)
PORTE_S2: J8.17 MC2.140 | length 54.6
  L1-TOP w0.114: v1(119.25,-40.629) MC2.140@119.25,-39.59
  L4-SIG w0.117: v1(119.25,-40.629) 119.25,-43.558 123.419,-47.727 125.476,-47.727 127.203,-49.454 128.6,-49.454 129.057,-49.911 129.057,-55.118 131.928,-57.988 142.926,-57.988 149.301,-64.364 149.301,-66.37 148.184,-67.488 148.184,-68.148 147.549,-68.783 147.422,-68.783 146.279,-69.926 146.279,-70.409 146.737,-70.867 v1(146.737,-71.718)
PORTE_S3: J8.18 MC2.145 | length 59.5
  L1-TOP w0.114: v1(120.567,-34.907) 120.75,-34.724 MC2.145@120.75,-33.41
  L4-SIG w0.117: v1(120.567,-34.907) 120.092,-35.382 118.466,-35.382 115.875,-37.973 115.875,-44.729 121.006,-49.86 121.006,-55.163 127.819,-61.976 142.988,-61.976 146.737,-65.725 v1(146.737,-68.283)
PORTE_S4: J8.19 MC2.138 | length 57.5
  L1-TOP w0.114: MC2.138@118.75,-39.59 v1(118.75,-38.55)
  L4-SIG w0.117: v1(118.75,-38.55) 118.715,-38.585 118.715,-38.816 117.653,-39.878 117.653,-40.792 118.034,-41.173 118.516,-41.173 118.77,-40.919 118.77,-40.386 118.999,-40.157 119.558,-40.157 119.99,-40.589 119.99,-42.824 124.384,-47.219 125.552,-47.219 127.102,-48.768 129.87,-48.768 130.962,-49.86 130.962,-50.978 131.496,-51.511 132.486,-51.511 136.703,-55.728 141.529,-55.728 149.885,-64.084 149.885,-66.675 148.641,-67.92 148.641,-68.783 147.599,-69.825 147.599,-71.381 v1(147.263,-71.718)
PORTE_S5: J8.20 MC2.147 | length 61.9
  L1-TOP w0.114: v1(121.212,-32.368) 121.34,-32.496 121.34,-33.32 MC2.147@121.25,-33.41
  L4-SIG w0.117: v1(121.212,-32.368) 121.212,-35.277 119.405,-37.084 117.729,-37.084 116.307,-38.506 116.307,-44.272 121.285,-49.251 122.225,-49.251 122.987,-50.013 122.987,-55.397 128.524,-60.935 142.977,-60.935 147.263,-65.221 v1(147.263,-68.283)
PORTE_S6: J8.21 MC2.136 | length 53.7
  L1-TOP w0.114: v1(118.25,-40.629) MC2.136@118.25,-39.59
  L4-SIG w0.117: v1(118.25,-40.629) 118.25,-40.068 118.567,-39.751 119.99,-39.751 120.396,-40.157 120.396,-41.986 125.044,-46.634 125.552,-46.634 126.873,-47.955 130.912,-47.955 137.312,-54.356 141.021,-54.356 150.343,-63.678 150.343,-66.954 149.047,-68.25 149.047,-69.24 148.237,-70.05 v1(148.237,-71.718)
PORTE_S7: J8.22 MC2.142 | length 54.2
  L1-TOP w0.114: MC2.142@119.75,-39.59 v1(119.75,-38.55)
  L4-SIG w0.117: v1(119.75,-38.55) 119.75,-37.937 119.456,-37.643 118.135,-37.643 116.789,-38.989 116.789,-43.79 121.717,-48.717 123.571,-48.717 125,-50.146 125,-55.372 129.216,-59.588 142.57,-59.588 148.237,-65.255 v1(148.237,-65.978)
PORTE_S8: J8.23 MC2.153 | length 59.2
  L1-TOP w0.114: MC2.153@122.75,-33.41 v1(122.75,-32.37)
  L4-SIG w0.117: v1(122.75,-32.37) 122.75,-35.238 122.606,-35.382 122.606,-36.551 120.726,-38.43 120.726,-41.097 126.898,-47.269 131.013,-47.269 137.185,-53.442 141.046,-53.442 150.8,-63.195 150.8,-68.885 149.581,-70.104 149.581,-70.9 v1(148.763,-71.718)
PORTE_S9: J8.24 MC2.151 | length 59.1
  L1-TOP w0.114: v1(122.25,-34.449) MC2.151@122.25,-33.41
  L4-SIG w0.117: v1(122.25,-34.449) 122.25,-36.21 120.302,-38.158 120.302,-38.676 119.939,-39.04 119.558,-39.04 119.228,-38.71 119.228,-38.227 118.938,-37.937 118.552,-37.937 117.17,-39.319 117.17,-43.002 122.403,-48.235 125.247,-48.235 127,-49.987 127,-54.94 130.835,-58.776 142.799,-58.776 148.763,-64.739 v1(148.763,-65.978)
PORTE_TX0N: J8.8 MC3.72 | length 82.6
  L5-SIG w0.107: v1(136.656,-3.788) 136.575,-3.788 136.447,-3.66 136.074,-3.66 135.463,-3.048 130.302,-3.048 127.038,-6.312 126.917,-6.433 126.917,-6.536 127.062,-6.681 127.062,-6.784 126.821,-7.026 126.717,-7.026 126.573,-6.881 126.469,-6.881 126.327,-7.023 124.79,-8.56 124.79,-24.486 123.612,-25.664 123.612,-34.802 122.707,-35.706 122.707,-38.506 123.734,-39.533 124.44,-39.533 130.346,-45.438 131.438,-45.438 137.922,-51.922 137.922,-59.847 142.66,-64.585 142.66,-65.73 ccw(c143.01,-65.73) v1(142.763,-65.978)
PORTE_TX0P: J8.6 MC3.70 | length 82.6
  L5-SIG w0.107: v1(136.656,-3.212) 136.575,-3.212 136.447,-3.34 136.207,-3.34 135.595,-2.728 130.169,-2.728 124.47,-8.427 124.47,-24.353 123.292,-25.532 123.292,-34.669 122.387,-35.573 122.387,-38.639 123.601,-39.853 124.308,-39.853 130.213,-45.758 131.305,-45.758 137.602,-52.055 137.602,-59.98 142.34,-64.717 142.34,-65.73 cw(c141.989,-65.73) v1(142.237,-65.978)
PORTE_TX1N: J8.12 MC3.76 | length 77.1
  L5-SIG w0.107: v1(135.164,-5.288) 135.083,-5.288 134.955,-5.16 134.747,-5.16 134.471,-5.436 132.766,-5.436 127.483,-10.719 127.483,-11.455 127.483,-11.626 127.556,-11.699 127.76,-11.699 127.833,-11.772 127.833,-12.114 127.76,-12.187 127.556,-12.187 127.483,-12.26 127.483,-12.573 127.483,-29.57 127.803,-29.89 127.803,-32.446 127.305,-32.944 127.305,-35.158 128.168,-36.022 128.168,-39.222 131.931,-42.985 133.155,-42.985 142.017,-51.847 142.017,-54.115 145.202,-57.3 145.202,-64.679 144.635,-65.245 144.635,-66.958 144.16,-67.434 144.16,-68.18 v1(144.263,-68.283)
PORTE_TX1P: J8.10 MC3.74 | length 77.1
  L5-SIG w0.107: v1(135.164,-4.712) 135.083,-4.712 134.955,-4.84 134.614,-4.84 134.338,-5.116 132.633,-5.116 127.163,-10.586 127.163,-29.703 127.483,-30.023 127.483,-32.313 126.985,-32.811 126.985,-35.291 127.848,-36.154 127.848,-39.355 131.798,-43.305 133.022,-43.305 141.697,-51.98 141.697,-54.248 144.882,-57.432 144.882,-64.546 144.315,-65.112 144.315,-66.826 143.84,-67.301 143.84,-68.18 v1(143.737,-68.283)
PORTE_TX2N: J8.32 MC3.84 | length 67.3
  L5-SIG w0.107: v1(135.164,-13.288) 135.083,-13.288 134.955,-13.16 134.186,-13.16 132.715,-14.63 132.715,-21.387 132.715,-21.557 132.788,-21.631 132.993,-21.631 133.066,-21.704 133.066,-22.045 132.993,-22.118 132.788,-22.118 132.715,-22.191 132.715,-22.301 132.715,-29.383 135.639,-32.307 141.578,-32.307 150.8,-41.529 150.8,-42.55 152.745,-44.495 152.745,-64.145 151.66,-65.231 151.66,-65.794 151.763,-65.897 v1(151.763,-65.978)
PORTE_TX2P: J8.30 MC3.82 | length 67.3
  L5-SIG w0.107: v1(135.164,-12.711) 135.083,-12.711 134.955,-12.84 134.053,-12.84 132.395,-14.498 132.395,-27.158 132.395,-29.516 134.858,-31.979 135.506,-32.627 141.445,-32.627 150.48,-41.662 150.48,-42.682 152.425,-44.628 152.425,-64.013 151.34,-65.098 151.34,-65.794 151.237,-65.897 v1(151.237,-65.978)
PORTE_TX3N: J8.28 MC3.80 | length 73.5
  L5-SIG w0.107: v1(136.656,-6.788) 136.575,-6.788 136.447,-6.66 136.271,-6.66 130.063,-12.867 130.063,-22.022 130.063,-22.192 130.136,-22.266 130.341,-22.266 130.414,-22.339 130.414,-22.68 130.341,-22.753 130.136,-22.753 130.063,-22.826 130.063,-23.012 130.063,-31.008 132.451,-33.395 132.451,-38.196 150.16,-55.905 150.16,-68.099 150.263,-68.202 v1(150.263,-68.283)
PORTE_TX3P: J8.26 MC3.78 | length 73.5
  L5-SIG w0.107: v1(136.656,-6.212) 136.575,-6.212 136.447,-6.34 136.138,-6.34 129.743,-12.735 129.743,-31.14 132.131,-33.528 132.131,-38.329 149.84,-56.038 149.84,-68.099 149.737,-68.202 v1(149.737,-68.283)
PORTF_C2P_CLKN: J23.36 MC2.171 | length 97.1
  L1-TOP w0.107: v1(126.949,-31.547) 126.949,-31.902 127.16,-32.114 127.16,-32.926 127.25,-33.016 MC2.171@127.25,-33.41 MC2.171@127.16,-33.32 ; 199.489,-61.655 199.616,-61.782 200.658,-62.824 202.774,-62.824 205.16,-65.21 205.16,-65.986 205.163,-65.989 205.163,-67.044 J23.36@205.25,-67.13
  L4-SIG w0.107: v1(126.949,-31.547) 126.949,-31.752 127.175,-31.979 141.321,-31.979 148.164,-38.821 156.423,-38.821 157.652,-40.05 160.472,-40.05 162.662,-42.24 162.662,-43.815 166.482,-47.635 175.52,-47.635 184.029,-56.144 193.978,-56.144 198.913,-61.079 199.229,-61.395 199.374,-61.395 v1(199.431,-61.452)
PORTF_C2P_CLKP: J23.34 MC2.169 | length 97.1
  L1-TOP w0.107: v1(126.543,-32.004) 126.612,-32.004 126.629,-32.021 126.629,-32.035 126.84,-32.246 126.84,-32.824 126.75,-32.914 MC2.169@126.75,-33.41 MC2.169@126.84,-33.32 ; 199.262,-61.881 199.483,-62.102 200.526,-63.144 202.641,-63.144 204.84,-65.343 204.84,-65.986 204.836,-65.989 204.836,-67.044 J23.34@204.75,-67.13
  L4-SIG w0.107: v1(126.543,-32.004) 126.748,-32.004 127.043,-32.299 141.188,-32.299 148.031,-39.141 153.391,-39.141 153.571,-39.141 153.878,-39.141 153.932,-39.196 153.932,-39.499 153.986,-39.554 154.238,-39.554 154.292,-39.499 154.292,-39.196 154.346,-39.141 154.653,-39.141 154.737,-39.141 156.291,-39.141 157.52,-40.37 157.769,-40.37 160.339,-40.37 162.342,-42.373 162.342,-43.948 166.349,-47.955 175.387,-47.955 183.896,-56.464 193.846,-56.464 198.593,-61.212 199.002,-61.621 199.002,-61.766 v1(199.06,-61.824)
PORTF_P2C_CLKN: J23.35 MC2.164 | length 96.4
  L1-TOP w0.107: MC2.164@125.25,-39.59 125.16,-39.5 125.16,-38.676 v1(125.289,-38.548)
  L4-SIG w0.107: v1(125.289,-38.548) 125.16,-38.676 125.16,-38.856 128.316,-42.012 132.253,-42.012 137.877,-47.635 145.929,-47.635 162.286,-63.993 184.242,-63.993 189.017,-68.768 192.644,-68.768 194.781,-70.906 198.526,-70.906 199.812,-72.191 203.855,-72.191 205.16,-73.496 205.16,-73.92 v1(205.263,-74.023)
PORTF_P2C_CLKP: J23.33 MC2.162 | length 96.4
  L1-TOP w0.107: v1(124.712,-38.548) 124.84,-38.676 124.84,-39.5 MC2.162@124.75,-39.59
  L4-SIG w0.107: v1(124.712,-38.548) 124.84,-38.676 124.84,-38.988 128.184,-42.332 132.121,-42.332 137.744,-47.955 145.796,-47.955 162.154,-64.313 184.109,-64.313 188.885,-69.088 192.511,-69.088 194.649,-71.226 198.394,-71.226 199.679,-72.511 203.722,-72.511 204.84,-73.628 204.84,-73.92 v1(204.737,-74.023)
PORTF_REFCLKN: J23.15 MC3.88 | length 111.3
  L5-SIG w0.107: v1(136.656,-14.788) 136.575,-14.788 136.447,-14.66 136.167,-14.66 136.009,-14.818 136.009,-15.238 136.361,-15.589 137.236,-15.589 137.398,-15.589 137.505,-15.482 137.505,-15.306 137.613,-15.198 137.936,-15.198 138.044,-15.306 138.044,-15.482 138.152,-15.589 138.405,-15.589 139.254,-15.589 142.105,-18.44 153.695,-18.44 163.5,-28.245 178.898,-28.245 179.236,-28.245 181.762,-30.771 181.762,-31.109 181.762,-31.979 182.814,-33.03 185.151,-33.03 188.386,-36.266 196.256,-36.266 196.464,-36.474 198.669,-38.679 198.669,-38.866 201.742,-41.939 201.742,-44.262 201.742,-61.529 199.558,-63.713 199.558,-66.228 197.096,-68.689 197.096,-70.229 197.66,-70.793 197.66,-71.47 ccw(c198.01,-71.47) v1(197.763,-71.718)
PORTF_REFCLKP: J23.13 MC3.86 | length 111.3
  L5-SIG w0.107: v1(136.656,-14.212) 136.575,-14.212 136.447,-14.34 136.035,-14.34 135.689,-14.685 135.689,-15.37 136.228,-15.909 139.121,-15.909 141.972,-18.76 153.563,-18.76 163.367,-28.565 179.104,-28.565 181.442,-30.904 181.442,-32.111 182.681,-33.35 185.018,-33.35 186.263,-34.595 188.254,-36.586 196.123,-36.586 198.349,-38.811 198.349,-38.998 201.422,-42.072 201.422,-61.396 199.238,-63.581 199.238,-66.095 196.776,-68.557 196.776,-70.362 197.34,-70.925 197.34,-71.47 cw(c196.989,-71.47) v1(197.237,-71.718)
PORTF_RX0N: J23.7 MC3.95 | length 114.6
  L5-SIG w0.107: v1(142.836,-17.788) ccw(c142.527,-18.097) 142.527,-17.66 142.189,-17.66 141.819,-17.29 141.819,-16.7 142.239,-16.28 154.68,-16.28 155.504,-17.104 169.327,-17.104 169.541,-17.104 175.449,-23.012 177.383,-23.012 180.061,-25.69 180.393,-25.69 186.296,-31.593 187.198,-31.593 188.306,-31.593 188.687,-31.593 191.445,-34.351 196.322,-34.351 196.618,-34.351 200.294,-38.027 200.294,-38.323 200.294,-38.577 205.501,-43.784 205.501,-56.83 204.114,-58.217 204.114,-61.493 202.656,-62.951 202.656,-66.02 202.387,-66.289 199.29,-69.387 198.769,-69.387 198.534,-69.621 198.534,-72.034 198.051,-72.517 196.31,-72.517 195.623,-71.83 195.623,-71.189 195.37,-70.936 194.926,-70.936 194.66,-71.202 194.66,-71.47 ccw(c195.01,-71.47) v1(194.763,-71.718)
PORTF_RX0P: J23.5 MC3.93 | length 114.5
  L5-SIG w0.107: v1(142.836,-17.211) cw(c142.527,-16.902) 142.527,-17.34 142.322,-17.34 142.139,-17.157 142.139,-16.832 142.372,-16.6 144.348,-16.6 144.617,-16.6 145.048,-16.6 145.156,-16.708 145.156,-17.003 145.264,-17.111 145.587,-17.111 145.694,-17.003 145.694,-16.708 145.802,-16.6 146.125,-16.6 146.233,-16.708 146.233,-17.003 146.341,-17.111 146.664,-17.111 146.771,-17.003 146.771,-16.708 146.879,-16.6 147.218,-16.6 154.547,-16.6 155.372,-17.424 169.409,-17.424 175.317,-23.332 177.251,-23.332 179.928,-26.01 180.261,-26.01 186.164,-31.913 188.554,-31.913 191.313,-34.671 196.485,-34.671 199.974,-38.16 199.974,-38.71 205.181,-43.917 205.181,-56.697 203.794,-58.084 203.794,-61.361 202.336,-62.819 202.336,-65.888 199.157,-69.067 198.636,-69.067 198.214,-69.489 198.214,-71.901 197.935,-72.181 196.426,-72.181 195.943,-71.697 195.943,-71.056 195.503,-70.616 194.793,-70.616 194.34,-71.069 194.34,-71.47 cw(c193.989,-71.47) v1(194.237,-71.718)
PORTF_RX1N: J23.11 MC3.91 | length 122.7
  L5-SIG w0.107: v1(141.344,-16.288) ccw(c141.035,-16.597) 141.035,-16.16 140.475,-16.16 140.16,-15.844 140.16,-15.091 140.519,-14.732 141.6,-14.732 142.28,-15.412 144.304,-15.412 145.989,-13.726 148.672,-13.726 149.271,-14.326 154.61,-14.326 155.153,-14.869 171.309,-14.869 180.166,-23.727 181.278,-23.727 182.122,-23.727 182.497,-23.727 184.15,-25.379 184.15,-25.754 184.15,-27.256 186.597,-29.703 188.118,-29.703 189.007,-29.703 191.839,-32.535 198.727,-32.535 207.094,-40.902 207.094,-45.41 207.188,-45.504 207.188,-64.846 202.742,-69.291 200.978,-69.291 200.523,-69.746 200.523,-70.495 199.804,-71.214 199.804,-72.327 198.776,-73.355 196.382,-73.355 196.16,-73.578 196.16,-73.775 ccw(c196.51,-73.775) v1(196.263,-74.023)
PORTF_RX1P: J23.9 MC3.89 | length 122.7
  L5-SIG w0.107: v1(141.344,-15.711) cw(c141.035,-15.402) 141.035,-15.84 140.608,-15.84 140.48,-15.711 140.48,-15.224 140.652,-15.052 141.468,-15.052 142.147,-15.732 144.436,-15.732 144.549,-15.619 144.692,-15.476 144.844,-15.476 145.053,-15.685 145.205,-15.685 145.434,-15.457 145.434,-15.305 145.225,-15.096 145.225,-14.943 145.339,-14.829 146.122,-14.046 148.539,-14.046 149.139,-14.646 149.53,-14.646 149.799,-14.646 150.23,-14.646 150.338,-14.753 150.338,-15.049 150.445,-15.157 150.768,-15.157 150.876,-15.049 150.876,-14.753 150.984,-14.646 151.638,-14.646 154.477,-14.646 155.021,-15.189 171.176,-15.189 180.034,-24.047 182.365,-24.047 183.83,-25.512 183.83,-27.388 186.465,-30.023 188.874,-30.023 191.706,-32.855 198.594,-32.855 206.774,-41.034 206.774,-45.542 206.868,-45.636 206.868,-64.713 202.61,-68.971 200.845,-68.971 200.203,-69.613 200.203,-70.363 199.484,-71.081 199.484,-72.194 198.643,-73.035 196.25,-73.035 195.84,-73.445 195.84,-73.775 cw(c195.489,-73.775) v1(195.737,-74.023)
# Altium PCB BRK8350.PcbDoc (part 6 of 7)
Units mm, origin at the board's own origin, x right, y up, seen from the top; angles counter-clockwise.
Board outline 240 x 150 mm, 8 copper layers (L1-TOP, L2-GND, L3-PWR, L4-SIG, L5-SIG, L6-PWR, L7-GND, L8-BOT), stack 1.465 mm thick; 277 components, 542 nets, 1814 pads, 2338 vias.

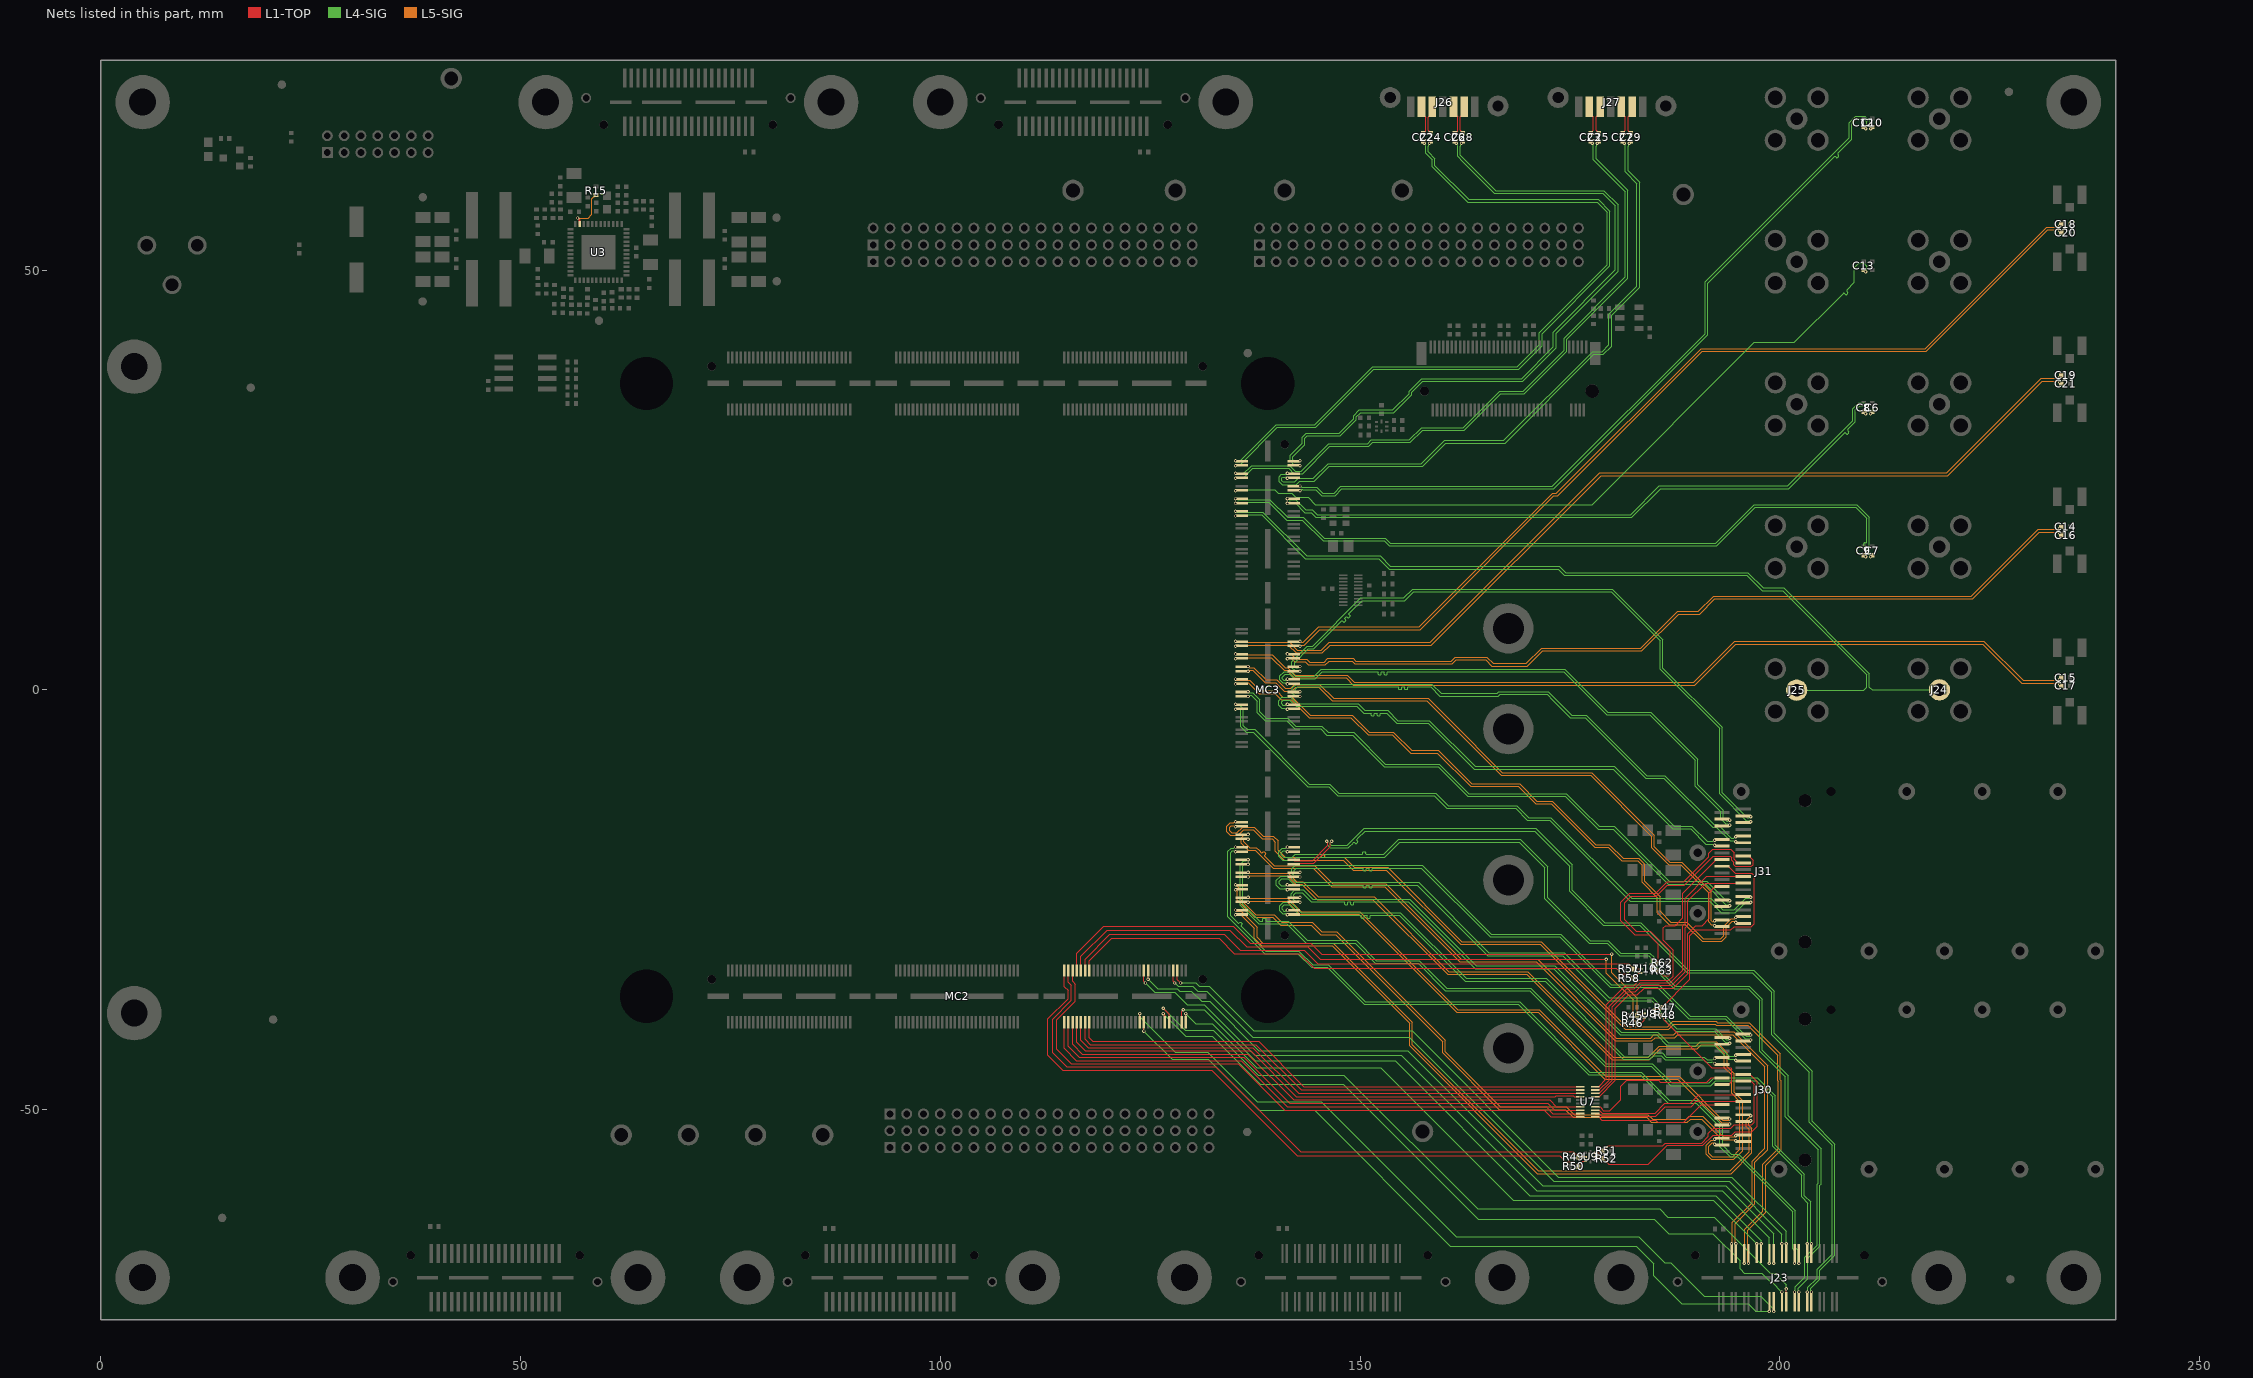
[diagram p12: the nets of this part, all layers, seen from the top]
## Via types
v1: diameter 0.406, hole 0.203, L1-TOP to L8-BOT, tented both sides, 2338 vias

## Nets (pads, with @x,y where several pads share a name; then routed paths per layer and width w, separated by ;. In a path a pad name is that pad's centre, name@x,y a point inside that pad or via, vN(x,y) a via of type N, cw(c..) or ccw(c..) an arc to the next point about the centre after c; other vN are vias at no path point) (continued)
PORTF_RX2N: J23.31 MC3.103 | length 110
  L1-TOP w0.107: MC3.103@142.09,-20.75 142.18,-20.66 144.466,-20.66 146.473,-18.653 146.473,-18.218 146.601,-18.09 v1(146.601,-18.009)
  L4-SIG w0.107: v1(146.601,-18.009) 146.601,-18.09 146.473,-18.218 146.473,-18.39 146.584,-18.501 148.457,-18.501 150.464,-16.495 170.922,-16.495 175.275,-20.848 175.275,-23.87 179.116,-27.711 183.286,-27.711 183.431,-27.711 189.105,-33.386 196.403,-33.386 196.856,-33.386 199.339,-35.869 199.339,-36.322 199.339,-40.919 203.835,-45.415 203.835,-51.384 206.543,-54.092 206.543,-66.126 206.543,-67.341 204.749,-69.134 204.749,-70.183 203.66,-71.272 203.66,-71.534 203.763,-71.637 v1(203.763,-71.718)
PORTF_RX2P: J23.29 MC3.101 | length 110
  L1-TOP w0.107: MC3.101@142.09,-20.25 142.18,-20.34 144.333,-20.34 146.153,-18.52 146.153,-18.218 146.025,-18.09 v1(146.025,-18.009)
  L4-SIG w0.107: v1(146.025,-18.009) 146.025,-18.09 146.153,-18.218 146.153,-18.522 146.452,-18.821 148.59,-18.821 148.91,-18.501 149.038,-18.374 149.254,-18.157 149.331,-18.157 149.487,-18.313 149.563,-18.313 149.742,-18.134 149.742,-18.058 149.586,-17.902 149.586,-17.826 149.784,-17.628 150.597,-16.815 170.79,-16.815 174.955,-20.98 174.955,-24.003 178.984,-28.031 183.298,-28.031 188.972,-33.706 196.723,-33.706 199.019,-36.002 199.019,-40.163 199.019,-41.052 203.515,-45.548 203.515,-51.517 206.223,-54.224 206.223,-67.208 204.429,-69.002 204.429,-70.05 203.34,-71.14 203.34,-71.534 203.237,-71.637 v1(203.237,-71.718)
PORTF_RX3N: J23.27 MC3.99 | length 109.5
  L4-SIG w0.107: v1(141.344,-19.288) 141.263,-19.288 141.135,-19.16 140.843,-19.16 140.614,-19.388 140.614,-19.66 140.894,-19.939 141.914,-19.939 142.262,-19.591 150.114,-19.591 150.24,-19.591 150.294,-19.537 150.294,-19.317 150.348,-19.263 150.601,-19.263 150.655,-19.317 150.655,-19.537 150.709,-19.591 150.901,-19.591 152.803,-19.591 154.579,-17.816 169.094,-17.816 172.329,-21.05 172.329,-24.759 177.44,-29.87 179.566,-29.87 181.04,-31.344 184.511,-31.344 185.014,-31.846 185.014,-32.72 187.559,-35.265 195.535,-35.265 196.246,-35.265 196.36,-35.265 197.917,-36.822 197.917,-36.936 197.917,-37.647 197.917,-42.901 200.965,-45.949 200.965,-50.703 204.894,-54.632 204.894,-58.86 204.739,-59.014 204.739,-66.253 203.291,-67.701 203.291,-70.114 202.16,-71.246 202.16,-71.534 202.263,-71.637 v1(202.263,-71.718)
PORTF_RX3P: J23.25 MC3.97 | length 109.5
  L4-SIG w0.107: v1(141.344,-18.711) 141.263,-18.711 141.135,-18.84 140.71,-18.84 140.294,-19.256 140.294,-19.792 140.761,-20.259 142.047,-20.259 142.395,-19.911 152.936,-19.911 154.711,-18.136 168.962,-18.136 172.009,-21.183 172.009,-24.892 177.307,-30.19 179.434,-30.19 180.907,-31.664 181.02,-31.664 184.379,-31.664 184.694,-31.979 184.694,-32.852 187.427,-35.585 196.227,-35.585 197.597,-36.955 197.597,-41.793 197.597,-43.033 200.645,-46.081 200.645,-50.836 204.574,-54.765 204.574,-58.727 204.419,-58.882 204.419,-66.121 202.971,-67.569 202.971,-69.982 201.84,-71.113 201.84,-71.534 201.737,-71.637 v1(201.737,-71.718)
PORTF_S0: J23.14 MC2.180 | length 80.4
  L1-TOP w0.114: MC2.180@129.25,-39.59 v1(129.25,-38.55)
  L4-SIG w0.117: v1(129.25,-38.55) 130.452,-39.751 132.41,-39.751 137.668,-45.009 152.457,-45.009 168.256,-60.808 192.067,-60.808 v1(197.237,-65.978)
PORTF_S1: J23.16 MC2.178 | length 82.2
  L1-TOP w0.114: MC2.178@128.75,-39.59 128.75,-38.276 v1(128.933,-38.093)
  L4-SIG w0.117: v1(128.933,-38.093) 131.412,-38.093 137.516,-44.196 154.178,-44.196 170.205,-60.223 192.353,-60.223 197.763,-65.633 v1(197.763,-65.978)
PORTF_S2: J23.17 MC2.160 | length 90.2
  L1-TOP w0.114: v1(124.25,-40.629) MC2.160@124.25,-39.59
  L4-SIG w0.117: v1(124.25,-40.629) 127.614,-43.993 131.902,-43.993 137.973,-50.063 144.577,-50.063 160.757,-66.243 182.883,-66.243 184.988,-68.349 184.988,-69.774 188.316,-73.101 196.201,-73.101 197.122,-74.023 v1(198.737,-74.023)
PORTF_S3: J23.18 MC2.159 | length 91.5
  L1-TOP w0.114: MC2.159@124.25,-33.41 124.25,-34.724 v1(124.433,-34.907)
  L4-SIG w0.117: v1(124.433,-34.907) 125.544,-36.017 127.914,-36.017 129.388,-37.49 131.445,-37.49 137.465,-43.51 154.915,-43.51 171.044,-59.639 193.14,-59.639 198.737,-65.236 v1(198.737,-68.283)
PORTF_S4: J23.19 MC2.158 | length 91.6
  L1-TOP w0.114: MC2.158@123.75,-39.59 v1(123.75,-38.55)
  L4-SIG w0.117: v1(123.75,-38.55) 123.75,-38.914 127.991,-43.155 131.851,-43.155 137.77,-49.073 145.39,-49.073 161.442,-65.126 183.185,-65.126 186.285,-68.226 186.996,-68.226 191.008,-72.238 197.745,-72.238 199.263,-73.755 v1(199.263,-74.023)
PORTF_S5: J23.20 MC2.161 | length 91.6
  L1-TOP w0.114: v1(124.75,-34.449) MC2.161@124.75,-33.41
  L4-SIG w0.117: v1(124.75,-34.449) 125.886,-35.585 128.232,-35.585 128.511,-35.865 129.87,-35.865 131.115,-37.109 132.105,-37.109 137.947,-42.951 155.651,-42.951 171.78,-59.08 193.547,-59.08 199.263,-64.796 v1(199.263,-68.283)
PORTF_S6: J23.21 MC2.170 | length 89.1
  L1-TOP w0.114: v1(126.563,-38.548) 126.75,-38.735 MC2.170@126.75,-39.59
  L4-SIG w0.117: v1(126.563,-38.548) 129.239,-41.224 132.385,-41.224 138.1,-46.939 147.98,-46.939 164.059,-63.017 185.014,-63.017 186.741,-64.745 191.999,-64.745 195.25,-67.996 195.25,-68.961 195.767,-69.478 197.809,-69.478 198.84,-70.509 199.029,-70.509 v1(200.237,-71.718)
PORTF_S7: J23.22 MC2.173 | length 87.4
  L1-TOP w0.114: MC2.173@127.75,-33.41 127.75,-34.724 v1(127.933,-34.907)
  L4-SIG w0.117: v1(127.933,-34.907) 128.333,-35.306 130.048,-35.306 130.645,-35.903 131.737,-35.903 137.185,-41.351 155.88,-41.351 173.076,-58.547 193.98,-58.547 200.237,-64.804 v1(200.237,-65.978)
PORTF_S8: J23.23 MC2.172 | length 91.8
  L1-TOP w0.114: v1(126.563,-37.922) 127.25,-38.609 MC2.172@127.25,-39.59 ; J23.23@200.75,-72.87 200.75,-71.359 v1(200.767,-71.342)
  L4-SIG w0.117: v1(126.563,-37.922) 129.154,-40.513 132.537,-40.513 137.897,-45.872 148.057,-45.872 164.008,-61.824 185.674,-61.824 186.639,-62.789 192.151,-62.789 198.84,-69.478 199.376,-69.478 200.767,-70.869 v1(200.767,-71.342)
PORTF_S9: J23.24 MC2.175 | length 87.5
  L1-TOP w0.114: MC2.175@128.25,-33.41 128.25,-34.536 v1(128.621,-34.907)
  L4-SIG w0.117: v1(128.621,-34.907) 130.436,-34.907 130.835,-35.306 132.029,-35.306 137.338,-40.615 156.185,-40.615 173.584,-58.014 194.285,-58.014 200.763,-64.492 v1(200.763,-65.978)
PORTF_TX0N: J23.8 MC3.96 | length 98.4
  L5-SIG w0.107: v1(136.656,-17.788) 136.528,-17.66 136.267,-17.66 136.138,-17.788 136.138,-18.105 136.83,-18.796 137.643,-18.796 137.963,-19.116 138.228,-19.381 138.351,-19.381 138.481,-19.251 138.605,-19.251 138.79,-19.437 138.79,-19.56 138.66,-19.69 138.66,-19.814 139.007,-20.16 139.776,-20.93 144.242,-20.93 144.572,-20.93 146.741,-23.099 153.045,-23.099 162.027,-32.08 170.967,-32.08 171.141,-32.08 180.523,-41.463 184.622,-41.463 184.991,-41.095 187.332,-41.095 187.7,-40.726 194.493,-40.726 198.542,-44.775 198.542,-53.264 198.542,-54.37 198.542,-54.745 197.028,-56.258 197.028,-61.189 194.66,-63.557 194.66,-65.875 v1(194.763,-65.978)
PORTF_TX0P: J23.6 MC3.94 | length 98.4
  L5-SIG w0.107: v1(136.656,-17.212) 136.528,-17.34 136.134,-17.34 135.818,-17.655 135.818,-18.237 136.697,-19.116 137.51,-19.116 139.644,-21.25 140.472,-21.25 144.44,-21.25 146.609,-23.419 152.913,-23.419 161.828,-32.334 161.894,-32.4 171.008,-32.4 180.391,-41.783 184.755,-41.783 185.123,-41.415 187.465,-41.415 187.833,-41.046 194.361,-41.046 198.222,-44.907 198.222,-54.612 196.708,-56.126 196.708,-61.056 194.34,-63.424 194.34,-65.875 v1(194.237,-65.978)
PORTF_TX1N: J23.12 MC3.92 | length 106.7
  L5-SIG w0.107: v1@135.156,-16.28 v1(135.164,-16.288) 135.083,-16.288 134.955,-16.16 134.661,-16.16 134.457,-16.363 134.457,-16.784 134.685,-17.012 135.332,-17.012 136.006,-16.338 137.413,-16.338 138.48,-17.404 139.649,-17.404 140.235,-17.991 140.235,-19.082 141.101,-19.948 145.237,-19.948 145.363,-19.948 145.418,-19.894 145.418,-19.674 145.472,-19.62 145.724,-19.62 145.778,-19.674 145.778,-19.894 145.832,-19.948 146.075,-19.948 148.137,-19.948 149.322,-21.133 153.264,-21.133 162.131,-30 171.499,-30 171.6,-30 181.692,-40.091 186.634,-40.091 187.243,-39.482 192.405,-39.482 192.557,-39.634 196.327,-39.634 200.048,-43.356 200.048,-46.41 200.142,-46.503 200.142,-54.595 200.142,-54.762 198.288,-56.616 198.288,-62.215 196.16,-64.343 196.16,-68.035 ccw(c196.51,-68.035) v1(196.263,-68.283)
PORTF_TX1P: J23.10 MC3.90 | length 106.7
  L5-SIG w0.107: v1(135.164,-15.711) 135.083,-15.711 134.955,-15.84 134.528,-15.84 134.137,-16.231 134.137,-16.917 134.552,-17.332 135.464,-17.332 136.138,-16.658 137.281,-16.658 138.348,-17.724 139.516,-17.724 139.915,-18.124 139.915,-19.214 140.969,-20.268 148.005,-20.268 149.189,-21.453 153.131,-21.453 161.998,-30.32 171.468,-30.32 181.559,-40.411 186.766,-40.411 187.376,-39.802 192.272,-39.802 192.425,-39.954 196.194,-39.954 199.728,-43.488 199.728,-46.542 199.822,-46.636 199.822,-54.629 197.968,-56.483 197.968,-62.082 195.84,-64.21 195.84,-68.035 cw(c195.489,-68.035) v1(195.737,-68.283)
PORTF_TX2N: J23.32 MC3.104 | length 98.7
  L4-SIG w0.107: v1(136.656,-20.788) 136.575,-20.788 136.447,-20.66 136.296,-20.66 136.017,-20.939 136.017,-25.502 138.049,-27.534 138.252,-27.534 138.378,-27.534 138.433,-27.479 138.433,-27.259 138.487,-27.205 138.739,-27.205 138.793,-27.259 138.793,-27.479 138.847,-27.534 139.154,-27.534 139.497,-27.534 141.423,-27.534 143.734,-29.845 149.525,-29.845 151.938,-32.258 157.044,-32.258 160.295,-35.509 170.332,-35.509 179.332,-44.509 184.818,-44.509 187.107,-46.797 191.612,-46.797 192.196,-46.213 197.313,-46.213 199.441,-48.341 199.441,-54.208 202.91,-57.678 202.91,-60.23 203.66,-60.98 203.66,-65.794 203.763,-65.897 v1(203.763,-65.978)
PORTF_TX2P: J23.30 MC3.102 | length 98.7
  L4-SIG w0.107: v1(136.656,-20.212) 136.575,-20.212 136.447,-20.34 136.164,-20.34 135.697,-20.806 135.697,-25.634 137.916,-27.854 141.29,-27.854 143.601,-30.165 149.393,-30.165 151.806,-32.578 156.911,-32.578 160.162,-35.829 170.2,-35.829 179.199,-44.829 184.686,-44.829 186.974,-47.117 191.745,-47.117 192.329,-46.533 197.18,-46.533 199.121,-48.473 199.121,-54.341 202.59,-57.81 202.59,-60.363 203.34,-61.112 203.34,-65.794 203.237,-65.897 v1(203.237,-65.978)
PORTF_TX3N: J23.28 MC3.100 | length 98.4
  L4-SIG w0.107: v1(135.164,-19.288) 135.083,-19.288 134.955,-19.16 134.798,-19.16 134.584,-19.373 134.584,-26.903 135.4,-27.719 135.489,-27.808 135.566,-27.808 135.722,-27.652 135.798,-27.652 135.977,-27.831 135.977,-27.907 135.821,-28.063 135.821,-28.139 135.997,-28.315 138.781,-31.1 142.707,-31.1 144.348,-32.741 146.228,-32.741 150.632,-37.145 168.996,-37.145 177.378,-45.527 183.47,-45.527 186.823,-48.88 190.15,-48.88 193.167,-51.897 193.167,-54.254 194.203,-55.291 195.088,-55.291 201.818,-62.021 201.818,-66.421 202.16,-66.763 202.16,-68.099 202.263,-68.202 v1(202.263,-68.283)
PORTF_TX3P: J23.26 MC3.98 | length 98.4
  L4-SIG w0.107: v1(135.164,-18.712) 135.083,-18.712 134.955,-18.84 134.665,-18.84 134.264,-19.24 134.264,-27.035 138.649,-31.42 142.575,-31.42 144.216,-33.061 146.095,-33.061 150.5,-37.465 168.864,-37.465 177.246,-45.847 183.337,-45.847 186.69,-49.2 190.017,-49.2 192.847,-52.029 192.847,-54.387 194.071,-55.611 194.955,-55.611 201.498,-62.154 201.498,-65.394 201.498,-66.554 201.84,-66.895 201.84,-68.099 201.737,-68.202 v1(201.737,-68.283)
QSFP_1_INT_B: MC2.129 R46.1 U8.3 | length 77.4
  L1-TOP w0.127: MC2.129@116.75,-33.41 116.75,-31.733 119.858,-28.626 134.493,-28.626 136.474,-30.607 143.758,-30.607 145.25,-32.099 v1(179.316,-32.099) ; v1(182.979,-39.694) 183.488,-39.694 183.842,-39.34 U8.3@183.842,-39.051
  L5-SIG w0.127: v1(179.316,-32.099) 179.316,-33.725 182.517,-36.925 182.517,-39.281 182.929,-39.694 v1(182.979,-39.694)
QSFP_1_INT_B_3V3: J30.28 R48.1 U8.6 | length 14.9
  L1-TOP w0.127: U8.6@185.052,-38.551 185.705,-38.551 185.908,-38.754 186.251,-39.096 186.251,-39.364 191.889,-45.003 194.125,-45.003 194.277,-45.155 194.277,-46.628 193.905,-47 J30.28@193.12,-47
QSFP_1_LP_MODE: MC2.125 U7.10 | length 76.1
  L1-TOP w0.127: MC2.125@115.75,-33.41 115.75,-34.699 116.078,-35.027 116.078,-37.084 113.868,-39.294 113.868,-42.799 115.589,-44.52 135.476,-44.52 141.039,-50.083 171.95,-50.083 172.718,-50.851 U7.10@176.208,-50.851
QSFP_1_LP_MODE_3V3: J30.31 U7.11 | length 16.2
  L1-TOP w0.127: U7.11@178.008,-50.851 178.411,-50.851 178.786,-51.226 185.209,-51.226 185.463,-51.48 188.562,-51.48 190.642,-49.4 J30.31@193.12,-49.4
QSFP_1_MODPRS_B: MC2.126 U7.7 | length 66.1
  L1-TOP w0.127: MC2.126@115.75,-39.59 115.75,-42.192 116.935,-43.377 136.619,-43.377 142.08,-48.838 172.56,-48.838 173.373,-49.651 U7.7@176.208,-49.651
QSFP_1_MODPRS_B_3V3: J30.27 U7.14 | length 18.1
  L1-TOP w0.127: U7.14@178.008,-49.651 178.605,-49.651 178.771,-49.816 178.771,-49.905 178.974,-50.108 179.748,-50.108 181.018,-48.838 181.018,-47.212 181.755,-46.476 185.539,-46.476 185.768,-46.704 191.29,-46.704 191.794,-46.2 J30.27@193.12,-46.2
QSFP_1_MODSEL_B: MC2.122 U7.9 | length 67.8
  L1-TOP w0.127: MC2.122@114.75,-39.59 114.75,-42.675 116.214,-44.139 135.832,-44.139 141.343,-49.651 172.154,-49.651 172.953,-50.451 U7.9@176.208,-50.451
QSFP_1_MODSEL_B_3V3: J30.8 U7.12 | length 18.5
  L1-TOP w0.127: U7.12@178.008,-50.451 178.477,-50.451 178.795,-50.768 185.209,-50.768 186.352,-49.625 189.426,-49.625 190.051,-49 J30.8@195.63,-49
QSFP_1_RESET_B: MC2.124 U7.8 | length 67
  L1-TOP w0.127: MC2.124@115.25,-39.59 115.25,-42.429 116.58,-43.758 136.162,-43.758 141.623,-49.219 172.331,-49.219 173.163,-50.051 U7.8@176.208,-50.051
QSFP_1_RESET_B_3V3: J30.9 U7.13 | length 18.7
  L1-TOP w0.127: U7.13@178.008,-50.051 178.482,-50.051 178.844,-50.413 185.133,-50.413 186.301,-49.244 189.299,-49.244 190.343,-48.2 J30.9@195.63,-48.2
QSFP_1_RX1N: J30.18 MC3.107 | length 65.1
  L4-SIG w0.107: v1(142.836,-22.288) 142.755,-22.288 142.627,-22.16 142.154,-22.16 141.834,-21.84 141.834,-21.326 142.255,-20.904 157.429,-20.904 165.633,-29.108 173.582,-29.108 173.909,-29.108 179.908,-35.107 185.551,-35.107 189.291,-38.847 193.604,-38.847 195.996,-41.239 196.397,-41.239 v1(196.531,-41.104)
QSFP_1_RX1P: J30.17 MC3.105 | length 65.1
  L4-SIG w0.107: v1(142.836,-21.711) 142.755,-21.711 142.627,-21.84 142.286,-21.84 142.154,-21.707 142.154,-21.458 142.388,-21.224 149.842,-21.224 150.023,-21.224 150.329,-21.224 150.383,-21.278 150.383,-21.498 150.437,-21.552 150.69,-21.552 150.744,-21.498 150.744,-21.278 150.798,-21.224 151.05,-21.224 151.105,-21.278 151.105,-21.498 151.159,-21.552 151.411,-21.552 151.465,-21.498 151.465,-21.278 151.519,-21.224 151.917,-21.224 157.297,-21.224 165.501,-29.428 173.777,-29.428 179.775,-35.427 185.418,-35.427 189.158,-39.167 193.472,-39.167 195.864,-41.559 196.394,-41.559 v1(196.531,-41.696)
QSFP_1_RX2N: J30.21 MC3.111 | length 64.8
  L4-SIG w0.107: v1(141.344,-23.788) ccw(c141.035,-24.097) 141.035,-23.66 140.453,-23.66 140.04,-23.247 140.04,-22.669 140.525,-22.184 141.568,-22.184 142.32,-22.936 156.967,-22.936 165.349,-31.318 173.887,-31.318 174.29,-31.318 179.654,-36.682 184.841,-36.682 185.801,-37.641 185.801,-38.405 187.742,-40.345 192.34,-40.345 193.635,-41.64 193.885,-41.64 v1(194.021,-41.504)
QSFP_1_RX2P: J30.22 MC3.109 | length 64.8
  L4-SIG w0.107: v1(141.344,-23.211) cw(c141.035,-22.902) 141.035,-23.34 140.586,-23.34 140.36,-23.114 140.36,-22.802 140.658,-22.504 141.435,-22.504 142.187,-23.256 149.835,-23.256 150.015,-23.256 150.322,-23.256 150.376,-23.31 150.376,-23.531 150.43,-23.585 150.682,-23.585 150.736,-23.531 150.736,-23.31 150.79,-23.256 151.043,-23.256 151.097,-23.31 151.097,-23.531 151.151,-23.585 151.404,-23.585 151.458,-23.531 151.458,-23.31 151.512,-23.256 151.79,-23.256 156.835,-23.256 165.217,-31.638 174.158,-31.638 179.521,-37.002 184.709,-37.002 185.481,-37.774 185.481,-38.537 187.609,-40.665 192.207,-40.665 193.502,-41.96 193.885,-41.96 v1(194.021,-42.096)
QSFP_1_RX3N: J30.15 MC3.115 | length 63.1
  L4-SIG w0.107: v1(142.836,-25.288) ccw(c142.527,-25.597) 142.527,-25.16 142.257,-25.16 141.785,-24.688 141.785,-24.249 142.224,-23.81 143.215,-23.81 144.342,-24.937 155.893,-24.937 163.824,-32.868 173.198,-32.868 181.097,-40.767 185.444,-40.767 186.714,-42.037 192.354,-42.037 193.957,-43.64 194.594,-43.64 v1(194.73,-43.504)
QSFP_1_RX3P: J30.14 MC3.113 | length 63.1
  L4-SIG w0.107: v1(142.836,-24.711) cw(c142.527,-24.402) 142.527,-24.84 142.389,-24.84 142.105,-24.556 142.105,-24.382 142.357,-24.13 143.083,-24.13 144.209,-25.257 147.625,-25.257 147.805,-25.257 148.112,-25.257 148.166,-25.311 148.166,-25.531 148.22,-25.585 148.472,-25.585 148.526,-25.531 148.526,-25.311 148.581,-25.257 148.833,-25.257 148.887,-25.311 148.887,-25.531 148.941,-25.585 149.194,-25.585 149.248,-25.531 149.248,-25.311 149.302,-25.257 149.504,-25.257 155.76,-25.257 163.691,-33.188 173.065,-33.188 180.965,-41.087 185.311,-41.087 186.581,-42.357 192.222,-42.357 193.825,-43.96 194.594,-43.96 v1(194.73,-44.096)
QSFP_1_RX4N: J30.24 MC3.119 | length 61.8
  L4-SIG w0.107: v1(141.344,-26.788) ccw(c141.035,-27.097) 141.035,-26.66 140.785,-26.66 140.404,-26.278 140.404,-25.717 140.839,-25.282 141.709,-25.282 142.08,-25.652 ; 142.103,-25.675 142.964,-26.537 154.802,-26.537 162.632,-34.366 172.161,-34.366 181.483,-43.688 184.379,-43.688 184.826,-43.241 185.984,-43.241 186.467,-43.724 191.017,-43.724 191.333,-44.04 191.892,-44.04 ccw(c191.892,-43.576) v1(192.22,-43.904)
QSFP_1_RX4P: J30.25 MC3.117 | length 61.9
  L4-SIG w0.107: v1(141.344,-26.211) cw(c141.035,-25.902) 141.035,-26.34 140.918,-26.34 140.724,-26.146 140.724,-25.85 140.971,-25.602 141.577,-25.602 142.832,-26.857 149.581,-26.857 149.761,-26.857 150.068,-26.857 150.122,-26.911 150.122,-27.131 150.176,-27.185 150.428,-27.185 150.482,-27.131 150.482,-26.911 150.536,-26.857 150.789,-26.857 150.843,-26.911 150.843,-27.131 150.897,-27.185 151.15,-27.185 151.204,-27.131 151.204,-26.911 151.258,-26.857 151.663,-26.857 154.67,-26.857 162.347,-34.534 162.499,-34.686 172.029,-34.686 181.35,-44.008 181.655,-44.008 184.511,-44.008 184.958,-43.561 185.852,-43.561 186.334,-44.044 190.884,-44.044 191.201,-44.36 191.892,-44.36 cw(c191.892,-44.824) v1(192.22,-44.496)
QSFP_1_SCL: MC2.123 R49.1 U9.2 | length 79.5
  L1-TOP w0.127: MC2.123@115.25,-33.41 115.25,-34.826 115.621,-35.196 115.621,-36.982 113.386,-39.218 113.386,-43.231 115.056,-44.901 132.809,-44.901 142.918,-55.01 175.397,-55.01 175.92,-55.534 175.92,-55.626 175.927,-55.62 U9.2@176.836,-55.62
QSFP_1_SCL_3V3: J30.11 R51.1 U9.7 | length 26.6
  L1-TOP w0.127: U9.7@178.046,-55.12 178.724,-55.12 178.929,-54.915 179.57,-54.274 186.047,-54.274 186.352,-53.969 190.67,-53.969 191.483,-53.156 191.483,-52.826 192.118,-52.191 194.125,-52.191 194.531,-51.784 196.665,-51.784 196.969,-51.48 196.969,-46.958 196.611,-46.6 J30.11@195.63,-46.6
QSFP_1_SDA: MC2.121 R50.1 U9.3 | length 81.1
  L1-TOP w0.127: MC2.121@114.75,-33.41 114.75,-35.325 115.214,-35.789 115.214,-36.779 112.801,-39.192 112.801,-43.499 114.585,-45.282 132.326,-45.282 142.537,-55.493 173.754,-55.493 174.44,-56.179 175.405,-56.179 175.92,-56.694 175.92,-56.744 176.544,-56.12 U9.3@176.836,-56.12
QSFP_1_SDA_3V3: J30.12 R52.1 U9.6 | length 28.8
  L1-TOP w0.127: U9.6@178.046,-55.62 178.719,-55.62 178.929,-55.829 179.608,-56.509 184.295,-56.509 186.555,-54.248 190.797,-54.248 192.033,-53.012 194.243,-53.012 194.655,-52.6 196.662,-52.6 197.274,-51.988 197.274,-46.654 196.421,-45.8 J30.12@195.63,-45.8
QSFP_1_TX1N: J30.37 MC3.108 | length 85.1
  L5-SIG w0.107: v1(136.656,-22.288) 136.784,-22.16 141.311,-22.16 142.306,-23.155 143.047,-23.155 144.876,-24.983 146.624,-24.983 151.526,-24.983 160.238,-33.696 160.426,-33.884 169.854,-33.884 180.03,-44.059 180.177,-44.059 184.44,-44.059 185.735,-42.763 190.125,-42.763 190.648,-42.24 192.303,-42.24 193.396,-43.332 193.396,-45.009 194.244,-45.857 194.244,-48.067 195.228,-49.051 195.228,-54.733 194.383,-55.578 191.96,-55.578 191.541,-55.159 191.541,-54.366 191.948,-53.96 192.084,-53.96 v1(192.22,-54.096)
QSFP_1_TX1P: J30.36 MC3.106 | length 87.3
  L5-SIG w0.107: v1(136.656,-21.711) 136.784,-21.84 141.444,-21.84 142.439,-22.835 143.18,-22.835 145.009,-24.663 151.659,-24.663 160.559,-33.564 169.987,-33.564 180.162,-43.739 184.307,-43.739 185.602,-42.443 189.992,-42.443 190.515,-41.92 192.436,-41.92 193.716,-43.2 193.716,-44.876 194.564,-45.725 194.564,-47.934 195.548,-48.918 195.548,-54.865 194.515,-55.898 191.828,-55.898 191.221,-55.291 191.221,-54.234 191.815,-53.64 192.084,-53.64 v1(192.22,-53.504)
QSFP_1_TX2N: J30.2 MC3.112 | length 73.7
  L5-SIG w0.107: v1(135.164,-23.788) 135.382,-24.005 135.382,-25.04 137.434,-27.092 139.614,-27.092 140.528,-28.006 144.16,-28.006 145.303,-29.149 147.107,-29.149 159.842,-41.885 159.842,-43.236 166.583,-49.977 174.437,-49.977 175.379,-50.919 184.147,-50.919 184.703,-51.476 188.982,-51.476 189.352,-51.105 190.678,-51.105 193.133,-53.56 194.594,-53.56 v1(194.73,-53.696)
QSFP_1_TX2P: J30.3 MC3.110 | length 73.8
  L5-SIG w0.107: v1(135.164,-23.211) 135.702,-23.749 135.702,-24.907 137.566,-26.772 139.746,-26.772 140.661,-27.686 144.293,-27.686 145.436,-28.829 147.239,-28.829 160.162,-41.752 160.162,-43.104 166.715,-49.657 174.57,-49.657 175.512,-50.599 184.279,-50.599 184.836,-51.156 188.849,-51.156 189.22,-50.785 190.81,-50.785 193.266,-53.24 194.594,-53.24 v1(194.73,-53.104)
QSFP_1_TX3N: J30.34 MC3.116 | length 68.4
  L5-SIG w0.107: v1(136.656,-25.288) 136.784,-25.16 141.263,-25.16 142.839,-26.736 149.85,-26.736 160.924,-37.81 161.508,-38.395 171.19,-38.395 179.141,-46.345 179.293,-46.345 179.593,-46.345 187.848,-46.345 193.063,-51.56 193.885,-51.56 v1(194.021,-51.696)
QSFP_1_TX3P: J30.33 MC3.114 | length 68.4
  L5-SIG w0.107: v1(136.656,-24.711) 136.784,-24.84 141.396,-24.84 142.972,-26.416 149.982,-26.416 161.641,-38.075 171.323,-38.075 179.273,-46.025 187.981,-46.025 193.196,-51.24 193.885,-51.24 v1(194.021,-51.104)
QSFP_1_TX4N: J30.5 MC3.120 | length 81.7
  L5-SIG w0.107: v1(135.164,-26.788) 135.292,-26.66 135.69,-26.66 137.414,-28.384 137.414,-29.586 138.297,-30.47 146.675,-30.47 155.89,-39.685 155.89,-42.377 171.11,-57.597 194.155,-57.597 194.195,-57.597 196.647,-55.146 196.647,-55.105 196.647,-52.197 196.317,-51.867 196.317,-51.51 v1(196.531,-51.296)
QSFP_1_TX4P: J30.6 MC3.118 | length 81.9
  L5-SIG w0.107: v1(135.164,-26.211) 135.292,-26.34 135.823,-26.34 137.734,-28.251 137.734,-29.454 138.43,-30.15 146.807,-30.15 156.21,-39.552 156.21,-42.245 171.242,-57.277 194.063,-57.277 196.327,-55.013 196.327,-52.33 195.997,-51.999 195.997,-51.239 v1(196.531,-50.704)
QSFP_2_INT_B: MC2.127 R45.1 U8.2 | length 78
  L1-TOP w0.127: MC2.127@116.25,-33.41 116.25,-31.349 119.456,-28.143 134.899,-28.143 136.931,-30.175 144.12,-30.175 145.409,-31.464 v1(179.977,-31.464) ; v1(182.979,-38.78) 183.336,-38.78 183.564,-38.551 U8.2@183.842,-38.551
  L5-SIG w0.127: v1(179.977,-31.464) 179.977,-33.7 182.979,-36.702 v1(182.979,-38.78)
QSFP_2_INT_B_3V3: J31.28 R47.1 U8.7 | length 29.2
  L1-TOP w0.127: U8.7@185.052,-38.051 185.697,-38.051 185.908,-37.84 185.908,-37.826 189.248,-34.487 189.248,-29.28 189.959,-28.569 194.15,-28.569 194.531,-28.188 196.598,-28.188 196.944,-27.842 196.944,-22.117 196.639,-21.812 194.658,-21.812 193.846,-21 J31.28@193.12,-21
QSFP_2_LP_MODE: MC2.128 U7.4 | length 65.1
  L1-TOP w0.127: MC2.128@116.25,-39.59 116.25,-41.979 117.272,-43 136.953,-43 142.385,-48.432 173.271,-48.432 173.373,-48.33 175.367,-48.33 175.488,-48.451 U7.4@176.208,-48.451
QSFP_2_LP_MODE_3V3: J31.31 U7.17 | length 35.2
  L1-TOP w0.127: U7.17@178.008,-48.451 178.477,-48.451 180.409,-46.519 180.409,-37.891 182.009,-36.29 183.025,-36.29 183.812,-35.503 187.317,-35.503 188.994,-33.827 188.994,-29.026 189.959,-28.061 190.721,-28.061 191.559,-27.223 191.559,-24.149 192.308,-23.4 J31.31@193.12,-23.4
QSFP_2_MODPRS_B: MC2.134 U7.1 | length 62.7
  L1-TOP w0.127: MC2.134@117.75,-39.59 117.75,-41.443 118.161,-41.853 137.916,-41.853 143.313,-47.251 U7.1@176.208,-47.251
QSFP_2_MODPRS_B_3V3: J31.27 U7.20 | length 39
  L1-TOP w0.127: U7.20@178.008,-47.251 178.403,-47.251 179.316,-46.337 179.316,-37.51 181.602,-35.224 182.618,-35.224 183.253,-34.589 186.784,-34.589 187.292,-34.081 187.292,-30.982 186.098,-29.788 186.098,-28.34 186.378,-28.061 187.521,-28.061 188.435,-27.146 188.435,-24.2 192.435,-20.2 J31.27@193.12,-20.2 J31.27@193.808,-20.2
QSFP_2_MODSEL_B: MC2.130 U7.3 | length 64.2
  L1-TOP w0.127: MC2.130@116.75,-39.59 116.75,-41.744 117.621,-42.615 137.229,-42.615 142.664,-48.051 U7.3@176.208,-48.051
QSFP_2_MODSEL_B_3V3: J31.8 U7.18 | length 37.9
  L1-TOP w0.127: U7.18@178.008,-48.051 178.477,-48.051 180.053,-46.475 180.053,-37.713 181.806,-35.96 182.796,-35.96 183.558,-35.198 187.089,-35.198 188.714,-33.573 188.714,-28.34 189.019,-28.035 189.019,-25.14 191.159,-23 J31.8@195.63,-23
QSFP_2_RESET_B: MC2.132 U7.2 | length 63.5
  L1-TOP w0.127: MC2.132@117.25,-39.59 117.25,-41.635 117.85,-42.234 137.567,-42.234 142.984,-47.651 U7.2@176.208,-47.651
QSFP_2_RESET_B_3V3: J31.9 U7.19 | length 38.2
  L1-TOP w0.127: U7.19@178.008,-47.651 178.482,-47.651 179.672,-46.461 179.672,-37.687 181.755,-35.605 182.669,-35.605 183.38,-34.893 186.911,-34.893 188.435,-33.369 188.435,-28.112 188.714,-27.832 188.714,-24.798 191.312,-22.2 J31.9@195.63,-22.2
QSFP_2_RX1N: J31.18 MC3.55 | length 78
  L4-SIG w0.107: v1(142.836,2.212) 142.755,2.212 142.627,2.34 142.19,2.34 141.869,2.661 141.869,3.358 143.718,5.207 144.348,5.207 150.104,10.963 155.214,10.963 156.255,12.004 180.041,12.004 186.07,5.975 186.07,2.601 193.131,-4.46 193.131,-12.263 196.109,-15.24 196.318,-15.24 196.454,-15.104 v1(196.531,-15.104) v1@196.528,-15.107
QSFP_2_RX1P: J31.17 MC3.53 | length 78
  L4-SIG w0.107: v1(142.836,2.788) 142.755,2.788 142.627,2.66 142.323,2.66 142.189,2.794 142.189,3.226 143.85,4.887 144.481,4.887 147.47,7.876 147.598,8.004 147.814,8.221 147.891,8.221 148.047,8.065 148.123,8.065 148.302,8.243 148.302,8.32 148.146,8.476 148.146,8.552 148.324,8.731 148.401,8.731 148.557,8.575 148.633,8.575 148.812,8.753 148.812,8.83 148.656,8.986 148.656,9.062 148.943,9.349 150.236,10.643 155.346,10.643 156.388,11.684 179.908,11.684 185.75,5.842 185.75,2.468 192.811,-4.593 192.811,-12.395 195.976,-15.56 196.318,-15.56 196.454,-15.696 v1(196.531,-15.696) v1@196.528,-15.693
QSFP_2_RX2N: J31.21 MC3.59 | length 65.8
  L4-SIG w0.107: v1(141.344,0.712) 141.263,0.712 141.135,0.84 140.795,0.84 140.421,1.214 140.421,1.657 140.939,2.174 141.763,2.174 142.296,1.641 144.516,1.641 145.356,2.481 174.374,2.481 179.507,-2.652 184.613,-2.652 190.236,-8.275 190.236,-11.318 193.269,-14.351 193.269,-15.236 193.673,-15.64 193.808,-15.64 193.944,-15.504 v1(194.021,-15.504)
QSFP_2_RX2P: J31.22 MC3.57 | length 65.8
  L4-SIG w0.107: v1(141.344,1.288) 141.263,1.288 141.135,1.16 140.927,1.16 140.741,1.346 140.741,1.524 141.072,1.854 141.63,1.854 142.164,1.321 144.648,1.321 145.489,2.161 151.613,2.161 151.793,2.161 152.1,2.161 152.154,2.107 152.154,1.887 152.208,1.833 152.46,1.833 152.514,1.887 152.514,2.107 152.568,2.161 152.821,2.161 152.875,2.107 152.875,1.887 152.929,1.833 153.182,1.833 153.236,1.887 153.236,2.107 153.29,2.161 153.543,2.161 174.242,2.161 179.375,-2.972 184.48,-2.972 189.916,-8.407 189.916,-11.451 192.949,-14.484 192.949,-15.368 193.54,-15.96 193.808,-15.96 193.944,-16.096 v1(194.021,-16.096)
QSFP_2_RX3N: J31.15 MC3.63 | length 62.6
  L4-SIG w0.107: v1(142.836,-0.788) 142.755,-0.788 142.627,-0.66 142.209,-0.66 141.945,-0.396 141.945,0.234 142.412,0.701 158.527,0.701 159.645,-0.417 166.334,-0.417 166.538,-0.213 172.395,-0.213 173.096,-0.914 175.179,-2.997 176.932,-2.997 184.145,-10.211 186.309,-10.211 192.119,-16.021 192.575,-16.021 194.194,-17.64 194.35,-17.64 194.517,-17.64 194.653,-17.504 v1(194.729,-17.504) v1@194.656,-17.578
QSFP_2_RX3P: J31.14 MC3.61 | length 62.5
  L4-SIG w0.107: v1(142.836,-0.212) 142.755,-0.212 142.627,-0.34 142.342,-0.34 142.265,-0.263 142.265,0.102 142.545,0.381 154.051,0.381 154.231,0.381 154.538,0.381 154.592,0.327 154.592,0.107 154.646,0.052 154.899,0.052 154.953,0.107 154.953,0.327 155.007,0.381 155.259,0.381 155.313,0.327 155.313,0.107 155.367,0.052 155.62,0.052 155.674,0.107 155.674,0.327 155.728,0.381 156.21,0.381 158.394,0.381 159.512,-0.737 166.467,-0.737 166.67,-0.533 172.263,-0.533 172.964,-1.234 175.047,-3.317 176.799,-3.317 184.013,-10.531 186.176,-10.531 191.987,-16.341 192.442,-16.341 194.061,-17.96 194.217,-17.96 194.517,-17.96 194.653,-18.096 v1(194.729,-18.096)
QSFP_2_RX4N: J31.24 MC3.67 | length 61
  L4-SIG w0.107: v1(141.344,-2.288) 141.263,-2.288 141.135,-2.16 140.67,-2.16 140.32,-1.809 140.32,-1.264 140.685,-0.899 141.763,-0.899 142.515,-1.651 149.754,-1.651 150.551,-2.449 153.295,-2.449 154.504,-3.658 158.263,-3.658 163.709,-9.103 180.269,-9.103 180.539,-9.373 187.397,-16.231 189.508,-16.231 191.317,-18.04 191.641,-18.04 192.007,-18.04 192.143,-17.904 v1(192.219,-17.904)
QSFP_2_RX4P: J31.25 MC3.65 | length 61
  L4-SIG w0.107: v1(141.344,-1.712) 141.263,-1.712 141.135,-1.84 140.803,-1.84 140.64,-1.676 140.64,-1.397 140.818,-1.219 141.63,-1.219 142.382,-1.971 149.621,-1.971 150.419,-2.769 150.8,-2.769 150.98,-2.769 151.287,-2.769 151.341,-2.823 151.341,-3.043 151.395,-3.097 151.647,-3.097 151.701,-3.043 151.701,-2.823 151.756,-2.769 152.008,-2.769 152.062,-2.823 152.062,-3.043 152.116,-3.097 152.369,-3.097 152.423,-3.043 152.423,-2.823 152.477,-2.769 152.654,-2.769 153.162,-2.769 154.371,-3.978 158.13,-3.978 163.576,-9.423 180.137,-9.423 187.264,-16.551 189.375,-16.551 191.185,-18.36 191.509,-18.36 192.007,-18.36 192.143,-18.496 v1@192.167,-18.496 ; v1@192.167,-18.443 v1(192.219,-18.496)
QSFP_2_SCL: MC2.131 R57.1 U10.2 | length 70.5
  L1-TOP w0.127: MC2.131@117.25,-33.41 117.25,-32.051 120.193,-29.108 133.831,-29.108 135.736,-31.013 143.332,-31.013 144.952,-32.633 181.983,-32.633 182.484,-33.134 182.484,-33.22 R57.1@182.534,-33.22 183.433,-33.22 U10.2@183.436,-33.217
QSFP_2_SCL_3V3: J31.11 R62.1 U10.7 | length 29.6
  L1-TOP w0.127: U10.7@184.646,-32.717 185.323,-32.717 185.521,-32.519 185.521,-30.278 184.396,-29.153 182.7,-29.153 181.069,-27.522 181.069,-25.296 182.139,-24.225 185.209,-24.225 186.581,-22.854 188.562,-22.854 191.534,-19.882 191.534,-19.45 191.984,-19 194.157,-19 194.531,-19.374 194.531,-20.161 194.97,-20.6 J31.11@195.63,-20.6
QSFP_2_SDA: MC2.133 R58.1 U10.3 | length 70.2
  L1-TOP w0.127: MC2.133@117.75,-33.41 117.75,-32.256 120.415,-29.591 133.198,-29.591 135.001,-31.394 142.748,-31.394 144.52,-33.166 180.51,-33.166 181.12,-33.776 181.983,-33.776 182.484,-34.277 182.484,-34.337 R58.1@182.534,-34.337 182.551,-34.337 183.172,-33.717 U10.3@183.436,-33.717
QSFP_2_SDA_3V3: J31.12 R63.1 U10.6 | length 35.6
  L1-TOP w0.127: U10.6@184.646,-33.217 185.315,-33.217 185.521,-33.423 186.128,-34.03 186.759,-34.03 186.962,-33.827 186.962,-31.134 184.574,-28.747 182.876,-28.747 181.526,-27.397 181.526,-25.343 182.269,-24.6 185.241,-24.6 186.591,-23.25 188.611,-23.25 192.054,-19.806 194.099,-19.806 194.277,-19.984 194.277,-20.288 194.506,-20.517 194.506,-20.847 194.658,-21 196.614,-21 196.817,-20.796 196.817,-20.263 196.354,-19.8 J31.12@195.63,-19.8 J31.12@194.906,-19.8
QSFP_2_TX1N: J31.37 MC3.56 | length 71.4
  L5-SIG w0.107: v1(136.656,2.212) 136.784,2.34 137.211,2.34 138.688,0.864 139.954,0.864 140.949,-0.132 141.875,-0.132 142.312,0.305 145.085,0.305 146.71,-1.321 157.958,-1.321 166.82,-10.183 177.442,-10.183 184.719,-17.46 184.719,-18.799 186.774,-20.853 188.189,-20.853 191.501,-24.166 191.501,-27.62 191.841,-27.96 192.083,-27.96 v1(192.219,-28.096)
QSFP_2_TX1P: J31.36 MC3.54 | length 71.4
  L5-SIG w0.107: v1(136.656,2.788) 136.784,2.66 137.343,2.66 138.82,1.184 140.087,1.184 141.082,0.188 141.742,0.188 142.179,0.625 145.217,0.625 146.843,-1.001 158.091,-1.001 158.228,-1.138 160.595,-3.505 166.953,-9.863 177.575,-9.863 185.039,-17.327 185.039,-17.399 185.039,-18.666 186.906,-20.533 188.321,-20.533 191.821,-24.033 191.821,-27.488 191.973,-27.64 192.083,-27.64 v1(192.219,-27.504)
QSFP_2_TX2N: J31.2 MC3.60 | length 76.3
  L5-SIG w0.107: v1(135.164,0.712) 135.292,0.84 136.701,0.84 137.988,-0.447 139.913,-0.447 140.635,-1.168 141.783,-1.168 143.932,-3.317 148.91,-3.317 150.942,-5.349 153.838,-5.349 156.022,-7.534 159.197,-7.534 163.159,-11.496 168.859,-11.496 170.927,-13.564 172.775,-13.564 177.957,-18.745 179.553,-18.745 181.178,-20.371 183.058,-20.371 183.576,-20.889 183.576,-22.921 185.405,-24.75 185.405,-26.523 186.847,-27.965 188.752,-27.965 190.723,-29.936 193.071,-29.936 193.624,-29.383 193.624,-28.251 194.327,-27.549 194.582,-27.549 v1(194.729,-27.696)
QSFP_2_TX2P: J31.3 MC3.58 | length 76.3
  L5-SIG w0.107: v1(135.164,1.288) 135.292,1.16 136.833,1.16 138.121,-0.127 140.046,-0.127 140.767,-0.848 141.915,-0.848 144.064,-2.997 149.043,-2.997 151.075,-5.029 153.97,-5.029 156.155,-7.214 158.898,-7.214 159.33,-7.214 163.292,-11.176 168.992,-11.176 171.059,-13.244 172.908,-13.244 178.09,-18.425 179.685,-18.425 181.311,-20.051 183.19,-20.051 183.896,-20.756 183.896,-22.788 185.725,-24.617 185.725,-26.391 186.98,-27.645 188.885,-27.645 190.856,-29.616 192.938,-29.616 193.304,-29.251 193.304,-28.119 194.194,-27.229 194.605,-27.229 v1(194.729,-27.104)
QSFP_2_TX3N: J31.34 MC3.64 | length 68.6
  L4-SIG w0.107: v1(136.656,-0.788) 136.784,-0.66 137.058,-0.66 137.729,-1.33 137.729,-2.723 138.689,-3.683 141.254,-3.683 142.219,-4.648 145.318,-4.648 146.055,-5.385 149.103,-5.385 152.887,-9.169 159.288,-9.169 162.793,-12.675 163.784,-12.675 174.426,-12.675 178.338,-16.586 180.141,-16.586 186.684,-23.129 191.137,-23.129 193.568,-25.56 193.885,-25.56 v1(194.021,-25.696)
QSFP_2_TX3P: J31.33 MC3.62 | length 68.6
  L4-SIG w0.107: v1(136.656,-0.212) 136.784,-0.34 137.191,-0.34 138.049,-1.198 138.049,-2.591 138.821,-3.363 141.387,-3.363 142.352,-4.328 145.451,-4.328 146.187,-5.065 149.235,-5.065 153.02,-8.849 159.421,-8.849 162.926,-12.355 174.559,-12.355 174.635,-12.431 176.413,-14.209 178.471,-16.266 180.274,-16.266 186.817,-22.809 191.27,-22.809 193.7,-25.24 193.885,-25.24 v1(194.021,-25.104)
QSFP_2_TX4N: J31.5 MC3.68 | length 73.3
  L4-SIG w0.107: v1(135.164,-2.288) 135.292,-2.16 135.56,-2.16 135.773,-2.372 135.773,-4.385 136.418,-5.029 137.292,-5.029 143.794,-11.532 146.258,-11.532 147.35,-12.624 158.852,-12.624 160.066,-13.838 160.34,-14.112 168.523,-14.112 169.931,-15.519 172.572,-15.519 182.199,-25.146 191.648,-25.146 193.034,-26.533 194.676,-26.533 196.049,-25.16 196.395,-25.16 v1(196.531,-25.296)
QSFP_2_TX4P: J31.6 MC3.66 | length 73.3
  L4-SIG w0.107: v1(135.164,-1.712) 135.292,-1.84 135.693,-1.84 136.093,-2.24 136.093,-4.252 136.55,-4.709 137.424,-4.709 143.927,-11.212 146.39,-11.212 147.483,-12.304 158.984,-12.304 160.473,-13.792 168.656,-13.792 168.969,-14.105 170.063,-15.199 172.705,-15.199 182.331,-24.826 191.78,-24.826 193.167,-26.213 194.543,-26.213 195.916,-24.84 196.395,-24.84 v1(196.531,-24.704)
RXN0: C16.2 MC3.51 | length 99.8
  L5-SIG w0.107: v1(141.344,3.712) 141.426,3.712 141.554,3.84 141.732,3.84 142.234,3.338 143.493,3.338 143.848,2.982 145.852,2.982 146.299,3.429 149.047,3.429 149.358,3.118 160.974,3.118 161.438,3.581 164.948,3.581 165.699,2.83 169.932,2.83 171.75,4.648 183.561,4.648 187.947,9.034 190.422,9.034 192.234,10.846 222.947,10.846 230.887,18.786 232.997,18.786 cw(c232.997,18.33) v1(233.319,18.652)
RXN1: C20.2 MC3.47 | length 111.1
  L5-SIG w0.107: v1(142.836,5.212) 142.964,5.34 143.339,5.34 145.187,7.189 157.164,7.189 157.849,7.874 173.078,23.104 173.522,23.104 190.735,40.316 217.416,40.316 231.912,54.811 232.997,54.811 cw(c232.997,54.356) v1(233.319,54.678)
RXN2: C8.2 MC3.15 | length 77.4
  L4-SIG w0.107: v1(141.344,22.212) cw(c141.654,21.903) 141.654,22.34 142.199,22.34 143.42,21.12 144.162,21.12 144.743,20.54 182.345,20.54 185.789,23.984 201.054,23.984 207.407,30.336 207.463,30.393 207.641,30.57 cw(c207.736,30.475) 207.832,30.57 207.909,30.494 ccw(c208.004,30.589) 208.1,30.494 208.182,30.576 ccw(c208.086,30.671) 208.182,30.767 208.105,30.843 cw(c208.201,30.939) 208.105,31.035 208.146,31.076 208.984,31.913 208.984,33.351 209.499,33.867 209.964,33.867 210.333,33.498 210.333,33.219 cw(c209.878,33.219) v1(210.2,32.896)
RXN3: C12.2 MC3.11 | length 92.6
  L4-SIG w0.107: v1(142.836,23.712) cw(c143.146,23.403) 143.146,23.84 144.724,23.84 145.434,23.13 147.032,23.13 147.834,23.933 173.038,23.933 191.414,42.309 191.414,48.456 206.302,63.343 206.442,63.484 cw(c206.538,63.388) 206.633,63.484 206.691,63.426 ccw(c206.786,63.522) 206.882,63.426 206.964,63.508 ccw(c206.868,63.604) 206.964,63.699 206.906,63.757 cw(c207.002,63.852) 206.906,63.948 206.947,63.989 208.559,65.601 208.559,67.437 209.15,68.027 209.969,68.027 210.359,67.638 210.359,67.153 cw(c209.903,67.153) v1(210.225,66.831)
RXP0: C14.2 MC3.49 | length 99.8
  L5-SIG w0.107: v1(141.344,4.289) 141.426,4.289 141.554,4.16 141.864,4.16 142.367,3.658 143.625,3.658 143.981,3.302 145.72,3.302 146.167,3.749 149.18,3.749 149.491,3.438 160.842,3.438 161.305,3.901 165.08,3.901 165.832,3.15 169.799,3.15 171.618,4.968 183.429,4.968 187.815,9.354 190.29,9.354 192.102,11.166 222.815,11.166 230.755,19.106 232.997,19.106 ccw(c232.997,19.562) v1(233.319,19.239)
RXP1: C18.2 MC3.45 | length 111.1
  L5-SIG w0.107: v1(142.836,5.788) 142.964,5.66 143.206,5.66 145.054,7.509 157.031,7.509 172.946,23.424 173.39,23.424 190.602,40.636 217.284,40.636 231.779,55.131 232.997,55.131 ccw(c232.997,55.587) v1(233.319,55.265)
RXP2: C6.2 MC3.13 | length 77.5
  L4-SIG w0.107: v1(141.344,22.788) ccw(c141.654,23.098) 141.654,22.66 142.332,22.66 143.552,21.44 144.295,21.44 144.875,20.86 182.212,20.86 185.656,24.304 200.922,24.304 208.664,32.046 208.664,33.484 209.367,34.187 210.097,34.187 210.654,33.63 210.654,33.219 ccw(c211.109,33.219) v1(210.787,32.896)
RXP3: C10.2 MC3.9 | length 92.7
  L4-SIG w0.107: v1(142.836,24.288) ccw(c143.146,24.598) 143.146,24.16 144.856,24.16 145.566,23.45 146.899,23.45 147.702,24.253 172.905,24.253 191.094,42.442 191.094,48.589 208.239,65.734 208.239,67.57 209.017,68.347 210.102,68.347 210.679,67.771 210.679,67.153 ccw(c211.135,67.153) v1(210.812,66.831)
SATA_1_TXA+: C22.2 MC3.2 | length 87.4
  L4-SIG w0.107: v1(135.164,27.289) 135.181,27.272 ccw(c135.451,27.542) 135.451,27.16 135.584,27.16 140.021,31.598 144.595,31.598 151.484,38.487 168.743,38.487 171.351,41.095 171.351,42.557 179.418,50.624 179.418,56.904 178.215,58.106 162.807,58.106 158.598,62.316 158.598,63.137 157.795,63.94 157.795,64.754 ccw(c157.301,64.754) v1(157.65,65.104)
SATA_1_TXA+_C: C22.1 J26.2 | length 3.5
  L1-TOP w0.107: J26.2@157.315,69.45 157.315,68.693 157.79,68.218 157.79,66.621 C22.1@157.447,66.278
SATA_1_TXA-: C24.2 MC3.4 | length 87.9
  L4-SIG w0.107: v1(135.164,26.712) 135.181,26.729 cw(c135.451,26.459) 135.451,26.84 135.716,26.84 140.154,31.278 144.727,31.278 151.617,38.167 168.876,38.167 171.671,40.963 171.671,42.424 179.738,50.491 179.738,57.036 178.348,58.426 162.94,58.426 158.918,62.449 158.918,63.27 158.115,64.072 158.115,64.754 cw(c158.609,64.754) v1(158.26,65.104)
SATA_1_TXA-_C: C24.1 J26.3 | length 3.5
  L1-TOP w0.107: C24.1@158.463,66.278 158.11,66.631 158.11,68.208 158.585,68.683 J26.3@158.585,69.45
SATA_1_TXB+: C28.2 MC3.1 | length 81.8
  L4-SIG w0.107: v1(142.836,27.289) cw(c142.527,27.598) 142.527,27.16 142.226,27.16 141.973,27.414 141.973,27.789 143.406,29.222 143.406,29.965 143.699,30.258 147.652,30.258 149.545,32.151 149.545,32.512 150.053,33.02 154.021,33.02 156.149,35.148 156.149,35.458 157.451,36.76 169.355,36.76 173.337,40.742 173.337,42.481 180.736,49.88 180.736,57.769 179.037,59.468 166.134,59.468 161.929,63.672 161.929,64.745 cw(c162.437,64.745) v1(162.078,65.104)
SATA_1_TXB+_C: C28.1 J26.6 | length 3.5
  L1-TOP w0.107: C28.1@162.281,66.278 161.92,66.638 161.92,68.233 162.395,68.708 J26.6@162.395,69.45
SATA_1_TXB-: C26.2 MC3.3 | length 82.3
  L4-SIG w0.107: v1(142.836,26.712) ccw(c142.527,26.403) 142.527,26.84 142.094,26.84 141.653,27.281 141.653,27.921 143.086,29.354 143.086,30.097 143.567,30.578 147.519,30.578 149.225,32.283 149.225,32.645 149.92,33.34 153.888,33.34 155.829,35.281 155.829,35.591 157.318,37.08 169.222,37.08 173.017,40.875 173.017,42.614 180.416,50.013 180.416,57.636 178.905,59.148 166.001,59.148 162.178,62.971 ; v1(161.46,65.104) cw(c161.101,64.745) 161.609,64.745 161.609,63.54 162.177,62.972
SATA_1_TXB-_C: C26.1 J26.5 | length 3.5
  L1-TOP w0.107: J26.5@161.125,69.45 161.125,68.718 161.6,68.243 161.6,66.621 C26.1@161.257,66.278
SATA_2_TXA+: C23.2 MC3.6 | length 75.1
  L4-SIG w0.107: v1(135.164,25.788) 135.292,25.66 136.042,25.66 137.073,26.691 141.634,26.691 142.259,26.067 143.013,26.067 146.273,29.327 150.891,29.327 151.351,29.786 155.869,29.786 157.314,31.232 162.275,31.232 166.609,35.566 169.41,35.566 174.303,40.458 174.303,41.906 181.574,49.178 181.574,59.348 177.787,63.135 177.787,64.748 ccw(c177.284,64.748) v1(177.64,65.104)
SATA_2_TXA+_C: C23.1 J27.2 | length 3.5
  L1-TOP w0.107: J27.2@177.315,69.45 177.315,68.708 177.79,68.233 177.79,66.631 C23.1@177.437,66.278
SATA_2_TXA-: C25.2 MC3.8 | length 75.6
  L4-SIG w0.107: v1(135.164,25.212) 135.292,25.34 136.175,25.34 137.206,26.371 141.502,26.371 142.127,25.747 143.145,25.747 146.406,29.007 151.024,29.007 151.483,29.466 156.002,29.466 157.447,30.912 162.408,30.912 166.742,35.246 169.543,35.246 174.623,40.326 174.623,41.774 181.894,49.045 181.894,59.481 178.107,63.267 178.107,64.748 cw(c178.611,64.748) v1(178.255,65.104)
SATA_2_TXA-_C: C25.1 J27.3 | length 3.5
  L1-TOP w0.107: C25.1@178.458,66.278 178.11,66.626 178.11,68.243 178.585,68.718 J27.3@178.585,69.45
SATA_2_TXB+: C29.2 MC3.5 | length 74.4
  L4-SIG w0.107: v1(141.344,25.789) 141.288,25.732 cw(c141.115,25.906) 141.115,25.66 140.637,25.66 140.358,25.382 140.358,24.797 140.704,24.451 142.368,24.451 142.789,24.873 144.565,24.873 146.311,26.619 157.443,26.619 160.212,29.388 167.266,29.388 177.839,39.96 178.949,39.96 179.941,40.953 179.941,44.609 183.294,47.961 183.294,60.438 181.915,61.818 181.915,64.754 cw(c182.409,64.754) v1(182.06,65.104)
SATA_2_TXB+_C: C29.1 J27.6 | length 3.5
  L1-TOP w0.107: C29.1@182.263,66.278 181.92,66.62 181.92,68.243 182.395,68.718 J27.6@182.395,69.45
SATA_2_TXB-: C27.2 MC3.7 | length 72.8
  L4-SIG w0.107: v1(141.344,25.212) 141.288,25.269 ccw(c141.115,25.095) 141.115,25.34 140.769,25.34 140.678,25.25 140.678,24.93 140.837,24.771 142.235,24.771 142.657,25.193 144.432,25.193 146.178,26.939 157.31,26.939 160.079,29.708 167.134,29.708 177.706,40.28 178.816,40.28 179.621,41.086 179.621,44.741 182.974,48.094 182.974,60.306 181.595,61.685 181.595,64.754 ccw(c181.1,64.754) v1(181.45,65.104)
SATA_2_TXB-_C: C27.1 J27.5 | length 3.5
  L1-TOP w0.107: J27.5@181.125,69.45 181.125,68.708 181.6,68.233 181.6,66.631 C27.1@181.247,66.278
SMA_REFCLKN: J25.1 MC3.20 | length 93.1
  L4-SIG w0.107: v1(135.164,20.712) cw(c135.474,20.403) 135.474,20.84 138.285,20.84 143.495,15.631 152.237,15.631 153.482,14.387 173.584,14.387 174.33,13.64 196.063,13.64 197.881,11.821 200.318,11.821 210.337,1.803 210.337,0.311 209.997,-0.029 J25.1@201.994,-0.029
SMA_REFCLKP: J24.1 MC3.18 | length 93.6
  L4-SIG w0.107: v1(135.164,21.288) ccw(c135.474,21.598) 135.474,21.16 138.418,21.16 143.627,15.951 152.37,15.951 153.615,14.707 173.716,14.707 174.463,13.96 196.195,13.96 198.014,12.141 200.451,12.141 210.657,1.935 210.657,0.311 210.968,0 J24.1@219,0
SUPPLY_1_CE: R15.1 U3.23 | length 5.2
  L1-TOP w0.203: v1(56.803,56.204) 57.042,55.964 U3.23@57.042,55.49
  L5-SIG w0.127: v1(56.803,56.204) 58.044,56.204 58.514,56.674 58.514,58.484 58.972,58.942 v1(59.022,58.942)
TXN0: C17.2 MC3.52 | length 103.5
  L5-SIG w0.107: v1(135.164,3.712) cw(c135.474,3.403) 135.474,3.84 139.431,3.84 140.943,2.328 141.263,2.328 142.158,1.433 148.336,1.433 149.2,0.569 189.857,0.569 194.755,5.467 224.173,5.467 228.829,0.811 232.997,0.811 cw(c232.997,0.356) v1(233.319,0.678)
TXN1: C21.2 MC3.48 | length 112
  L5-SIG w0.107: v1(135.164,5.212) cw(c135.474,4.903) 135.474,5.34 141.472,5.34 142.401,4.411 144.311,4.411 145.514,4.411 146.438,5.334 158.503,5.334 178.702,25.533 220.007,25.533 231.26,36.786 232.997,36.786 cw(c232.997,36.33) v1(233.319,36.652)
TXN2: C9.2 MC3.16 | length 84.9
  L4-SIG w0.107: v1(135.164,22.212) cw(c135.474,21.903) 135.474,22.34 139.126,22.34 141.238,20.229 143.098,20.229 145.581,17.746 152.89,17.746 153.474,17.161 192.479,17.161 197.066,21.749 209.01,21.749 210.333,20.426 210.333,17.989 210.333,17.913 210.333,17.662 cw(c210.198,17.662) 210.198,17.527 210.095,17.527 ccw(c210.095,17.392) 209.96,17.392 209.96,17.276 ccw(c210.095,17.276) 210.095,17.141 210.198,17.141 cw(c210.198,17.006) 210.333,17.006 210.333,16.948 210.333,16.175 cw(c209.878,16.175) v1(210.2,15.853)
TXN3: C13.2 MC3.12 | length 90.2
  L4-SIG w0.107: v1(135.164,23.712) cw(c135.474,23.403) 135.474,23.84 139.821,23.84 140.243,23.419 141.858,23.419 142.324,22.953 143.796,22.953 144.685,22.064 177.646,22.064 196.965,41.383 201.715,41.383 207.305,46.973 207.336,47.005 207.514,47.182 cw(c207.609,47.087) 207.705,47.182 207.779,47.108 ccw(c207.875,47.203) 207.97,47.108 208.052,47.19 ccw(c207.957,47.285) 208.052,47.381 207.978,47.455 cw(c208.074,47.551) 207.978,47.646 208.019,47.687 208.857,48.525 208.857,50.288 209.375,50.806 210.003,50.806 210.333,50.476 210.333,50.126 cw(c209.878,50.126) v1(210.2,49.803)
TXP0: C15.2 MC3.50 | length 103.5
  L5-SIG w0.107: v1(135.164,4.288) ccw(c135.474,4.598) 135.474,4.16 139.563,4.16 141.076,2.648 141.396,2.648 142.291,1.753 148.469,1.753 149.332,0.889 189.724,0.889 194.622,5.787 224.305,5.787 228.961,1.131 232.997,1.131 ccw(c232.997,1.587) v1(233.319,1.265)
TXP1: C19.2 MC3.46 | length 112
  L5-SIG w0.107: v1(135.164,5.788) ccw(c135.474,6.098) 135.474,5.66 141.604,5.66 142.534,4.731 145.382,4.731 146.305,5.654 147.818,5.654 158.37,5.654 178.57,25.853 219.875,25.853 231.127,37.106 232.997,37.106 ccw(c232.997,37.562) v1(233.319,37.239)
TXP2: C7.2 MC3.14 | length 84.9
  L4-SIG w0.107: v1(135.164,22.788) ccw(c135.474,23.098) 135.474,22.66 139.259,22.66 141.37,20.549 143.231,20.549 145.714,18.066 153.023,18.066 153.607,17.481 192.347,17.481 196.934,22.069 209.143,22.069 210.654,20.558 210.654,16.175 ccw(c211.109,16.175) v1(210.787,15.853)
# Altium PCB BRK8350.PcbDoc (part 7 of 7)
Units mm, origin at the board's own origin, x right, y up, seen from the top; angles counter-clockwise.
Board outline 240 x 150 mm, 8 copper layers (L1-TOP, L2-GND, L3-PWR, L4-SIG, L5-SIG, L6-PWR, L7-GND, L8-BOT), stack 1.465 mm thick; 277 components, 542 nets, 1814 pads, 2338 vias.

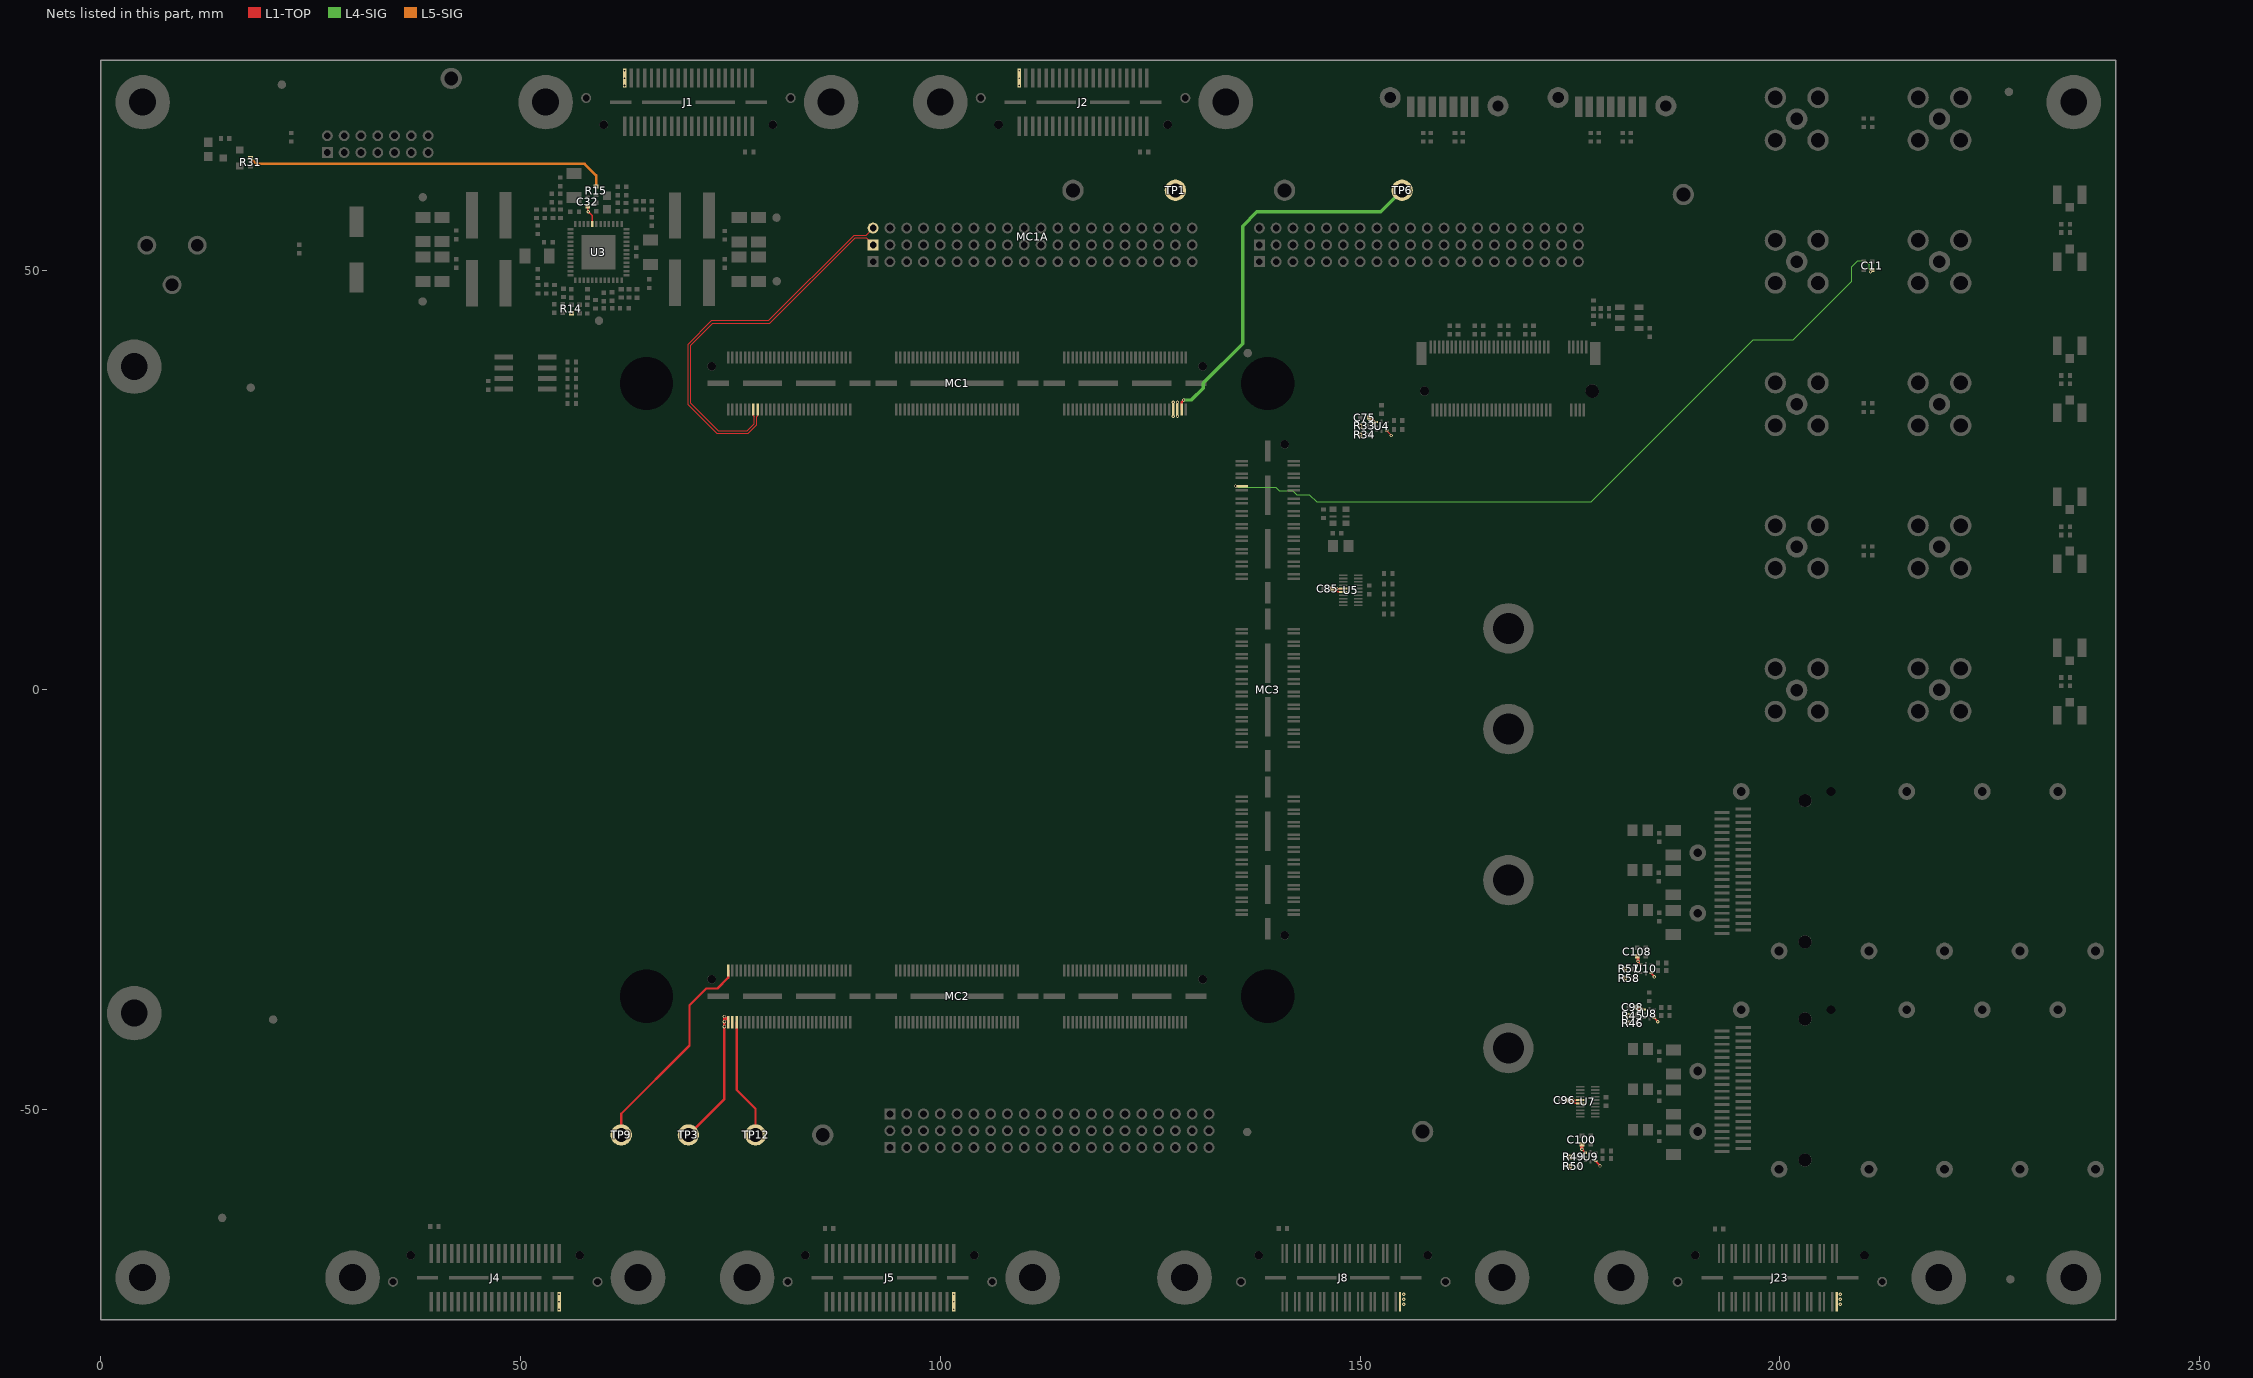
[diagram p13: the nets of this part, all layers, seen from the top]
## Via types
v1: diameter 0.406, hole 0.203, L1-TOP to L8-BOT, tented both sides, 2338 vias

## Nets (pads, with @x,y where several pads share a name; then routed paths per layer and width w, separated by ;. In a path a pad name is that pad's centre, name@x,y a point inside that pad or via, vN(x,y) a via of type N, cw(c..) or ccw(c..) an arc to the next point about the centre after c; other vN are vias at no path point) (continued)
TXP3: C11.2 MC3.10 | length 90.3
  L4-SIG w0.107: v1(135.164,24.288) ccw(c135.474,24.598) 135.474,24.16 139.954,24.16 140.376,23.739 141.99,23.739 142.456,23.273 143.929,23.273 144.818,22.384 177.513,22.384 196.832,41.703 201.582,41.703 208.537,48.657 208.537,50.421 209.242,51.126 210.135,51.126 210.654,50.608 210.654,50.126 ccw(c211.109,50.126) v1(210.787,49.803)
VCCBATT: MC2.6 TP12.1 | length 14.3
  L1-TOP w0.279: MC2.6@75.75,-39.59 75.75,-47.634 77.997,-49.88 TP12.1@77.997,-53
VDDD: C32.2 R14.2 R15.2 R31.2 U3.20 | length 45.8
  L1-TOP w0.203: C32.2@58.022,57.674 C32.2@58.022,57.624 58.022,56.991 58.061,56.953 v1(58.082,56.953) 58.542,56.493 U3.20@58.542,55.49
  L5-SIG w0.305: v1(17.85,63.346) 18.553,62.643 57.65,62.643 59.022,61.271 v1(59.022,59.942)
  other v1: 56.067,44.871
VIO1: J1.39 J2.39 MC1.174 MC1.176 TP1.1
  other v1: 127.75,32.575 128.25,32.575 127.75,34.245 128.25,34.245 62.401,71.976 109.401,71.976 62.401,72.865 109.401,72.865 62.401,73.754 109.401,73.754
VIO2: C75.2 C85.2 C96.2 C98.2 C100.2 C108.2 J4.39 J5.39 J8.39 J23.39 MC2.2 MC2.4 R33.2 R34.2 R45.2 R46.2 R49.2 R50.2 R57.2 R58.2 TP3.1 U4.1 U4.5 U5.5 U5.6 U7.5 U7.6 U8.1 U8.5 U9.1 U9.5 U10.1 U10.5 | length 28.6
  L1-TOP w0.127: U4.5@153.154,30.887 153.692,30.349 v1(153.692,30.295)
  L1-TOP w0.178: v1@147.199,12.06 147.199,11.805 147.335,11.669 U5.6@147.998,11.669 ; v1(147.209,12.069) U5.5@147.998,12.069 ; v1@175.409,-48.86 175.409,-49.115 175.545,-49.251 U7.6@176.208,-49.251 ; v1(175.418,-48.851) U7.5@176.208,-48.851 ; U9.5@178.046,-56.12 178.566,-56.64 v1(178.566,-56.693) ; U10.5@184.646,-33.717 185.031,-34.103 v1(185.031,-34.185) ; U8.5@185.052,-39.051 185.444,-39.443 v1(185.444,-39.509)
  L1-TOP w0.229: v1(176.421,-54.705) U9.1@176.836,-55.12 ; v1(183.101,-32.303) 183.101,-32.382 U10.1@183.436,-32.717
  L1-TOP w0.279: TP3.1@69.997,-53 74.288,-48.709 v1(74.288,-40.099) v1(74.288,-39.499) v1(74.288,-38.893) 74.75,-39.355 MC2.2@74.75,-39.59
  L1-TOP w0.406: C85.2@146.602,12.06 147.199,12.06 v1(147.209,12.069) ; C75.2@151.003,32.403 151.152,32.403 v1(151.635,31.92) ; C96.2@174.811,-48.86 175.409,-48.86 v1(175.418,-48.851) ; v1(176.421,-54.705) C100.2@176.421,-54.054 ; C98.2@182.932,-37.814 183.161,-38.043 v1(183.539,-38.043) ; C108.2@183.025,-31.673 183.101,-31.749 v1(183.101,-32.303)
  other v1: 54.6,-73.754 101.6,-73.754 155.201,-73.166 207.201,-73.166 54.6,-72.865 101.6,-72.865 155.201,-72.557 207.201,-72.557 54.6,-71.976 101.6,-71.976 155.201,-71.972 207.201,-71.972 175.02,-56.744 175.02,-55.626 181.979,-39.694 181.979,-38.78 181.584,-34.337 181.584,-33.22 150.038,30.385 150.043,31.438
VREF1: MC1.178 TP6.1 | length 46.1
  L1-TOP w0.279: MC1.178@128.75,33.41 128.75,34.275 v1(129,34.525)
  L4-SIG w0.406: v1(129,34.525) 129.907,34.525 131.318,35.936 131.318,36.551 136,41.233 136,55.242 137.711,56.953 152.453,56.953 TP6.1@155,59.5
VREF2: MC2.1 TP9.1 | length 25.6
  L1-TOP w0.279: TP9.1@62,-53 62,-50.471 70.129,-42.342 70.129,-37.567 72.136,-35.56 73.457,-35.56 74.75,-34.266 MC2.1@74.75,-33.41
XADC_VN: MC1.16 MC1A.2 | length 46.8
  L1-TOP w0.107: MC1.16@78.25,33.41 78.25,32.632 78.16,32.542 78.16,31.581 77.146,30.567 73.4,30.567 69.977,33.99 69.977,41.194 72.795,44.013 79.584,44.013 89.732,54.16 91.16,54.16 MC1A.2@92,55
XADC_VP: MC1.14 MC1A.1 | length 45.2
  L1-TOP w0.107: MC1.14@77.75,33.41 77.75,32.632 77.84,32.542 77.84,31.714 77.013,30.887 73.532,30.887 70.297,34.122 70.297,41.062 72.928,43.693 79.717,43.693 89.864,53.84 91.16,53.84 MC1A.1@92,53
pads on no net: FID1.FID? FID2.FID? FID3.FID? FID4.FID? FID5.FID? FID6.FID? FID7.FID? FID8.FID? J1.37 J1.38 J1.MH J2.37 J2.38 J2.MH J3.12 J3.14 J4.37 J4.38 J4.MH J5.37 J5.38 J5.MH J8.37 J8.38 J8.MH J23.37 J23.38 J23.MH J26.MH J27.MH J28.3 J30.MH J31.MH J32.6 J32.8 J32.20 J32.22 J32.24 J32.26 J32.28 J32.30 J32.32 J32.34 J32.36 J32.46 J32.48 J32.56 J32.58 J32.67 J32.MH JSO1.1 JSO2.1 JSO3.1 JSO4.1 MC1.119 MC1.120 MC1.161 MC1.162 MC1.163 MC1.164 MC1.165 MC1.166 MC1.167 MC1.168 MC1.169 MC1.170 MC1.171 MC1.172 MC1.180 MC1.MH MC2.24 MC2.26 MC2.135 MC2.139 MC2.141 MC2.144 MC2.146 MC2.149 MC2.152 MC2.155 MC2.157 MC2.163 MC2.165 MC2.166 MC2.167 MC2.168 MC2.174 MC2.176 MC2.177 MC2.179 MC2.MH MC3.37 MC3.38 MC3.39 MC3.40 MC3.41 MC3.42 MC3.43 MC3.44 MC3.MH MH1.1 MH2.1 MH5.1 MH6.1 MH7.1 MH8.1 MH9.1 MH10.1 MH11.1 MH12.1 MH13.1 MH14.1 MH15.1 MH16.1 MH17.1 MH18.1 MH19.1 MH20.1 QSFP1.0 QSFP2.0 U2.2 U3.13 U3.27 U3.34 U3.41 U3.44 U3.48 U6.2
copper on no net: | length 0.1
  L1-TOP w0.114: 121.66,-33.32 121.75,-33.41

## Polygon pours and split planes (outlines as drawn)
DGND on L3-PWR "L3_TPS65400_DGND" (solid, pour order 195): 57.252,54.178 57.252,50.114 61.316,50.114 61.316,54.178
DGND on L3-PWR "L3_DGND" (solid, pour order 198): 0.5,-74.5 0.5,74.5 239.5,74.5 239.5,-74.5
VIO1 on L3-PWR "L3_VIO1" (solid, pour order 197): 18.001,31.318 135.727,31.318 136.611,32.202 140.961,32.202 153.952,45.193 172.763,45.193 178.346,50.776 178.346,56.42 139.769,56.42 139.769,74.504 18.001,74.504
+VDCIN on L3-PWR "L3_+VDCIN" (solid, pour order 196): 9.334,74.504 9.334,6.553 70.841,6.553 70.841,26.594 75.59,31.344 75.59,38.76 75.158,39.193 75.158,40.844 67.262,48.74 67.262,54.763 52.616,69.409 52.616,74.504
no net on L3-PWR "L3_+3.3V_M.2" (solid, pour order 199): 10.5,-74.416
DGND on L8-BOT "L8_TPS65400_DGND" (solid, pour order 208): 57.252,54.178 57.252,50.114 61.316,50.114 61.316,54.178
+3.3V_SZG on L8-BOT "L8_+3.3V_SZG" (solid, pour order 219): 0.5,74.5 239.5,74.5 239.5,-74.5 0.5,-74.5
+3.3V_QSFP on L8-BOT "L8_+3.3V_QSFP" (solid, pour order 210): 74.77,53.375 74.77,-23.978 138.379,-23.978 159.552,-45.15 159.552,-56.458 185.728,-56.458 185.728,-41.156 187.571,-39.313 187.571,-31.388 184.168,-27.985 184.168,53.375
+5V_SZG on L8-BOT "L8_+5V_SZG" (solid, pour order 211): 125.291,68.383 122.37,68.383 119.522,65.536 82.342,65.536 79.393,68.485 69.094,68.485 61.62,61.011 52.476,61.011 40.83,49.365 37.338,49.365 37.338,-66.629 38.984,-68.275 39.587,-68.275 42.641,-65.221 82.747,-65.221 85.801,-68.275 86.499,-68.275 90.315,-64.459 135.881,-64.459 139.697,-68.275 140.956,-68.275 143.934,-65.297 188.843,-65.297 191.821,-68.275 192.829,-68.275 192.829,-56.852 183.217,-57.404 125.291,7.63
+3.3V_M.2 on L8-BOT "L8_+3.3V_M.2" (solid, pour order 209): 74.77,56.312 74.77,52.529 78.194,52.529 121.904,8.82 189.674,8.82 189.674,57.856 76.314,57.856
NetC102_2 on L8-BOT "L8_QSFP2_VCCTX" (solid, pour order 217): 194.175,-22 194.175,-19.907 190.111,-15.843 186.124,-15.843 186.124,-20.466 188.587,-22
NetC104_2 on L8-BOT "L8_QSFP1_VCCRX" (solid, pour order 215): 194.175,-20.923 196.541,-20.923 196.541,-25.209 194.594,-27.155 186.245,-27.155 186.245,-24.259 192.9,-24.259 194.175,-22.984
NetC90_2 on L8-BOT "L8_QSFP1_VCCTX" (solid, pour order 214): 194.175,-48.111 194.175,-46.019 190.111,-41.955 186.124,-41.955 186.124,-46.577 188.664,-48.111
NetC92_2 on L8-BOT "L8_QSFP1_VCCRX" (solid, pour order 212): 194.175,-47.035 196.541,-47.035 196.541,-51.32 194.594,-53.266 186.245,-53.266 186.245,-50.371 192.9,-50.371 194.175,-49.095
NetC106_2 on L8-BOT "L8_QSFP1_VCC1" (solid, pour order 216): 194.175,-22.244 194.175,-24.203 186.098,-24.203 186.098,-20.619 188.24,-20.619 189.866,-22.244
NetC94_2 on L8-BOT "L8_QSFP1_VCC1" (solid, pour order 213): 194.175,-48.355 194.175,-50.314 186.098,-50.314 186.098,-46.73 188.213,-46.73 189.839,-48.355
VIO2 on L4-SIG "L4_VIO2" (solid, pour order 200): 95.319,30.918
DGND on L6-PWR "L6_TPS65400_DGND" (solid, pour order 203): 57.252,54.178 57.252,50.114 61.316,50.114 61.316,54.178
DGND on L6-PWR "L6_DGND" (solid, pour order 207): 0.5,-74.5 239.5,-74.5 239.5,74.5 0.5,74.5
+3.3VDD on L6-PWR "L6_+3.3VDD" (solid, pour order 206): 41.808,31.344 135.752,31.344 136.61,32.202 140.957,32.202 153.948,45.193 172.738,45.193 178.427,50.882 178.427,56.445 139.769,56.445 139.769,74.504 41.808,74.504
+VDCIN on L6-PWR "L6_+VDCIN" (solid, pour order 205): 9.321,74.504 9.321,6.553 70.841,6.553 70.841,26.58 75.59,31.33 75.59,38.755 75.149,39.197 75.149,40.853 67.262,48.74 67.262,54.758 52.616,69.404 52.616,74.504
VDDD on L6-PWR "L6_VDDD" (solid, pour order 204): 58.082,60.433 59.022,60.433 62.737,56.717 62.737,44.304 55.441,44.304 55.441,57.385 58.082,57.385
DGND on L7-GND "L4-DGND" (solid, pour order 202): 0.5,-74.492 0.5,74.492 239.492,74.492 239.492,-74.492
VIO2 on L7-GND "L4-VIO2" (solid, pour order 201): 54.12,-74.492 208.059,-74.492 208.059,-70 186.547,-48.488 186.547,0.802 154.094,33.255 147.922,33.255 147.922,13.269 146.898,12.245 146.898,11.648 173.119,-14.573 173.119,-46.73 160.47,-59.379 93.034,-59.379 72.203,-38.548 70.733,-38.548 54.12,-55.161
DGND on L1-TOP "L1-DGND" (solid, remove dead copper, pour order 194): 0.5,-74.492 0.5,74.492 239.492,74.492 239.492,-74.492
DGND on L2-GND (split plane): 239.49,74.49 239.49,-74.49 0.51,-74.49 0.51,74.49

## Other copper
L1-TOP:
  region net VIO2: 75.393,-38.677 74.085,-38.677 74.085,-40.302 75.393,-40.302
  rectangle net +1.8VDD: 128.608,38.678 129.916,40.303
  rectangle net +3.3V_M.2: 175.508,31.655 177.361,34.296
  rectangle net NetC106_2: 183.641,-22.138 188.181,-20.868
  rectangle net NetC102_2: 183.685,-17.414 188.175,-16.118
  rectangle net NetC104_2: 183.736,-26.892 188.181,-25.622
  region net +5V_SZG: 140.883,-66.017 140.07,-66.017 140.07,-68.252 140.883,-68.252
  rectangle net +3.3V_SZG: 154.616,-68.244 155.429,-66.009
  rectangle net VIO2: 154.616,-73.984 155.429,-71.749
  rectangle net VIO2: 206.616,-73.984 207.429,-71.749
  region net +5V_SZG: 192.883,-66.017 192.07,-66.017 192.07,-68.252 192.883,-68.252
  rectangle net +3.3V_SZG: 206.616,-68.244 207.429,-66.009
  region net +VDCIN: 76.397,34.132 73.935,34.132 73.935,31.471 76.397,31.471
  region net +3.3V_M.2: 159.301,34.296 158.433,34.296 157.98,33.843 157.98,31.68 159.301,31.68
  region net NetC90_2: 183.711,-43.438 188.206,-43.438 188.206,-42.194 183.711,-42.194
  region net NetC94_2: 183.711,-48.236 188.206,-48.236 188.206,-46.991 183.711,-46.991
  region net NetC92_2: 183.711,-53.045 188.206,-53.045 188.206,-51.8 183.711,-51.8
  region net +3.3V_M.2: 79.562,57.232 79.562,54.299 72.265,54.299 72.265,59.137 73.576,59.137 75.481,57.232
  region net NetC35_2: 62.315,51.009 63.039,51.009 64.512,49.536 66.836,49.536 66.836,51.187 68.709,51.187 68.709,45.777 67.674,45.777 65.947,47.504 65.947,48.546 64.309,48.546 63.09,49.765 62.315,49.765
  region net DGND: 62.315,52.305 62.315,53.016 63.052,53.016 64.601,54.565 66.201,54.565 67.304,53.463 73.567,53.462 73.567,53.994 79.231,53.994 79.231,50.963 73.567,50.963 73.567,51.586 66.836,51.586 66.836,52.305
  region net +VDCIN: 62.315,51.975 62.315,51.263 63.179,51.263 64.525,49.917 66.499,49.917 66.499,51.975
  region net NetC45_2: 68.665,53.829 68.665,59.264 67.789,59.264 66.201,57.677 66.201,55.696 64.22,55.696 63.039,54.515 62.315,54.515 62.315,53.39 62.975,53.39 64.57,54.984 66.468,54.985 67.624,53.829
  region net DGND: 39.785,54.045 39.785,50.971 43.062,50.971 43.062,51.517 49.92,51.517 49.92,50.806 51.901,50.806 51.901,52.711 52.206,53.016 53.171,53.016 53.171,53.651 49.234,53.651 49.234,53.518 43.062,53.518 43.062,54.045
  region net +VDCIN: 52.257,50.768 54.212,50.768 55.19,51.746 56.27,51.746 56.27,52.533 55.228,52.533 54.111,53.651 53.476,53.651 53.476,52.66 52.257,52.66
  region net NetC56_2: 56.295,52.762 55.394,52.762 54.111,54.045 47.812,54.045 47.812,59.264 49.056,59.264 51.393,56.928 51.393,54.946 51.698,54.642 53.959,54.642 55.585,53.016 56.295,53.016
  region net NetC66_2: 56.27,51.517 55.305,51.517 54.238,50.451 49.539,50.451 49.539,51.187 48.015,51.187 48.015,45.752 49.057,45.752 51.418,48.113 51.418,49.396 51.761,49.739 54.047,49.739 55.571,51.263 56.27,51.263
  region net +3.3V_QSFP: 79.562,50.679 73.135,50.679 73.135,51.187 71.891,51.187 71.865,51.213 71.865,45.802 73.424,45.802 75.38,47.758 79.562,47.758
  region net +VDCIN: 55.491,59.264 55.491,58.02 55.94,58.02 56.575,57.385 56.575,56.617 56.999,56.617 57.396,56.22 57.396,55.15 57.676,55.15 57.676,56.982 57.438,57.22 57.438,59.264
  region net +3.3V_SZG: 37.487,57.601 37.487,54.375 44.396,54.375 44.396,59.214 42.923,59.214 41.31,57.601
  region net +5V_SZG: 37.487,47.364 37.487,50.59 44.396,50.59 44.396,45.752 42.923,45.752 41.31,47.364
  region net +VDCIN: 76.378,40.97 76.378,38.128 73.859,38.128 73.859,40.97

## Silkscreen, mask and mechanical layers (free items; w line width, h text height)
Top Overlay:
  rectangle: 38.042,-56.433 54.831,-48.433
  lines w0.12: 156.658,33.036 156.66,33.036 156.66,-42.666 163.314,-42.666 ; 156.66,-22.651 163.314,-22.651 ; 156.66,-4.667 163.314,-4.667 ; 156.66,7.347 163.314,7.347 ; 172.003,-22.676 178.658,-22.676 ; 172.003,-4.667 178.658,-4.667 ; 172.003,7.347 178.658,7.347 ; 172.027,-42.666 178.658,-42.666 178.658,33.036
  lines w0.2: 10.5,-42.5 145,-42.5 145,42.5 10.5,42.5
  lines w0.254: 24.489,-73.993 24.489,-62.993 69.489,-62.993 69.489,-73.993 ; 47.503,73.615 47.503,62.615 92.503,62.615 92.503,73.615 ; 71.498,-74.01 71.498,-63.01 116.498,-63.01 116.498,-74.01 ; 94.511,73.597 94.511,62.597 139.511,62.597 139.511,73.597 ; 123,-74 123,-63 173,-63 173,-74 ; 175,-74 175,-63 225,-63 225,-74
  lines w0.267: 42.572,-63.571 42.575,-63.571 ; 42.854,-63.736 43.4,-64.053 ; 43.4,-65.018 43.403,-65.018 ; 43.4,-64.688 43.4,-64.053 ; 43.946,-63.736 43.4,-64.053 ; 44.236,-63.571 44.239,-63.571 ; 65.715,64.784 65.717,64.784 ; 65.997,64.619 66.543,64.301 ; 66.543,63.336 66.545,63.336 ; 66.543,63.666 66.543,64.301 ; 67.089,64.619 66.543,64.301 ; 67.378,64.784 67.381,64.784 ; 89.6,-63.538 89.603,-63.538 ; 89.882,-63.703 90.428,-64.02 ; 90.428,-64.985 90.431,-64.985 ; 90.428,-64.655 90.428,-64.02 ; 90.975,-63.703 90.428,-64.02 ; 91.264,-63.538 91.267,-63.538 ; 112.921,64.726 112.923,64.726 ; 113.202,64.56 113.749,64.243 ; 113.749,63.278 113.751,63.278 ; 113.749,63.608 113.749,64.243 ; 114.295,64.56 113.749,64.243 ; 114.584,64.726 114.587,64.726 ; 143.854,-63.519 143.857,-63.519 ; 144.136,-63.685 144.682,-64.002 ; 144.682,-64.967 144.685,-64.967 ; 144.682,-64.637 144.682,-64.002 ; 145.229,-63.685 144.682,-64.002 ; 145.518,-63.519 145.521,-63.519 ; 195.854,-63.519 195.857,-63.519 ; 196.136,-63.685 196.682,-64.002 ; 196.682,-64.967 196.685,-64.967 ; 196.682,-64.637 196.682,-64.002 ; 197.229,-63.685 196.682,-64.002 ; 197.518,-63.519 197.521,-63.519
  lines w0.508: 196.475,-7.029 196.475,5.223 224.494,5.223 224.494,-7.029 196.475,-7.029 ; 196.481,11.5 224.5,11.5 224.5,39.5 196.481,39.5 196.481,11.5 ; 196.481,45.474 224.5,45.474 224.5,73.474 196.481,73.474 196.481,45.474 ; 231,-7 231,17 231,27 238.75,27 238.75,-7 231,-7 ; 231,29 238.75,29 238.75,63 231,63 231,53.5 231,29
  text "2:Vref" at 26.358,74.022 h1.02 r270
  text "4:TMS" at 28.339,74.022 h1.02 r270
  text "6:TCK" at 30.345,74.022 h1.02 r270
  text "8:TDO" at 32.301,74.022 h1.02 r270
  text "10:TDI" at 34.308,74.022 h1.02 r270
  text "SYZYGY" at 67.914,63.539 h1.02
  text "SYZYGY" at 115.12,63.481 h1.02
  text "PORT B / VIO1" at 94.912,62.973 h1.02
  text "PORT A / VIO1" at 47.897,62.871 h1.02
  text "SATA 1" at 156.583,62.3 h1.27
  text "SATA 2" at 176.7,62.3 h1.27
  text "DGND" at 87.887,50.585 h0.76
  text "DGND" at 133.828,50.585 h0.76
  text "DGND" at 89.887,-50.915 h0.76
  text "'.Part_Number' / '.PCB_Revision'XX" at 21.303,-56.458 h1.02
  text "SYZYGY" at 146.054,-64.764 h1.02
  text "SYZYGY" at 198.054,-64.764 h1.02
  text "SYZYGY" at 91.8,-64.782 h1.02
  text "SYZYGY" at 44.772,-64.815 h1.02
  text "PORT C / VIO2" at 63.01,-66.364 h1.02
  text "PORT E / VIO2" at 166.54,-66.389 h1.02
  text "PORT F / VIO2" at 218.661,-66.389 h1.02
  text "PORT D / VIO2" at 110.076,-66.415 h1.02
Dimensions:
  text ":::" at 94.48,76.847 h1.27 r180
  text ":::" at 190.543,75.749 h1.27
  text ":::" at 241.337,29.394 h1.27 r270
  text ":::" at -1.041,28.194 h1.27 r90
  text ":::" at -1.346,-31.039 h1.27 r90
  text ":::" at 241.337,-61.233 h1.27 r270
  text ":::" at 71.526,-76.022 h1.27 r180
  text ":::" at 175.184,-76.606 h1.27 r180
Outline:
  the board outline again, w0.203
Fab Notes:
  drawing of 503 lines, arcs and shapes, not listed
  text "NOTES: /  / 1. MATERIAL SELECTION: /      8-LAYER, IT-180A OR EQUIVALENT, 62 MILS +/-10% THICK /      SURFACE FINISH: ENIG (ELECTROLESS NICKEL, IMMERSION GOLD) /  / 2. SOLDER RESIST: BLUE LPI /  / 3. SILKSCREEN: WHITE / DO NOT REMOVE OVER TENTED VIAS /  / 4. LOT CODE IDENTIFICATION: ADD TO SILKSCREEN /      FORMAT: YYWW (YY = 2-DIGIT YEAR, WW = 2-DIGIT WEEK) /       / 5. DRILL SIZES ARE FINISHED SIZE AFTER PLATING /  / 6. ELECTRICAL BARE BOARD TEST REQUIRED /  / 7. BOARD TO BE IMPEDANCE CONTROLLED. /      REFER TO '.Part_Number'-PCBStackup.pdf /      SHORT TRACE IMPEDANCE MEASUREMENTS CAN DEFAULT TO TDR COUPONS /   / 8. PANELIZATION: /      2 PIECES PER ARRAY /      TAB ROUTING REQUIRED /      TAB LOCATIONS INDICATED BY ::: /      0.25-INCH RAILS ON ALL SIDES /       / 9. ALL 8.00-MIL VIAS MUST BE PLATED OVER FILLED VIA (POFV) /  / 10. FABRICATE TO MEET EU ROHS DIRECTIVE. /      SUPPLIER TO ADD LEAD-FREE MARKING IN SILKSCREEN. /       / 11. UL CERTIFICATION MARK REQUIRED" at -8.103,95.225 h1.27
  text "LAYER STACKUP TABLE" at 273.937,72.249 h1.27
  text "Layer" at 275.142,69.126 h1.27
  text "Name" at 283.801,69.126 h1.27
  text "Material" at 303.464,69.126 h1.27
  text "Thickness" at 321.646,69.126 h1.27
  text "Constant" at 335.384,69.126 h1.27
  text "Board Layer Stack" at 347.429,69.126 h1.27
  text "Top Overlay" at 283.801,66.586 h1.27
  text "Top Solder" at 283.801,64.046 h1.27
  text "Solder Resist" at 303.464,64.046 h1.27
  text "0.80mil" at 321.646,64.046 h1.27
  text "0" at 335.384,64.046 h1.27
  text "1" at 275.142,61.506 h1.27
  text "L1-TOP" at 283.801,61.506 h1.27
  text "Copper" at 303.464,61.506 h1.27
  text "1.40mil" at 321.646,61.506 h1.27
  text "Dielectric 2" at 283.801,58.966 h1.27
  text "IT180A" at 303.464,58.966 h1.27
  text "3.19mil" at 321.646,58.966 h1.27
  text "3.79" at 335.384,58.966 h1.27
  text "2" at 275.142,56.426 h1.27
  text "L2-GND" at 283.801,56.426 h1.27
  text "Copper" at 303.464,56.426 h1.27
  text "1.40mil" at 321.646,56.426 h1.27
  text "Dielectric 1" at 283.801,53.886 h1.27
  text "IT180A" at 303.464,53.886 h1.27
  text "10.41mil" at 321.646,53.886 h1.27
  text "4.35" at 335.384,53.886 h1.27
  text "3" at 275.142,51.346 h1.27
  text "L3-PWR" at 283.801,51.346 h1.27
  text "Copper" at 303.464,51.346 h1.27
  text "1.40mil" at 321.646,51.346 h1.27
  text "Dielectric 3" at 283.801,48.806 h1.27
  text "IT180A" at 303.464,48.806 h1.27
  text "3.74mil" at 321.646,48.806 h1.27
  text "3.61" at 335.384,48.806 h1.27
  text "4" at 275.142,46.266 h1.27
  text "L4-SIG" at 283.801,46.266 h1.27
  text "Copper" at 303.464,46.266 h1.27
  text "1.40mil" at 321.646,46.266 h1.27
  text "Dielectric 5" at 283.801,43.726 h1.27
  text "IT180A" at 303.464,43.726 h1.27
  text "11.81mil" at 321.646,43.726 h1.27
  text "4.35" at 335.384,43.726 h1.27
  text "5" at 275.142,41.186 h1.27
  text "L5-SIG" at 283.801,41.186 h1.27
  text "Copper" at 303.464,41.186 h1.27
  text "1.40mil" at 321.646,41.186 h1.27
  text "Dielectric 6" at 283.801,38.646 h1.27
  text "IT180A" at 303.464,38.646 h1.27
  text "3.74mil" at 321.646,38.646 h1.27
  text "3.61" at 335.384,38.646 h1.27
  text "6" at 275.142,36.106 h1.27
  text "L6-PWR" at 283.801,36.106 h1.27
  text "Copper" at 303.464,36.106 h1.27
  text "1.40mil" at 321.646,36.106 h1.27
  text "Dielectric 7" at 283.801,33.566 h1.27
  text "IT180A" at 303.464,33.566 h1.27
  text "10.41mil" at 321.646,33.566 h1.27
  text "4.35" at 335.384,33.566 h1.27
  text "7" at 275.142,31.026 h1.27
  text "L7-GND" at 283.801,31.026 h1.27
  text "Copper" at 303.464,31.026 h1.27
  text "1.40mil" at 321.646,31.026 h1.27
  text "Dielectric 4" at 283.801,28.486 h1.27
  text "IT180A" at 303.464,28.486 h1.27
  text "3.19mil" at 321.646,28.486 h1.27
  text "3.79" at 335.384,28.486 h1.27
  text "8" at 275.142,25.946 h1.27
  text "L8-BOT" at 283.801,25.946 h1.27
  text "Copper" at 303.464,25.946 h1.27
  text "1.40mil" at 321.646,25.946 h1.27
  text "Solder Side" at 283.801,23.406 h1.27
  text "Solder Resist" at 303.464,23.406 h1.27
  text "0.80mil" at 321.646,23.406 h1.27
  text "0" at 335.384,23.406 h1.27
  text "Bottom Overlay" at 283.801,20.866 h1.27
Assy Notes Top:
  text "NOTES /  / 1. SOLDER QSFP1 AND QSFP2 IN EIGHT PLACES ON BOTTOM SIDE AS INDICATED. /  / 2. KEEP SO1-SO4 CLEAN AND CLEAR OF SOLDER PASTE. /  / 3. JSO1-JSO4 ARE PRESS-FIT ATTACHED TO THE PCB. THE MATING JSO HARDWARE MUST BE ATTACHED TO THE PRESS-FIT PIECE AFTER ASSEMBLY. /  / 4. AFTER SMT ASSEMBLY, ATTACH STANDOFF SO3 USING M2.5 SCREW (OPAL KELLY P/N 001811) AND NUT (OPAL KELLY P/N 001810)." at -2.642,79.477 h1.27
Assy Notes Bot:
  circle w0.254: c195.441,-12.059 r1.88
  circle w0.254: c195.441,-38.059 r1.88
  circle w0.254: c233.141,-12.059 r1.88
  circle w0.254: c237.641,-31.059 r1.88
  circle w0.254: c237.641,-57.059 r1.88
  circle w0.254: c233.141,-38.059 r1.88
  circle w0.254: c199.941,-31.059 r1.88
  circle w0.254: c199.941,-57.059 r1.88
  lines w0.254: 234.404,-10.557 236.563,-8.398 243.68,-8.398
  text "SOLDER ON BOTTOM SIDE / (8 PLACES)" at 270.942,-14.961 h1.52
Drill Drawing:
  drawing of 180 lines, arcs and shapes, not listed
  text "DRILL TABLE" at 224.401,156.775 h1.27
  text "Symbol" at 225.593,152.984 h1.52
  text "Count" at 236.273,152.984 h1.52
  text "Hole Size" at 250.223,152.984 h1.52
  text "Plated" at 274.752,152.984 h1.52
  text "Hole Type" at 285.432,152.984 h1.52
  text "Drill Layer Pair" at 300.937,152.984 h1.52
  text "Via/Pad" at 326.091,152.984 h1.52
  text "Pad Shape" at 338.549,152.984 h1.52
  text "Template" at 354.308,152.984 h1.52
  text "1" at 236.273,149.809 h1.27
  text "43.31mil (1.100mm)" at 250.223,149.809 h1.27
  text "NPTH" at 274.752,149.809 h1.27
  text "Round" at 285.432,149.809 h1.27
  text "L1-TOP - L8-BOT" at 300.937,149.809 h1.27
  text "Pad" at 326.091,149.809 h1.27
  text "Rounded" at 338.549,149.809 h1.27
  text "c110hn110p110" at 354.308,149.809 h1.27
  text "B" at 224.983,149.606 h1.41
  text "1" at 236.273,146.634 h1.27
  text "62.99mil (1.600mm)" at 250.223,146.634 h1.27
  text "NPTH" at 274.752,146.634 h1.27
  text "Round" at 285.432,146.634 h1.27
  text "L1-TOP - L8-BOT" at 300.937,146.634 h1.27
  text "Pad" at 326.091,146.634 h1.27
  text "Rounded" at 338.549,146.634 h1.27
  text "c160hn160p160" at 354.308,146.634 h1.27
  text "2" at 236.273,143.459 h1.27
  text "41.34mil (1.050mm)" at 250.223,143.459 h1.27
  text "NPTH" at 274.752,143.459 h1.27
  text "Round" at 285.432,143.459 h1.27
  text "L1-TOP - L8-BOT" at 300.937,143.459 h1.27
  text "Pad" at 326.091,143.459 h1.27
  text "Rounded" at 338.549,143.459 h1.27
  text "c0hn105" at 354.308,143.459 h1.27
  text "3" at 236.273,140.284 h1.27
  text "59.06mil (1.500mm)" at 250.223,140.284 h1.27
  text "PTH" at 274.752,140.284 h1.27
  text "Round" at 285.432,140.284 h1.27
  text "L1-TOP - L8-BOT" at 300.937,140.284 h1.27
  text "Pad" at 326.091,140.284 h1.27
  text "Rounded" at 338.549,140.284 h1.27
  text "c225h150" at 354.308,140.284 h1.27
  text "4" at 236.273,137.109 h1.27
  text "53.15mil (1.350mm)" at 250.223,137.109 h1.27
  text "PTH" at 274.752,137.109 h1.27
  text "Round" at 285.432,137.109 h1.27
  text "L1-TOP - L8-BOT" at 300.937,137.109 h1.27
  text "Pad" at 326.091,137.109 h1.27
  text "Rounded" at 338.549,137.109 h1.27
  text "c250h135" at 354.308,137.109 h1.27
  text "4" at 236.273,133.934 h1.27
  text "61.02mil (1.550mm)" at 250.223,133.934 h1.27
  text "NPTH" at 274.752,133.934 h1.27
  text "Round" at 285.432,133.934 h1.27
  text "L1-TOP - L8-BOT" at 300.937,133.934 h1.27
  text "Pad" at 326.091,133.934 h1.27
  text "Rounded" at 338.549,133.934 h1.27
  text "c155hn155" at 354.308,133.934 h1.27
  text "A" at 224.983,133.731 h1.41
  text "4" at 236.273,130.759 h1.27
  text "145.67mil (3.700mm)" at 250.223,130.759 h1.27
  text "PTH" at 274.752,130.759 h1.27
  text "Round" at 285.432,130.759 h1.27
  text "L1-TOP - L8-BOT" at 300.937,130.759 h1.27
  text "Pad" at 326.091,130.759 h1.27
  text "Rounded" at 338.549,130.759 h1.27
  text "c600h370" at 354.308,130.759 h1.27
  text "4" at 236.273,127.584 h1.27
  text "250.00mil (6.350mm)" at 250.223,127.584 h1.27
  text "NPTH" at 274.752,127.584 h1.27
  text "Round" at 285.432,127.584 h1.27
  text "L1-TOP - L8-BOT" at 300.937,127.584 h1.27
  text "Pad" at 326.091,127.584 h1.27
  text "Rounded" at 338.549,127.584 h1.27
  text "c0hn635" at 354.308,127.584 h1.27
  text "10" at 236.273,124.409 h1.27
  text "59.00mil (1.499mm)" at 250.223,124.409 h1.27
  text "PTH" at 274.752,124.409 h1.27
  text "Round" at 285.432,124.409 h1.27
  text "L1-TOP - L8-BOT" at 300.937,124.409 h1.27
  text "Pad" at 326.091,124.409 h1.27
  text "Rounded" at 338.549,124.409 h1.27
  text "c254h150" at 354.308,124.409 h1.27
  text "11" at 236.273,121.234 h1.27
  text "65.00mil (1.651mm)" at 250.223,121.234 h1.27
  text "PTH" at 274.752,121.234 h1.27
  text "Round" at 285.432,121.234 h1.27
  text "L1-TOP - L8-BOT" at 300.937,121.234 h1.27
  text "Pad" at 326.091,121.234 h1.27
  text "Rounded" at 338.549,121.234 h1.27
  text "c254h165" at 354.308,121.234 h1.27
  text "18" at 236.273,118.059 h1.27
  text "40.16mil (1.020mm)" at 250.223,118.059 h1.27
  text "NPTH" at 274.752,118.059 h1.27
  text "Round" at 285.432,118.059 h1.27
  text "L1-TOP - L8-BOT" at 300.937,118.059 h1.27
  text "Pad" at 326.091,118.059 h1.27
  text "Rounded" at 338.549,118.059 h1.27
  text "(Mixed)" at 354.308,118.059 h1.27
  text "18" at 236.273,114.884 h1.27
  text "125.98mil (3.200mm)" at 250.223,114.884 h1.27
  text "PTH" at 274.752,114.884 h1.27
  text "Round" at 285.432,114.884 h1.27
  text "L1-TOP - L8-BOT" at 300.937,114.884 h1.27
  text "Pad" at 326.091,114.884 h1.27
  text "Rounded" at 338.549,114.884 h1.27
  text "c650h320" at 354.308,114.884 h1.27
  text "22" at 236.273,111.709 h1.27
  text "41.34mil (1.050mm)" at 250.223,111.709 h1.27
  text "PTH" at 274.752,111.709 h1.27
  text "Round" at 285.432,111.709 h1.27
  text "L1-TOP - L8-BOT" at 300.937,111.709 h1.27
  text "Pad" at 326.091,111.709 h1.27
  text "Rounded" at 338.549,111.709 h1.27
  text "c200h105" at 354.308,111.709 h1.27
  text "40" at 236.273,108.534 h1.27
  text "67.00mil (1.702mm)" at 250.223,108.534 h1.27
  text "PTH" at 274.752,108.534 h1.27
  text "Round" at 285.432,108.534 h1.27
  text "L1-TOP - L8-BOT" at 300.937,108.534 h1.27
  text "Pad" at 326.091,108.534 h1.27
  text "Rounded" at 338.549,108.534 h1.27
  text "c254h170" at 354.308,108.534 h1.27
  text "206" at 236.273,105.359 h1.27
  text "31.50mil (0.800mm)" at 250.223,105.359 h1.27
  text "PTH" at 274.752,105.359 h1.27
  text "Round" at 285.432,105.359 h1.27
  text "L1-TOP - L8-BOT" at 300.937,105.359 h1.27
  text "Pad" at 326.091,105.359 h1.27
  text "(Mixed)" at 338.549,105.359 h1.27
  text "(Mixed)" at 354.308,105.359 h1.27
  text "2338" at 236.273,102.184 h1.27
  text "8.00mil (0.203mm)" at 250.223,102.184 h1.27
  text "PTH" at 274.752,102.184 h1.27
  text "Round" at 285.432,102.184 h1.27
  text "L1-TOP - L8-BOT" at 300.937,102.184 h1.27
  text "Via" at 326.091,102.184 h1.27
  text "Rounded" at 338.549,102.184 h1.27
  text "v41h20m0mx0" at 354.308,102.184 h1.27
  text "2686 Total" at 236.273,99.009 h1.27
Doc-Assy-Top:
  lines w0.138: -14.591,-61.939 -9.07,-61.939 ; -14.591,-3.277 -9.07,-3.277 ; -14.591,55.385 -9.07,55.385 ; 55.803,-115.079 55.803,-109.558 ; 55.803,103.005 55.803,108.526 ; 131.719,-115.079 131.719,-109.558 ; 131.719,103.005 131.719,108.526 ; 153.803,-115.079 278.028,-115.079 ; 189.792,-109.551 189.792,-89.874 272.484,-89.874 ; 189.792,-102.911 272.484,-102.911 ; 202.271,-109.551 202.271,-102.911 ; 207.634,-115.079 207.634,-109.558 ; 207.634,103.005 207.634,108.526 ; 221.632,-109.551 221.632,-102.911 ; 225.503,-102.902 225.503,-89.874 ; 250.252,-109.551 250.252,-102.911 ; 272.507,-61.939 278.028,-61.939 ; 272.507,-3.277 278.028,-3.277 ; 272.507,55.385 278.028,55.385 ; 278.028,-115.079 -14.591,-115.079 -14.591,108.526 278.028,108.526 278.028,-115.079 ; -9.07,-109.558 272.507,-109.558 272.507,103.005 -9.07,103.005 -9.07,-109.558
  text "1" at 17.192,104.886 h1.93
  text "2" at 93.126,104.886 h1.93
  text "3" at 168.903,104.886 h1.93
  text "4" at 244.847,104.886 h1.93
  text "A" at -12.608,82.218 h1.93
  text "A" at 274.665,82.218 h1.93
  text "B" at -12.608,23.556 h1.93
  text "B" at 274.665,23.556 h1.93
  text "C" at -12.608,-35.106 h1.93
  text "C" at 274.665,-35.106 h1.93
  text "TITLE:" at 191.935,-92.047 h1.24
  text "Opal Kelly" at 227.675,-92.916 h1.93
  text "D" at -12.608,-93.63 h1.93
  text "D" at 274.665,-93.63 h1.93
  text "13500 SW 72nd Ave Suite 100" at 227.675,-96.175 h1.93
  text "Portland, OR 97223" at 227.675,-98.891 h1.93
  text "'.Part_Number' / Assembly Drawing" at 192.828,-98.938 h1.93
  text "www.opalkelly.com" at 227.675,-101.607 h1.93
  text "(Top)" at 192.828,-102.083 h1.93
  text "REV:" at 191.328,-104.75 h1.24
  text "SIZE:" at 203.954,-104.75 h1.24
  text "ENGINEER:" at 223.315,-104.75 h1.24
  text "DATE:" at 251.936,-104.75 h1.24
  text "'.PCB_Revision'XX" at 193.011,-108.118 h1.93
  text "ANSI A" at 205.638,-108.118 h1.93
  text "NDK" at 224.999,-108.118 h1.93
  text ".PRINT_DATE" at 253.619,-108.118 h1.93
  text "1" at 17.192,-113.372 h1.93
  text "2" at 93.126,-113.372 h1.93
  text "3" at 168.903,-113.372 h1.93
  text "4" at 244.847,-113.372 h1.93
Doc-Assy-Bot:
  lines w0.138: -14.588,-61.913 -9.067,-61.913 ; -14.588,-3.25 -9.067,-3.25 ; -14.588,55.414 -9.067,55.414 ; -9.044,-102.886 73.65,-102.886 ; -9.044,-89.849 73.65,-89.849 73.65,-109.526 ; 13.189,-109.526 13.189,-102.886 ; 37.939,-102.878 37.939,-89.849 ; 41.81,-109.526 41.81,-102.886 ; 55.808,-115.055 55.808,-109.534 ; 55.808,103.034 55.808,108.556 ; 61.171,-109.526 61.171,-102.886 ; 109.64,-115.055 -14.588,-115.055 ; 131.725,-115.055 131.725,-109.534 ; 131.725,103.034 131.725,108.556 ; 207.642,-115.055 207.642,-109.534 ; 207.642,103.034 207.642,108.556 ; 272.517,-61.913 278.038,-61.913 ; 272.517,-3.25 278.038,-3.25 ; 272.517,55.414 278.038,55.414 ; -14.588,-115.055 -14.588,108.556 278.038,108.556 278.038,-115.055 -14.588,-115.055 ; -9.067,-109.534 -9.067,103.034 272.517,103.034 272.517,-109.534 -9.067,-109.534
  text "4" at 18.594,104.916 h1.93
  text "3" at 94.539,104.916 h1.93
  text "2" at 170.318,104.916 h1.93
  text "1" at 246.254,104.916 h1.93
  text "A" at -11.224,82.247 h1.93
  text "A" at 276.054,82.247 h1.93
  text "B" at -11.224,23.584 h1.93
  text "B" at 276.054,23.584 h1.93
  text "C" at -11.224,-35.08 h1.93
  text "C" at 276.054,-35.08 h1.93
  text "TITLE:" at 71.507,-92.022 h1.24
  text "Opal Kelly" at 35.766,-92.891 h1.93
  text "D" at -11.224,-93.605 h1.93
  text "D" at 276.054,-93.605 h1.93
  text "13500 SW 72nd Ave Suite 100" at 35.766,-96.15 h1.93
  text "Portland, OR 97223" at 35.766,-98.866 h1.93
  text "'.Part_Number' / Assembly Drawing" at 70.614,-98.913 h1.93
  text "www.opalkelly.com" at 35.766,-101.582 h1.93
  text "(Bottom)" at 70.614,-102.058 h1.93
  text "DATE:" at 11.505,-104.726 h1.24
  text "ENGINEER:" at 40.126,-104.726 h1.24
  text "SIZE:" at 59.487,-104.726 h1.24
  text "REV:" at 72.114,-104.726 h1.24
  text ".PRINT_DATE" at 9.821,-108.093 h1.93
  text "NDK" at 38.443,-108.093 h1.93
  text "ANSI A" at 57.804,-108.093 h1.93
  text "'.PCB_Revision'XX" at 70.431,-108.093 h1.93
  text "4" at 18.594,-113.347 h1.93
  text "3" at 94.539,-113.347 h1.93
  text "2" at 170.318,-113.347 h1.93
  text "1" at 246.254,-113.347 h1.93
Doc-Fab:
  lines w0.127: 273.583,-83.112 273.583,-56.286 388.879,-56.286 ; 273.583,-77.47 318.287,-77.47 ; 273.583,-72.415 318.287,-72.415 ; 273.583,-69.444 318.287,-69.444 ; 273.583,-66.472 318.287,-66.472 ; 273.583,-61.112 318.287,-61.112 ; 273.583,-58.318 318.287,-58.318 ; 284.251,-83.112 284.251,-56.286 ; 318.287,-83.112 318.287,-56.286 ; 318.287,-78.13 388.899,-78.13 ; 318.287,-66.954 388.879,-66.954 ; 332.511,-83.112 332.511,-78.13 ; 349.783,-78.13 349.783,-66.954 ; 366.293,-83.112 366.293,-78.13
  lines w0.14: -24.202,-22.449 -18.619,-22.449 ; -24.202,43.843 -18.619,43.843 ; -24.202,110.136 -18.619,110.136 ; 45.58,-88.741 45.58,-83.159 ; 45.58,170.846 45.58,176.428 ; 115.361,-88.741 115.361,-83.159 ; 115.361,170.846 115.361,176.428 ; 185.143,-88.741 185.143,-83.159 ; 185.143,170.846 185.143,176.428 ; 254.924,-88.741 254.924,-83.159 ; 254.924,170.846 254.924,176.428 ; 324.706,-88.741 324.706,-83.159 ; 324.706,170.846 324.706,176.428 ; 388.905,-22.449 394.487,-22.449 ; 388.905,43.843 394.487,43.843 ; 388.905,110.136 394.487,110.136 ; -24.202,-88.741 394.487,-88.741 394.487,176.428 -24.202,176.428 -24.202,-88.741 ; -18.619,-83.159 388.905,-83.159 388.905,170.846 -18.619,170.846 -18.619,-83.159
  text "1" at 10.168,172.8 h1.95
  text "2" at 79.828,172.8 h1.95
  text "3" at 149.313,172.8 h1.95
  text "4" at 219.28,172.8 h1.95
  text "5" at 289.034,172.8 h1.95
  text "6" at 358.955,172.8 h1.95
  text "A" at -22.108,140.896 h1.95
  text "A" at 390.998,140.896 h1.95
  text "B" at -22.108,74.464 h1.95
  text "B" at 390.998,74.464 h1.95
  text "C" at -22.108,8.171 h1.95
  text "C" at 390.998,8.171 h1.95
  text "REVISION:" at 274.32,-57.81 h1.02
  text "DESCRIPTION:" at 285.242,-57.81 h1.02
  text "D" at -22.108,-57.982 h1.95
  text "D" at 390.998,-57.982 h1.95
  text "PART NUMBER:" at 320.319,-59.842 h1.91
  text "AXX" at 274.345,-60.35 h1.27
  text "Initial Release" at 285.267,-60.35 h1.27
  text "BXX" at 274.345,-63.144 h1.27
  text "Added solder paste apertures to M.2 connector footprint" at 285.115,-66.033 h1.27
  text "'.Part_Number'-PCB-'.PCB_Revision'XX" at 320.827,-66.954 h3.3
  text "CXX" at 274.345,-68.504 h1.27
  text "TITLE:" at 319.811,-68.986 h1.02
  text "Updates for new XEM8350 outline" at 285.115,-69.079 h1.27
  text "Opal Kelly" at 351.307,-69.494 h1.52
  text "DXX" at 274.345,-71.476 h1.27
  text "13500 SW 72nd Ave Suite 100" at 351.307,-72.034 h1.52
  text "Updated TXR-2 ports to TXR-4" at 285.115,-72.051 h1.27
  text "EXX" at 274.371,-74.445 h1.27
  text "Portland, OR 97223" at 351.307,-74.574 h1.52
  text "'.Part_Number' / Fabrication Drawing" at 320.827,-76.606 h1.52
  text "www.opalkelly.com" at 351.307,-77.114 h1.52
  text "Updated QSFP mtg holes to non-plated, updated U3 gnd planes" at 285.14,-77.333 h1.27
  text "SIZE:" at 319.811,-79.654 h1.02
  text "ENGINEER:" at 334.035,-79.654 h1.02
  text "DATE:" at 367.563,-79.654 h1.02
  text "ANSI A" at 320.827,-82.194 h1.52
  text "NDK" at 335.051,-82.194 h1.52
  text ".PRINT_DATE" at 368.579,-82.194 h1.52
  text "1" at 10.168,-86.788 h1.95
  text "2" at 79.828,-86.788 h1.95
  text "3" at 149.313,-86.788 h1.95
  text "4" at 219.28,-86.788 h1.95
  text "5" at 289.034,-86.788 h1.95
  text "6" at 358.955,-86.788 h1.95

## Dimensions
0,-75 to 235,70 on Dimensions
0,-75 to 5,70 on Dimensions
0,-75 to 5,70 on Dimensions
0,-75 to 240,75 on Dimensions
5,-70 to 0,-75 on Dimensions
0,-75 to 0,75 on Dimensions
